// TwinCAT 3 PLC project PLC
// ProgramVersion: 3.1.4024.0
// libraries:
//   Tc2_ControllerToolbox, * (Beckhoff Automation GmbH)
//   Tc2_Standard, * (Beckhoff Automation GmbH)
//   Tc2_SUPS, * (Beckhoff Automation GmbH)
//   Tc2_System, * (Beckhoff Automation GmbH)
//   Tc2_TempController, * (Beckhoff Automation GmbH)
//   Tc2_Utilities, * (Beckhoff Automation GmbH)
//   Tc3_Module, * (Beckhoff Automation GmbH)
// project tree:
//   DUTs/Config/ ConfigChiller.TcDUT, ConfigDryPump.TcDUT, ConfigElectrostaticVoltageSource.TcDUT, ConfigEPD.TcDUT, ConfigHeater.TcDUT, ConfigHighTempChiller.TcDUT, ConfigIdleClean.TcDUT, ConfigMfcVer.TcDUT, ConfigMfcGas.TcDUT, ConfigPM.TcDUT, ConfigPump.TcDUT, ConfigPendulumValve.TcDUT, ConfigPurge.TcDUT, ConfigTurboPump.TcDUT
//   DUTs/DateType/ STR_PID.TcDUT, SVINT.TcDUT, SVLREAL.TcDUT
//   DUTs/ECC/APC/ APCControlAI.TcDUT, APCControlAO.TcDUT, APCControlDI.TcDUT, APCst.TcDUT, APC_Controller.TcDUT, CKD_IN.TcDUT, CKD_OUT.TcDUT, STR_APC.TcDUT, VAT_IN.TcDUT, VAT_OUT.TcDUT
//   DUTs/ECC/Axis/ STR_Axis_Panasonic.TcDUT, STR_Axis_Yaskawa.TcDUT
//   DUTs/ECC/BECKOFF/ STR_EL1889.TcDUT, STR_EL2889.TcDUT, STR_EL3154.TcDUT, STR_EL3164.TcDUT, STR_EL6022.TcDUT
//   DUTs/ECC/CHAMBER/ CHAMBER_IN.TcDUT, CHAMBER_OUT.TcDUT
//   DUTs/ECC/CHILLER/ CHILLER_IN.TcDUT, CHILLER_OUT.TcDUT
//   DUTs/ECC/EDWARDS/ TMP_IN.TcDUT, TMP_OUT.TcDUT
//   DUTs/ECC/HEATER/Mini8_16DI16DO/ STR_Mini8_16DI16DO_In.TcDUT, STR_Mini8_16DI16DO_Out.TcDUT
//   DUTs/ECC/HEATER/Mini8_8DI8DO/ STR_Mini8_8DI8DO_In.TcDUT, STR_Mini8_8DI8DO_Out.TcDUT
//   DUTs/ECC/HEATER/Mini8_XML/ STR_HEATER_LINE_CUS_IN.TcDUT, STR_HEATER_LINE_CUS_OUT.TcDUT, STR_HEATER_LINE_SYS_IN.TcDUT, STR_HEATER_LINE_SYS_OUT.TcDUT
//   DUTs/ECC/HEATER/ STR_HEATER_FURNACE.TcDUT, STR_HEATER_LINE.TcDUT
//   DUTs/ECC/IGS/ IGS_IN.TcDUT, IGS_OUT.TcDUT
//   DUTs/ECC/Meter/ Meter_Data.TcDUT
//   DUTs/ECC/MFC MFM/ STR_FCSP700_INPUT.TcDUT, STR_FCSP700_OUTPUT.TcDUT, STR_SEC_N107.TcDUT, STR_SEC_Z507.TcDUT, STR_SEF_N107.TcDUT, STR_SEF_Z507.TcDUT
//   DUTs/ECC/VALVE/ STR_EX260_SEC.TcDUT, STR_USINT_BOOL.TcDUT
//   DUTs/ECC/VG/ STR_BPG400.TcDUT, STR_CDG200D.TcDUT, VG_Data.TcDUT, VG_INPUT.TcDUT
//   DUTs/Info/ Intelock.TcDUT, ProcessRecipeFeedBack.TcDUT, Alarm.TcDUT, Warning.TcDUT, Info.TcDUT
//   DUTs/IO/ STR_AI.TcDUT, STR_AO.TcDUT, STR_NDI.TcDUT, STR_NDO.TcDUT
//   DUTs/Recipe/ Lst.TcDUT, RecipeEachStep.TcDUT
//   DUTs/Recipe/LST/ LstBIASUnit.TcDUT, LstGas.TcDUT, LstHeater.TcDUT, LstPressure.TcDUT, LstTCPUnit.TcDUT
//   DUTs/SPLC/ PLC_TO_SPLC.TcDUT, SPLC_TO_PLC.TcDUT
//   GVLs/ ECC.TcGVL, GV.TcGVL, GV_H.TcGVL, GV_IL.TcGVL
//   GVLs/PC_PLC/ PM.TcGVL, UI.TcGVL
//   / PlcTask.TcTTO
//   POUs/FB/ PID_AutoTune.TcPOU, PROCESS.TcPOU, RANGEJD.TcPOU, Temp_controller.TcPOU, Tolerance.TcPOU
//   POUs/PRG/ IL.TcPOU, IO_EXCHANGE.TcPOU, MAIN.TcPOU, Temp.TcPOU

CONFIGURATION PLC
    RESOURCE PLC ON TwinCAT3
        TASK PlcTask(INTERVAL := T#10ms, PRIORITY := 20);
        PROGRAM MAIN WITH PlcTask : MAIN;
    END_RESOURCE
END_CONFIGURATION

// ---- DUTs/Config/ConfigChiller.TcDUT
TYPE ConfigChiller :
STRUCT
	Enable:BOOL;
	MFG:SVINT;
	CommType:SVINT;
	Port:STRING;
	TempOffset:SVLREAL;
	MaxLimit:SVLREAL;
	MinLimit:SVLREAL;
	EnableAlarmTolerance:BOOL;
	ToleranceAlarmRange:SVINT;
	ToleranceAlarmTime:SVINT;
END_STRUCT
END_TYPE

// ---- DUTs/Config/ConfigDryPump.TcDUT
TYPE ConfigDryPump :
STRUCT
	MFG:SVINT;
	CommType:SVINT;
	Port:STRING;
	ChamberForlinePressureTolerance:SVLREAL;
	ChamberForlinePressureTimeout:SVINT;
END_STRUCT
END_TYPE

// ---- DUTs/Config/ConfigElectrostaticVoltageSource.TcDUT
TYPE ConfigElectrostaticVoltageSource :
STRUCT
	Port:STRING;
END_STRUCT
END_TYPE

// ---- DUTs/Config/ConfigEPD.TcDUT
TYPE ConfigEPD :
STRUCT
	IsEnabled:BOOL;
	ChannelNumber:SVINT;
	IPAdress:STRING;
	EPDType:SVINT;
END_STRUCT
END_TYPE

// ---- DUTs/Config/ConfigHeater.TcDUT
TYPE ConfigHeater :
STRUCT
	HeaterTolerance_Enable:BOOL;
	HeaterAlarmRange:SVINT;
	HeaterAlarmTime:SVINT;
	HeaterWarningRange:SVINT;
	HeaterWarningTime:SVINT;
(*	
	TempOffsetPoint1:SVINT;
		OffsetValue1:SVLREAL;
		
	TempOffsetPoint2:SVINT;
		OffsetValue2:SVLREAL;
		
	TempOffsetPoint3:SVINT;
		OffsetValue3:SVLREAL;
		
	TempOffsetPoint4:SVINT;
		OffsetValue4:SVLREAL;
		
	TempOffsetPoint5:SVINT;
		OffsetValue5:SVLREAL;
		
	TempOffsetPoint6:SVINT;
		OffsetValue6:SVLREAL;
		
	TempOffsetPoint7:SVINT;
		OffsetValue7:SVLREAL;
		
	TempOffsetPoint8:SVINT;
		OffsetValue8:SVLREAL;
		
	TempOffsetPoint9:SVINT;
		OffsetValue9:SVLREAL;
		
	TempOffsetPoint10:SVINT;
		OffsetValue10:SVLREAL;
		*)
END_STRUCT
END_TYPE

// ---- DUTs/Config/ConfigHighTempChiller.TcDUT
TYPE ConfigHighTempChiller :
STRUCT
	LiftServoPosition1:SVLREAL;
	LiftServoPosition2:SVLREAL;
	LiftServoPosition3:SVLREAL;
	LiftServoPosition4:SVLREAL;
	LiftServoPosition5:SVLREAL;
	
	OriginSearchHighSpeed:SVLREAL;
	OriginSearchLowSpeed:SVLREAL;
	
	AbsMoveSpeed:SVLREAL;
	MaxMoveSpeed:SVLREAL;
	
	SoftDownLimit:SVLREAL;
	SoftUpLimit:SVLREAL;
END_STRUCT
END_TYPE

// ---- DUTs/Config/ConfigIdleClean.TcDUT
TYPE ConfigIdleClean :
STRUCT
	Option:SVINT;
	
	IdleCleanRecipe:STRING;
	IdleCleanTime:SVINT;
	IdleCleanWaferCount:SVINT;
	
	WaferCountSinceLastClean:SVINT;
	LastRunTime:STRING;
END_STRUCT
END_TYPE

// ---- DUTs/Config/ConfigMfcVer.TcDUT
TYPE ConfigMfcVer :
STRUCT
	BasePressure:SVLREAL;
	PumpingTime:SVINT;
	GasFlowTime:SVINT;
	HoldTime:SVINT;
	TargetPressure:SVLREAL;
	MaxDeviation:SVLREAL;
	PressureStableTolerance:SVLREAL;
	FlowStableTolerance:SVLREAL;
END_STRUCT
END_TYPE

// ---- DUTs/Config/ConfigMfcGas.TcDUT
TYPE ConfigMfcGas :
STRUCT
	Enable:BOOL;
	GasName:STRING;
	N2Scale:SVINT;
	ScaleFactor:SVLREAL;
	DefaultSV:SVINT;
	FlowRegulationFactor:SVINT;
	EnableAlarm:BOOL;
	AlarmRange:SVINT;
	AlarmTime:SVINT;
	WarningRange:SVINT;
	WarningTime:SVINT;
	WriteMode:SVINT;
END_STRUCT
END_TYPE

// ---- DUTs/Config/ConfigPM.TcDUT
TYPE ConfigPM :
STRUCT
	//TurboN2FlowSetPoint:LREAL;			//0-200		mtorr
	TurboN2Pressure:INT;
	PrepareTransferTimeout:INT;				//1-99999	s
	TransferWaferTimeout:INT;				//1-99999	s
	OpenGasValveTimeout:INT;				//0-60		s
	CloseGasValveTimeout:INT;				//0-10
	OpenCloseSlitValveTimeout:INT;			//0-10
	GasFlowPressureAlarmRange:LREAL;		//0-760000	mtorr
	GasFlowPressureAlarmTime:LREAL;			//0-3600	s
	GasFlowPressureWarningRange:LREAL;		//0-760000	mtorr
	GasFlowPressureWarningTime:LREAL;		//0-3600	s
	EnableThrottleValve:BOOL;				//0-10				//不清楚作用
	ValveHeaterSetPointLimit:INT;			//0-500
	ForeLineHeaterSetPointLimit:INT;		//0-500
	CheckSubstrateTempTimeout:INT;			//0-3600			//不清楚作用
	CheckATMTimeout:INT;					//0-3000	s
	OverVentTime:UINT;						//0-60000	ms		充气至常压
	ChamberBasePressureThreshold:UDINT;		//0-1000000	mtorr	腔体基础压力门槛	工艺开始压力？腔体压力下限？
	ChamberBaseTemperatureThreshold:LREAL;	//0-1000	℃		腔体基础温度门槛	工艺开始温度？腔体温度下限？
	ProcessPressureOffset:LREAL;			//0-100		mtorr
	PickDelayTime:INT;						//0-10000	ms
	PlaceDelayTime:INT;						//0-10000	ms
	ChamberLabel:STRING;					//''
	WallHeaterSetPointLimit:INT;			//0-500
	PendulumHeaterSetPointLimit:INT;		//0-500
	EnableWallHeater:BOOL;					//0-10
	EnableGridHeater:BOOL;					//0-10
	(*RecipeToleranceIgnoreTime:INT;		//0-60		s	Tolerance失效时间,用不到*)
	RecipeRunningMode:INT;					//0-5
	ForelineInterlockPressure:LREAL;		//500-2000	℃
	IsEnableRecipeExtension:BOOL;			//0-10
	ControlPressureSetPoint:INT;			//0-2000	mtorr
	ControlPressureN2FlowSetPoint:INT;		//0-500		sccm	
	PMStableTime:INT;						//0-100		s
END_STRUCT
END_TYPE

// ---- DUTs/Config/ConfigPump.TcDUT
TYPE ConfigPump :
STRUCT
	LeakRate:SVLREAL;
	
	LeakCheckPumpingTime:SVINT;
	LeakCheckHoldTime:SVINT;
	
	PumpBasePressure:SVINT;
	LeakCheckBasePressur:SVLREAL;
	
	LeakCheckGasLineNums:STRING;
	
	PumpTimeLimit:SVLREAL;
	PumpValveDelay:SVINT;
	
	PumpCrossingPressure:SVINT;
	PumpVHe2FlowPressure:SVINT;
	
	LoadLockPumpBasePressure:SVINT;
	LoadLockPumpTimeLimit:SVINT;
	
	LoadLockPurgeVentPressure:SVINT;
	LoadLockPurgeCycleCount:SVINT;
	LoadLockPurgePumpTime:SVINT;
	
	LoadLockLeakCheckPumpTime:SVINT;
	LoadLockLeakCheckWaitTime:SVINT;
	LoadLockLeakRate:SVLREAL;
END_STRUCT
END_TYPE

// ---- DUTs/Config/ConfigPendulumValve.TcDUT
TYPE ConfigPendulumValve :
STRUCT
	Port:STRING;
	PressureFullRange:SVINT;
	ForelinePressureLimit:SVINT;
	ChamberPressureLimit:SVINT;
	TurboPumpSpeedLimit:SVINT;
END_STRUCT
END_TYPE

// ---- DUTs/Config/ConfigPurge.TcDUT
TYPE ConfigPurge :
STRUCT
	PurgeCycleCount:SVINT;
	
	PurgeVentPressure:SVINT;
	PurgePumpPressure:SVINT;
	
	PurgeVentTimeLimit:SVINT;
	PurgePumpTimeLimit:SVINT;
	
	PurgeVentStableTime:SVINT;
	PurgePumpTime:SVINT;
	
	GasPurgeCycleCount:SVINT;
	GasPurgeFlowTime:SVINT;
	GasPurgePumpTime:SVINT;
END_STRUCT
END_TYPE

// ---- DUTs/Config/ConfigTurboPump.TcDUT
TYPE ConfigTurboPump :
STRUCT
	Port:STRING;
	ChamberForelinePressureThreshold:SVLREAL;
	ChamberForelinePressureTimeout:SVINT;
END_STRUCT
END_TYPE

// ---- DUTs/DateType/STR_PID.TcDUT
TYPE STR_PID :
STRUCT
	P,
	I,
	D,
	DP,
	Feedforward,
	Output_Limit:REAL;
END_STRUCT
END_TYPE

// ---- DUTs/DateType/SVINT.TcDUT
TYPE SVINT :
STRUCT
	MinSV:INT;
	MaxSV:INT;
	PV:INT;
	SV:INT;
END_STRUCT
END_TYPE

// ---- DUTs/DateType/SVLREAL.TcDUT
TYPE SVLREAL :
STRUCT
	MinSV:LREAL;
	MaxSV:LREAL;
	PV:LREAL;
	SV:LREAL;
END_STRUCT
END_TYPE

// ---- DUTs/ECC/APC/APCControlAI.TcDUT
TYPE APCControlAI :
STRUCT
	Value_sensor_input1_p1	:	REAL	;
	Value_sensor_input1_p2	:	REAL	;
	Select_controller_using	:	REAL	;
	Position_actual_value	:	REAL	;
	Control_mode_status	:	REAL	;
	HOME_status	:	REAL	;
	Warning_Device_Management	:	REAL	;
	Warning_Sensor_Input1	:	REAL	;
	Warning_Sensor_Input2	:	REAL	;
	Warning_Process_Controller_Selector	:	REAL	;
	Warning_Valve	:	REAL	;
	Manufacturer_Warning_Valve	:	REAL	;
	ERROR_Device_Management	:	REAL	;
	ERROR_sensor_input1_p1	:	REAL	;
	ERROR_sensor_input1_p2	:	REAL	;
	ERROR_Valve	:	REAL	;

END_STRUCT
END_TYPE

// ---- DUTs/ECC/APC/APCControlAO.TcDUT
TYPE APCControlAO :
STRUCT
	Zero_Reset_P1	:	REAL	;
	Zero_adjust_P1	:	REAL	;
	Span_adjust_P1	:	REAL	;
	Zero_Reset_P2	:	REAL	;
	Zero_adjust_P2	:	REAL	;
	Span_adjust_P2	:	REAL	;
	Slow_vacuum_control_target_vacuum_Pressure	:	REAL	;
	Valve_status_threshold	:	REAL	;
	Forbid_interlock_outbreak	:	REAL	;
	Slow_vacuum_mode_setting	:	REAL	;
	Interlock1	:	REAL	;
	Interlock2	:	REAL	;
	Interlock3	:	REAL	;
	Interlock_constant_of_interlock3	:	REAL	;
	P1_sensor_offset_setting	:	REAL	;
	Pos_mon_offset_setting	:	REAL	;
	Sensor_adjust_reset	:	REAL	;
	Slow_vacuum_rate	:	REAL	;
	Slow_vacuum_control_P	:	REAL	;
	Slow_vacuum_control_I	:	REAL	;
	Slow_vacuum_control_D	:	REAL	;
	Slow_vacuum_control_a	:	REAL	;
	controller_mode_select	:	REAL	;
	Specify_target_vacuum_Pressure_control	:	REAL	;
	Specify_target_opening_for_valve_opening_control	:	REAL	;
	Specify_control_mode	:	REAL	;
	Range_Upper_Limit_Sensor_Input1	:	REAL	;
	Range_Upper_Limit_Sensor_Input2	:	REAL	;

END_STRUCT
END_TYPE

// ---- DUTs/ECC/APC/APCControlDI.TcDUT
TYPE APCControlDI :
STRUCT
	P1ZeroOffsetOutRangeAlm_b	:	BOOL	;
	P1ZeroAdjOutRangeAlm_b	:	BOOL	;
	P1SpanAdjOutRangeAlm_b	:	BOOL	;
	P2ZeroOffsetOutRangeAlm_b	:	BOOL	;
	P2ZeroAdjOutRangeAlm_b	:	BOOL	;
	P2SpanAdjOutRangeAlm_b	:	BOOL	;
	P1PressCtrlInterlockAlm_b	:	BOOL	;
	P2PressCtrlInterlockAlm_b	:	BOOL	;
	ValveOpenCtrlInterlockAlm_b	:	BOOL	;
	ValveHoldCtrlInterlockAlm_b	:	BOOL	;
	ValveCloseInterlockAlm_b	:	BOOL	;
	AutoTeachingInterlockAlm_b	:	BOOL	;
	P1DisconnectionAlm_b	:	BOOL	;
	P2DisconnectionAlm_b	:	BOOL	;
	PumpStopInterlockAlm_b	:	BOOL	;
	AutoTeachingErr1Alm_b	:	BOOL	;
	AutoTeachingErr2Alm_b	:	BOOL	;
	Spare1_b	:	BOOL	;
	Spare2_b	:	BOOL	;
	Spare3_b	:	BOOL	;
	Spare4_b	:	BOOL	;
	Spare5_b	:	BOOL	;
	Spare6_b	:	BOOL	;
	Spare7_b	:	BOOL	;
	Spare8_b	:	BOOL	;
	Spare9_b	:	BOOL	;
	SpareA_b	:	BOOL	;
	SpareB_b	:	BOOL	;
	SpareC_b	:	BOOL	;
	SpareD_b	:	BOOL	;
	SpareE_b	:	BOOL	;
	SpareF_b	:	BOOL	;

END_STRUCT
END_TYPE

// ---- DUTs/ECC/APC/APCst.TcDUT
TYPE APCst :
STRUCT
	Enable_b	:	BOOL	;	//	
	P1ZeroOffsetOutRangeAlm_b	:	BOOL	;	//	
	P1ZeroAdjOutRangeAlm_b	:	BOOL	;	//	
	P1SpanAdjOutRangeAlm_b	:	BOOL	;	//	
	P2ZeroOffsetOutRangeAlm_b	:	BOOL	;	//	
	P2ZeroAdjOutRangeAlm_b	:	BOOL	;	//	
	P2SpanAdjOutRangeAlm_b	:	BOOL	;	//	
	P1PressCtrlInterlockAlm_b	:	BOOL	;	//	
	P2PressCtrlInterlockAlm_b	:	BOOL	;	//	
	ValveOpenCtrlInterlockAlm_b	:	BOOL	;	//	
	ValveHoldCtrlInterlockAlm_b	:	BOOL	;	//	
	ValveCloseInterlockAlm_b	:	BOOL	;	//	
	AutoTeachingInterlockAlm_b	:	BOOL	;	//	
	P1DisconnectionAlm_b	:	BOOL	;	//	
	P2DisconnectionAlm_b	:	BOOL	;	//	
	PumpStopInterlockAlm_b	:	BOOL	;	//	
	AutoTeachingErr1Alm_b	:	BOOL	;	//	
	AutoTeachingErr2Alm_b	:	BOOL	;	//	
	Spare2_b	:	BOOL	;	//	
	Spare3_b	:	BOOL	;	//	
	Spare4_b	:	BOOL	;	//	
	Spare5_b	:	BOOL	;	//	
	Spare6_b	:	BOOL	;	//	
	Spare7_b	:	BOOL	;	//	
	Spare8_b	:	BOOL	;	//	
	Spare9_B	:	BOOL	;	//	
	SpareA_b	:	BOOL	;	//	
	SpareB_b	:	BOOL	;	//	
	SpareC_b	:	BOOL	;	//	
	SpareD_b	:	BOOL	;	//	
	SpareE_b	:	BOOL	;	//	
	SpareF_b	:	BOOL	;	//	
	PosMonOffsetSetting_Int	:	INT	;	//	-12000
	Spare3_Int	:	INT	;	//	
	Spare4_Int	:	INT	;	//	
	Spare5_Int	:	INT	;	//	
	Spare6_Int	:	INT	;	//	
	Spare7_Int	:	INT	;	//	
	Spare8_Int	:	INT	;	//	
	Spare9_Int	:	INT	;	//	
	SlowVccModeSetting_Usint	:	USINT	;	//	0,1
	ActiveControllerSetting_Usint	:	USINT	;	//	initial:0,0-255
	ControlModeSet_Usint	:	USINT	;	//	initial:0,0-255
	P1RangeUpLimitSet_Usint	:	USINT	;	//	initial:3,1-5
	P2RangeUpLimitSet_Usint	:	USINT	;	//	initial:5,1-5
	ControllerSelectFdbk_Usint	:	USINT	;	//	
	ControlModeFdbk_Usint	:	USINT	;	//	
	DisableInterlock_Usint	:	USINT	;	//	0,1
	HomingStatus_Usint	:	USINT	;	//	
	P1ZeroRst_Usint	:	USINT	;	//	0,1
	P1ZeroAdj_Usint	:	USINT	;	//	0,1
	P1SpanAdj_Usint	:	USINT	;	//	0,1
	P2ZeroRst_Usint	:	USINT	;	//	0,1
	P2ZeroAdj_Usint	:	USINT	;	//	0,1
	P2SpanAdj_Usint	:	USINT	;	//	0,1
	Spare16_Usint	:	USINT	;	//	
	Spare17_Usint	:	USINT	;	//	
	Spare18_Usint	:	USINT	;	//	
	Spare19_Usint	:	USINT	;	//	
	Spare20_Usint	:	USINT	;	//	
	SlowVccTargetPresSV_Real	:	REAL	;	//	0-93325.68
	ValveStatusThresholdSV_Real	:	REAL	;	//	initial:3.57,0.36-17.86
	Interlock1Setting_Real	:	REAL	;	//	initial:1.5,0-100
	Interlock2Setting_Real	:	REAL	;	//	initial:10,0.1-100
	Interlock3Setting_Real	:	REAL	;	//	initial:10,0.1-100
	IntegrationConstantIntlk3Set_Real	:	REAL	;	//	initial:100,0.1-100
	P1OffsetSetting_Real	:	REAL	;	//	initial:0,-15-15
	SlowVccRateSV_Real	:	REAL	;	//	initial:0.1,0.1-20
	SlowVccPIDSV_P_Real	:	REAL	;	//	initial:0.2,0.01-9.99
	SlowVccPIDSV_I_Real	:	REAL	;	//	initial:0.2,0.00-9.99
	SlowVccPIDSV_D_Real	:	REAL	;	//	initial:0.4,0.00-9.99
	SlowVccSensorPIDSV_D_Real	:	REAL	;	//	initial:1,0.00-9.99
	ProcessPointSV_Real	:	REAL	;	//	initial:0,0-93325.68
	PositionPointSV_Real	:	REAL	;	//	initial:0,0-100
	Controller1SV_P_Real	:	REAL	;	//	initial:2.0,0.01-9.99
	Controller1SV_I_Real	:	REAL	;	//	initial:0.5,0.00-9.99
	Controller1SV_D_Real	:	REAL	;	//	initial:0.3,0.00-9.99
	Controller1SensorSV_D_Real	:	REAL	;	//	initial:0.3,0.00-9.99
	Controller1CHSV_Real	:	REAL	;	//	initial:53.57,0.36-98.21
	Controller1CLSV_Real	:	REAL	;	//	initial:1.79,0.36-98.21
	Controller2SV_P_Real	:	REAL	;	//	initial:2.0,0.01-9.99
	Controller2SV_I_Real	:	REAL	;	//	initial:0.5,0.00-9.99
	Controller2SV_D_Real	:	REAL	;	//	initial:0.3,0.00-9.99
	Controller2SensorSV_D_Real	:	REAL	;	//	initial:0.3,0.00-9.99
	Controller2CHSV_Real	:	REAL	;	//	initial:53.57,0.36-98.21
	Controller2CLSV_Real	:	REAL	;	//	initial:1.79,0.36-98.21
	Controller3SV_P_Real_Copy	:	REAL	;	//	initial:2.0,0.01-9.99
	Controller3SV_I_Real_Copy	:	REAL	;	//	initial:0.5,0.00-9.99
	Controller3SV_D_Real_Copy	:	REAL	;	//	initial:0.3,0.00-9.99
	Controller3SensorSV_D_Real_Copy	:	REAL	;	//	initial:0.3,0.00-9.99
	Controller3CHSV_Real_Copy	:	REAL	;	//	initial:53.57,0.36-98.21
	Controller3CLSV_Real_Copy	:	REAL	;	//	initial:1.79,0.36-98.21
	Spare6_Real	:	REAL	;	//	
	Spare7_Real	:	REAL	;	//	
	Spare8_Real	:	REAL	;	//	
	Spare9_Real	:	REAL	;	//	
	Spare10_Real	:	REAL	;	//	
	P1PressurePV_Real	:	REAL	;	//	
	P2PressurePV_Real	:	REAL	;	//	
	PostionActualValueFdbk_Real	:	REAL	;	//	
	OffsetForController1_UDINT	:	UDINT	;	//	initial:0,-999-999
	OffsetForController2_UDINT	:	UDINT	;	//	
	OffsetForController3_UDINT	:	UDINT	;	//	
	P1SetAlarm_UDINT	:	UDINT	;	//	
	P2SetAlarm_UDINT	:	UDINT	;	//	
	InterlockAlarm_UDINT	:	UDINT	;	//	
	P1DisconnectionAlarm_UDINT	:	UDINT	;	//	
	P2DisconectionAlarm_UDINT	:	UDINT	;	//	
	ManufactureErr_UDINT	:	UDINT	;	//	
	Spare10_UDINT	:	UDINT	;	//	

END_STRUCT
END_TYPE

// ---- DUTs/ECC/APC/APC_Controller.TcDUT
TYPE APC_Controller :
STRUCT
	P	:	REAL	;
	I	:	REAL	;
	D	:	REAL	;
	a	:	REAL	;
	CH	:	REAL	;
	CL	:	REAL	;
	OFFSET	:	REAL	;

END_STRUCT
END_TYPE

// ---- DUTs/ECC/APC/CKD_IN.TcDUT
TYPE CKD_IN :
STRUCT
	WcStateOut	:	BIT	;		
	Value_Sensor_Input1	:	REAL	;	//	Value sensor input1 (p1)
	Value_Sensor_Input2	:	REAL	;	//	Value sensor input2 (p2)
	Position_Actual_Value	:	REAL	;	//	Position actual value 
	Control_Mode_Status	:	USINT	;//	"Control mode status:
									(*	Indicates the current controlmode.
									O: IDLE
									1:HOMING(Auto teaching)
									2: POS(Valve Opening Control
									3: Reserved
									4: HOID(Valve Opening Hld)
									5:CLOSE(Close)
									6:OPEN(Open
									7:PRESS1(P1 SensorVacuum Pessure Control
									8:PRESS2(P2 SensorVacuum Pressure Control
									9 to 15: Reserved
									16:SIOWVAC(Sow Vacuum Control"
									*)	
	Homing_Status	:	USINT	;	//	"HOME status
									(*
									indicates the homing status.
									0: Homing not started
									1: Homing interrupted
									2: Homing completed-no error
									3:Homing completed-error204: Hmingin progress
									5to 255: Reserved"
									*)
	
	Selected_Controller	:	USINT	;	//	"Select controller
											(*
											Indicates The PIDtables used.
											1: 0x8060(rocess Controller 1)
											2:0x8070(Pocess Cntroller2)
											3:0x8080(cess Cntroller3)
											4:0x8090(Process Cntroller 4)
											5:0x80A0(Process Controller5)
											6:0x80M(Pocess ntroller6
											7:0x80C0(Process Controller 7
											8:0x80D0(Process Cntroller8
											9:0x80E(Pocess Controller 9)
											10: 0x80F(Pocess Controller 10)
											11: 0x5050(SVA0"
											*)
	Device_Management_Device_Warning_Details	:	UDINT	;	//	Active Device Warning Details (Device Management)
	Sensor_Input1_Device_Warning_Details	:	UDINT	;	//	Active Device Warning Details (Sensor put1)
	Sensor_Input2_Device_Warning_Details	:	UDINT	;	//	Active Device Warning Details (Sensor Input2)
	Process_Controller_Selector_Device_Warning_Details	:	UDINT	;	//	Active Device Warning Details (Process Controller Selector)
	Valve_Device_Warning_Details	:	UDINT	;	//	Active Device Warning Details (Valve)
	Valve_manufacturer_Warning_Details	:	UDINT	;	//	Active manufacturer Warning Details (Valve)
	Device_Management_manufacturer_Error_Details	:	UDINT	;	//	Active manufacturer Error Details (Device Management)
	Sensor_Input1_Management_manufacturer_Error_Details	:	UDINT	;	//	Active manufacturer Error Details(Sensor Input1)
	Sensor_Input2_Management_manufacturer_Error_Details	:	UDINT	;	//	Active manufacturer Error Details (Sensor Input2)
	Valve_Management_manufacturer_Error_Details	:	UDINT	;	//	Active manufacturer Error Details (Valve)
	WcStateIn	:	BIT	;	//	
	InputToggle	:	BIT	;	//	
	State	:	UINT	;	//	

END_STRUCT
END_TYPE

// ---- DUTs/ECC/APC/CKD_OUT.TcDUT
TYPE CKD_OUT :
STRUCT
	Control_Mode	:	USINT	;
	Process_Setpoint	:	REAL	;
	Position_Setpoint	:	REAL	;
	Exh_Rate	:	REAL	;
	Active_Controller	:	USINT	;
	Slow_exhaust_control_arrival_pressure	:	REAL	;

END_STRUCT
END_TYPE

// ---- DUTs/ECC/APC/STR_APC.TcDUT
TYPE STR_APC :
STRUCT
	Outputs_Valve_Default_Control_Mode_7100_13						:	USINT	;
	Outputs_Process_Controller_Process_Setpoint_7050_13				:	REAL	;
	Outputs_Valve_Default_Position_Setpoint_7100_12					:	REAL	;
	Outputs_Process_Controller_Exh_Rate_5050_01						:	REAL	;
	Outputs_Process_Controller_Active_Controller_7050_11			:	USINT	;
	Outputs_Process_Controller_Slow_exhaust_control_arriva_4050_01	:	REAL	;
	Inputs_Sensor_Input_Defau_Value_6030_11							:	REAL	;
	Inputs_Sensor_Input_Defau_Value_6040_11							:	REAL	;
	Inputs_Valve_Default_Position_Actual_Value_6100_11				:	REAL	;
	Inputs_Valve_Default_Control_Mode_Status_6100_14				:	USINT	;
	Inputs_Valve_Default_Homing_Status_6100_15						:	USINT	;
	Inputs_Process_Controller_Selected_Controller_6050_14			:	USINT	;
	Inputs_Active_Device_Warni_SubIndex_001_F381_01					:	UDINT	;
	Inputs_Active_Device_Warni_SubIndex_003_F381_03					:	UDINT	;
	Inputs_Active_Device_Warni_SubIndex_004_F381_04					:	UDINT	;
	Inputs_Active_Device_Warni_SubIndex_005_F381_05					:	UDINT	;
	Inputs_Active_Device_Warni_SubIndex_016_F381_10					:	UDINT	;
	Inputs_Active_Manufacturer_SubIndex_016_F382_10					:	UDINT	;
	Inputs_Active_Manufacturer_SubIndex_001_F384_01					:	UDINT	;
	Inputs_Active_Manufacturer_SubIndex_003_F384_03					:	UDINT	;
	Inputs_Active_Manufacturer_SubIndex_004_F384_04					:	UDINT	;
	Inputs_Active_Manufacturer_SubIndex_016_F384_10					:	UDINT	;	
END_STRUCT
END_TYPE

// ---- DUTs/ECC/APC/VAT_IN.TcDUT
TYPE VAT_IN :
STRUCT
	Actual_Pressure	:	REAL	;
	Pressure_Sensor_1	:	REAL	;
	Pressure_Sensor_2	:	REAL	;
	Actual_Position	:	REAL	;
	Control_Mode	:	SINT	;			(*
											CONTROL MODE:	
											1=HOMING
											2=POSITION
											3=CLOSE
											4=OPEN
											5=PRESSURE
											6=HOLD:KEEP IN CURRENT POSITION
											7=LEARN:INTERNAL LEARN PROCEDURE
											*)
	Error_Number	:	UINT	;
	General_Status	:	UINT	;			(*
											BIT 0	FIELDBUS DATA VALID 
													0 = Valve is not in the EtherCAT state OPERATIONAL or the process data output 
													watchdog 
													(SyncManager2) is disabled 
													1 = Valve is in the EtherCAT state OPERATIONAL and the process data output 
													watchdog 
													(SyncManager2) is enabled 
											BIT 1 ZERO ADJUST EXECUTED 
													ZERO ADJUST successful executed, active for 2 seconds 
											BIT 2 PING PONG RX-BIT 
													PING PONG RX BIT, is inverted and transmitted back to the fieldbus master (PLC) 
											BIT 3 PRESSURE SIMULATION 
													0 = off 
													1 = on 
											BIT 4 TARGET PRESSURE REACHED 
													0 = The actual pressure is not within 2% of the pressure setpoint 
													1 = The actual pressure is within 2% of the pressure setpoint 
											BIT 5-6 NOT USED (reserved) - 
											BIT 7-8 ACCESS MODE 
											bit 8	bit 7
												0 		0 	= LOCAL 
												0 		1 	= REMOTE 
												1 		0 	= LOCKED 
											BIT 9 WARNINGS ACTIVE 
													0 = No WARNINGS 
													1 = At least one WARNING of the warning bitmaps is active (GENERAL 
														WARNING bitmap and EXTENDED WARNING bitmap) 
											BIT 10 SEALING STATE 
													Only valid if a sealing functionality is available.
													0 = valve is not sealed 
													1 = valve is sealed 
											BIT 11 INTERLOCK ACTIVE 
													Is set if an interlock input is active 
											BIT 12-15 NOT USED (reserved) -
											*)
	General_Warnings	:	UINT	;		(*
											BIT 0 NOT USED (reserved) - 
											BIT 1 LEARN DATA SET 
													Learn data not present. Learn required for adaptive pressure control. 
													Just active if adaptive pressure control algorithm is choosen. 
											BIT 2 NOT USED (reserved) - 
											BIT 3 POWER FAILURE BATTERY 
													Not ready, voltage too low. 
													Just active if power failure is available. 
											4-15 NOT USED (reserved) -
											*)
	Extended_Warnings	:	UINT	;		(*
											BIT 0 REMOTE CONTROL NOT POSSIBLE 
													Remote control not possible, access mode local is active, change to acces mode 
													remote or access mode locked 
											BIT 1 ACTUAL CONTROL MODE SETPOINT NOT ALLOWED 
													Not possible to switch the actual control mode to CONTROL MODE SETPOINT 
													• Control mode is interlock or fatal error 
													• CONTROL MODE SETPOINT is 5 (pressure) or 7 (learn) and no sensor 
													  is selected (sensor mode configuration) 
											BIT 2 ZERO DISABLED 
													Using zero function not possible 
											BIT 3 PFO DEACTIVATED 
													Power Failure Option is deactivated 
											BIT 4 NOT USED (reserved) - 
											BIT 5 OUT OF RANGE: PRESSURE SETPOINT 
													Value of PRESSURE SETPOINT is out of range 
											BIT 6 OUT OF RANGE: POSITION SETPOINT 
													Value of POSITION SETPOINT is out of range 
											BIT 7-9 NOT USED (reserved) - 
											BIT 10 OUT OF RANGE: CONTROL MODE SETPOINT 
													Value of CONTROL MODE SETPOINT is out of range 
											BIT 11 OUT OF RANGE: GENERAL CONTROL SETPOINT 
													Value of GENERAL CONTROL SETPOINT is out of range 
											BIT 12-15 NOT USED (reserved) -
											*)
END_STRUCT
END_TYPE

// ---- DUTs/ECC/APC/VAT_OUT.TcDUT
TYPE VAT_OUT :
STRUCT
	Target_Pressure	:	REAL	;
	Target_Position	:	REAL	;
	Pressure_Input_Digital_Sensor_1	:	REAL	;
	Pressure_Input_Digital_Sensor_2	:	REAL	;
	Control_Mode	:	SINT	;						(*	0 = init 
															1 = homing 
															2 = position 
															3 = close 
															4 = open 
															5 = pressure 
															6 = hold 
															7 = learn 
															8 = interlock open 
															9 = interlock close 
															12 = power failure 
															13 = safety 
															14 = fatal error
														*)
	General_Control_Setpoint	:	UINT	;
	Pressure_Ramp_Time	:	REAL	;
END_STRUCT
END_TYPE

// ---- DUTs/ECC/Axis/STR_Axis_Panasonic.TcDUT
TYPE STR_Axis_Panasonic :
STRUCT
	Receive_Controlword_6040_00						:UINT;
	Receive_Modes_of_operation_6060_00				:SINT;
	Receive_Target_position_607A_00					:DINT;
	Receive_Touch_probe_function_60B8_00			:UINT;
	Receive_Home_offset_607C_00						:DINT;
	Receive_Speed_during_search_for_swi_6099_01		:UDINT;
	Receive_Speed_during_search_for_zer_6099_02		:UDINT;
	Receive_Homing_acceleration_609A_00				:UDINT;
	Receive_Homing_method_6098_00					:SINT;
	Transmit_Error_code_603F_00						:UINT;
	Transmit_Statusword_6041_00						:UINT;
	Transmit_Modes_of_operation_display_6061_00		:SINT;
	Transmit_Position_actual_value_6064_00			:DINT;
	Transmit_Velocity_actual_value_606C_00			:DINT;
	Transmit_Torque_actual_value_6077_00			:INT;
	Transmit_Touch_probe_status_60B9_00				:UINT;
	Transmit_Touch_probe_pos1_pos_value_60BA_00		:DINT;
	Transmit_Touch_probe_pos1_neg_value_60BB_00		:DINT;
	Transmit_Digital_inputs_60FD_00					:UDINT;
END_STRUCT
END_TYPE

// ---- DUTs/ECC/Axis/STR_Axis_Yaskawa.TcDUT
TYPE STR_Axis_Yaskawa :
STRUCT
	
END_STRUCT
END_TYPE

// ---- DUTs/ECC/BECKOFF/STR_EL1889.TcDUT
TYPE STR_EL1889 :
STRUCT
	In_Bit0		:	BOOL	;
	In_Bit1		:	BOOL	;
	In_Bit2		:	BOOL	;
	In_Bit3		:	BOOL	;
	In_Bit4		:	BOOL	;
	In_Bit5		:	BOOL	;
	In_Bit6		:	BOOL	;
	In_Bit7		:	BOOL	;
	In_Bit8		:	BOOL	;
	In_Bit9		:	BOOL	;
	In_Bit10		:	BOOL	;
	In_Bit11		:	BOOL	;
	In_Bit12		:	BOOL	;
	In_Bit13		:	BOOL	;
	In_Bit14		:	BOOL	;
	In_Bit15		:	BOOL	;

END_STRUCT
END_TYPE

// ---- DUTs/ECC/BECKOFF/STR_EL2889.TcDUT
TYPE STR_EL2889 :
STRUCT
	Out_Bit0		:	BOOL	;
	Out_Bit1		:	BOOL	;
	Out_Bit2		:	BOOL	;
	Out_Bit3		:	BOOL	;
	Out_Bit4		:	BOOL	;
	Out_Bit5		:	BOOL	;
	Out_Bit6		:	BOOL	;
	Out_Bit7		:	BOOL	;
	Out_Bit8		:	BOOL	;
	Out_Bit9		:	BOOL	;
	Out_Bit10		:	BOOL	;
	Out_Bit11		:	BOOL	;
	Out_Bit12		:	BOOL	;
	Out_Bit13		:	BOOL	;
	Out_Bit14		:	BOOL	;
	Out_Bit15		:	BOOL	;

END_STRUCT
END_TYPE

// ---- DUTs/ECC/BECKOFF/STR_EL3154.TcDUT
TYPE STR_EL3154 :		//4AI,4-20mA,16bits
STRUCT
	AI1		:INT;
	AI2		:INT;
	AI3		:INT;
	AI4		:INT;
END_STRUCT
END_TYPE

// ---- DUTs/ECC/BECKOFF/STR_EL3164.TcDUT
TYPE STR_EL3164 :		//4AI,0-10V,16bits
STRUCT
	AI1		:INT;
	AI2		:INT;
	AI3		:INT;
	AI4		:INT;
END_STRUCT
END_TYPE

// ---- DUTs/ECC/BECKOFF/STR_EL6022.TcDUT
TYPE STR_EL6022 :
STRUCT
	//将EL6022上面的2 3短接，7 8短接
	DATAIN1:ARRAY[0..21] OF USINT;
	DATAIN2:ARRAY[0..21] OF USINT;
	DATAOUT1:ARRAY[0..21] OF USINT;
	DATAOUT2:ARRAY[0..21] OF USINT;
END_STRUCT
END_TYPE

// ---- DUTs/ECC/CHAMBER/CHAMBER_IN.TcDUT
TYPE CHAMBER_IN :
STRUCT
	//C02 	EL1889 16DI
	C02		:ARRAY [1..16] OF BOOL;
	
	
	//C03	EL1889 16DI
	C03		:ARRAY [1..16] OF BOOL;
	
	//C04	EL3318	8TC
	C04		:ARRAY [1..8] OF INT;
	
	
	//C05	EL3318	8TC
	C05		:ARRAY [1..8] OF INT;
	
	
	//C06	EL3164	4AI	0-10V
	C06		:ARRAY [1..4] OF INT;
			
	//C10 	EL9410	POWER MODULE
	
	//C11	EL1918	SPLC+8SDI
	C11		:ARRAY [1..8] OF BOOL;
		
	//C12	EL1904	4SDI
	C12		:ARRAY [1..4] OF BOOL;
	
	
	//C13	EL1904	4SDI
	C13		:ARRAY [1..4] OF BOOL;
	
	//C15	EL3318	8TC
	C15		:ARRAY [1..8] OF INT;
	
END_STRUCT
END_TYPE

// ---- DUTs/ECC/CHAMBER/CHAMBER_OUT.TcDUT
TYPE CHAMBER_OUT :
STRUCT
	//C07	EL2889 16DO
	C07		:ARRAY [1..16] OF BOOL;
	
	
	//C08	EL2889	16DO
	C08		:ARRAY [1..16] OF BOOL;
	
	
	//C09	EL2889	16DO
	C09		:ARRAY [1..16] OF BOOL;
	
	//C14	EL2904	4SDO
	C14		:ARRAY [1..4] OF BOOL;
END_STRUCT
END_TYPE

// ---- DUTs/ECC/CHILLER/CHILLER_IN.TcDUT
TYPE CHILLER_IN :
STRUCT
	Module1_Word:ARRAY [1..2] OF UINT;	
	Module2_Word:ARRAY [1..16] OF UINT;
//	Module3_Word:ARRAY [1..16] OF UINT;	
END_STRUCT
END_TYPE

// ---- DUTs/ECC/CHILLER/CHILLER_OUT.TcDUT
TYPE CHILLER_OUT :
STRUCT
	Module1_Word:ARRAY [1..2] OF UINT;	
	Module2_Word:ARRAY [1..16] OF UINT;
	//Module3_Word:ARRAY [1..16] OF UINT;	
END_STRUCT
END_TYPE

// ---- DUTs/ECC/EDWARDS/TMP_IN.TcDUT
TYPE TMP_IN :
STRUCT
	Rotation	:	BIT	;	//1:ROTATING,0:NOT ROTATING
	Normal	:	BIT	;	//1:NORMAL,0:UNNORMAL
	Acceleration	:	BIT	;	
	Deceleration_Includes_Braking	:	BIT	;	
	Remote_Local	:	BIT	;	//1:LOCAL.E-CAT CONTROL DISABLED,0:REMOTE.E-CAT CONTROL ENABLED
	Turbo_Low_Speed	:	BIT	;	
	Alarm	:	BIT	;	
	Warning	:	BIT	;	
	Turbo_Speed	:	INT	;	//0.1[%],1000(100.0%):RATED SPEED,0(0.0%):NO RATATION
	Turbo_Current	:	INT	;	//0.1A
	Turbo_pump_temperature	:	INT	;	//1[℃]
	VibrationH	:	INT	;	
	VibrationB	:	INT	;	
	VibrationZ	:	INT	;	
END_STRUCT
END_TYPE

// ---- DUTs/ECC/EDWARDS/TMP_OUT.TcDUT
TYPE TMP_OUT :
STRUCT
	Turbo_Start_Stop	:	BIT	;	//	1:START,0:STOP
	Turbo_Reset_Alarm	:	BIT	;	//	1:RESET ALARM,0:NO ACTION
	Turbo_Low_Speed		:	BIT	;	//	1:LOW SPEED MODE ON,0:OFF
END_STRUCT
END_TYPE

// ---- DUTs/ECC/HEATER/Mini8_16DI16DO/STR_Mini8_16DI16DO_In.TcDUT
TYPE STR_Mini8_16DI16DO_In :
STRUCT
	SYS_Input	:ARRAY[1..16] OF STR_HEATER_LINE_SYS_IN;
	CUS_Input	:ARRAY[1..16] OF STR_HEATER_LINE_CUS_IN;
END_STRUCT
END_TYPE

// ---- DUTs/ECC/HEATER/Mini8_16DI16DO/STR_Mini8_16DI16DO_Out.TcDUT
TYPE STR_Mini8_16DI16DO_Out :
STRUCT
	SYS_Output	:ARRAY[1..16] OF STR_HEATER_LINE_SYS_OUT;
	CUS_Output	:ARRAY[1..16] OF STR_HEATER_LINE_CUS_OUT;
END_STRUCT
END_TYPE

// ---- DUTs/ECC/HEATER/Mini8_8DI8DO/STR_Mini8_8DI8DO_In.TcDUT
TYPE STR_Mini8_8DI8DO_In :
STRUCT
	SYS_Input	:ARRAY[1..8] OF STR_HEATER_LINE_SYS_IN;
	CUS_Input	:ARRAY[1..8] OF STR_HEATER_LINE_CUS_IN;
END_STRUCT
END_TYPE

// ---- DUTs/ECC/HEATER/Mini8_8DI8DO/STR_Mini8_8DI8DO_Out.TcDUT
TYPE STR_Mini8_8DI8DO_Out :
STRUCT
	SYS_Output	:ARRAY[1..8] OF STR_HEATER_LINE_SYS_OUT;
	CUS_Output	:ARRAY[1..8] OF STR_HEATER_LINE_CUS_OUT;
END_STRUCT
END_TYPE

// ---- DUTs/ECC/HEATER/Mini8_XML/STR_HEATER_LINE_CUS_IN.TcDUT
TYPE STR_HEATER_LINE_CUS_IN :
STRUCT
	SBrkAlarm_EN	:	USINT	;
	Temp_Hi_Alarm_Inhibit	:	USINT	;
	Inhibit_Buffer	:	REAL	;
	RateUp	:	REAL	;
	RateDown	:	REAL	;
	PID_P	:	REAL	;
	PID_I	:	REAL	;
	PID_D	:	REAL	;
	AutotuneActivate	:	USINT	;
	Autotune_Status	:	USINT	;
	Autotune_PID_P:REAL;
	Autotune_PID_I:REAL;
	Autotune_PID_D:REAL;
END_STRUCT
END_TYPE

// ---- DUTs/ECC/HEATER/Mini8_XML/STR_HEATER_LINE_CUS_OUT.TcDUT
TYPE STR_HEATER_LINE_CUS_OUT :
STRUCT
	SBrkAlarm_EN	:	USINT	;
	Temp_Hi_Alarm_Inhibit	:	USINT	;
	Inhibit_Buffer	:	REAL	;
	RateUp	:	REAL	;
	RateDown	:	REAL	;
	PID_P	:	REAL	;
	PID_I	:	REAL	;
	PID_D	:	REAL	;
	AutotuneActivate	:	USINT	;
	Autotune_PID_Sel:USINT;
END_STRUCT
END_TYPE

// ---- DUTs/ECC/HEATER/Mini8_XML/STR_HEATER_LINE_SYS_IN.TcDUT
TYPE STR_HEATER_LINE_SYS_IN :
STRUCT
	PV	:	REAL	;
	Temp_Hi_Alarm	:	UINT	;
	Working_Output	:	REAL	;
	Working_SP	:	REAL	;
	Inhibit_state	:	BIT	;
	TC_Error	:	BIT	;
	Auto_Manual	:	BIT	;
	

END_STRUCT
END_TYPE

// ---- DUTs/ECC/HEATER/Mini8_XML/STR_HEATER_LINE_SYS_OUT.TcDUT
TYPE STR_HEATER_LINE_SYS_OUT :
STRUCT
	SP	:	REAL	;
	Clear_Alarms	:	UINT	;
	Forced_MV	:	REAL	;
	Auto_Manual	:	BIT	;
	Inhibit	:	BIT	;
END_STRUCT
END_TYPE

// ---- DUTs/ECC/HEATER/STR_HEATER_FURNACE.TcDUT
TYPE STR_HEATER_FURNACE :
STRUCT
//INPUT
	Input_LOOP1_Process_Value	AT%I*	:	REAL	;
	Input_LOOP1_Alarm_Condition	AT%I*	:	UINT	;
	Input_LOOP1_Manipulated_Value_Control_Output	AT%I*	:	REAL	;
	Input_LOOP1_Controlling_Set_Point	AT%I*	:	REAL	;
	Input_LOOP1_Actual_Control_State	AT%I*	:	BOOL	;
	Input_LOOP1_Sensor_Error	AT%I*	:	BOOL	;
	Input_LOOP1_Actual_Control_Loop_Mode	AT%I*	:	BOOL	;
	Input_LOOP2_Process_Value	AT%I*	:	REAL	;
	Input_LOOP2_Alarm_Condition	AT%I*	:	UINT	;
	Input_LOOP2_Manipulated_Value_Control_Output	AT%I*	:	REAL	;
	Input_LOOP2_Controlling_Set_Point	AT%I*	:	REAL	;
	Input_LOOP2_Actual_Control_State	AT%I*	:	BOOL	;
	Input_LOOP2_Sensor_Error	AT%I*	:	BOOL	;
	Input_LOOP2_Actual_Control_Loop_Mode	AT%I*	:	BOOL	;
	Input_LOOP3_Process_Value	AT%I*	:	REAL	;
	Input_LOOP3_Alarm_Condition	AT%I*	:	UINT	;
	Input_LOOP3_Manipulated_Value_Control_Output	AT%I*	:	REAL	;
	Input_LOOP3_Controlling_Set_Point	AT%I*	:	REAL	;
	Input_LOOP3_Actual_Control_State	AT%I*	:	BOOL	;
	Input_LOOP3_Sensor_Error	AT%I*	:	BOOL	;
	Input_LOOP3_Actual_Control_Loop_Mode	AT%I*	:	BOOL	;
	Input_LOOP4_Process_Value	AT%I*	:	REAL	;
	Input_LOOP4_Alarm_Condition	AT%I*	:	UINT	;
	Input_LOOP4_Manipulated_Value_Control_Output	AT%I*	:	REAL	;
	Input_LOOP4_Controlling_Set_Point	AT%I*	:	REAL	;
	Input_LOOP4_Actual_Control_State	AT%I*	:	BOOL	;
	Input_LOOP4_Sensor_Error	AT%I*	:	BOOL	;
	Input_LOOP4_Actual_Control_Loop_Mode	AT%I*	:	BOOL	;
	Input_LOOP5_Process_Value	AT%I*	:	REAL	;
	Input_LOOP5_Alarm_Condition	AT%I*	:	UINT	;
	Input_LOOP5_Manipulated_Value_Control_Output	AT%I*	:	REAL	;
	Input_LOOP5_Controlling_Set_Point	AT%I*	:	REAL	;
	Input_LOOP5_Actual_Control_State	AT%I*	:	BOOL	;
	Input_LOOP5_Sensor_Error	AT%I*	:	BOOL	;
	Input_LOOP5_Actual_Control_Loop_Mode	AT%I*	:	BOOL	;
	Input_LOOP6_Process_Value	AT%I*	:	REAL	;
	Input_LOOP6_Alarm_Condition	AT%I*	:	UINT	;
	Input_LOOP6_Manipulated_Value_Control_Output	AT%I*	:	REAL	;
	Input_LOOP6_Controlling_Set_Point	AT%I*	:	REAL	;
	Input_LOOP6_Actual_Control_State	AT%I*	:	BOOL	;
	Input_LOOP6_Sensor_Error	AT%I*	:	BOOL	;
	Input_LOOP6_Actual_Control_Loop_Mode	AT%I*	:	BOOL	;
	Input_LOOP7_Process_Value	AT%I*	:	REAL	;
	Input_LOOP7_Alarm_Condition	AT%I*	:	UINT	;
	Input_LOOP7_Manipulated_Value_Control_Output	AT%I*	:	REAL	;
	Input_LOOP7_Controlling_Set_Point	AT%I*	:	REAL	;
	Input_LOOP7_Actual_Control_State	AT%I*	:	BOOL	;
	Input_LOOP7_Sensor_Error	AT%I*	:	BOOL	;
	Input_LOOP7_Actual_Control_Loop_Mode	AT%I*	:	BOOL	;
	Input_LOOP8_Process_Value	AT%I*	:	REAL	;
	Input_LOOP8_Alarm_Condition	AT%I*	:	UINT	;
	Input_LOOP8_Manipulated_Value_Control_Output	AT%I*	:	REAL	;
	Input_LOOP8_Controlling_Set_Point	AT%I*	:	REAL	;
	Input_LOOP8_Actual_Control_State	AT%I*	:	BOOL	;
	Input_LOOP8_Sensor_Error	AT%I*	:	BOOL	;
	Input_LOOP8_Actual_Control_Loop_Mode	AT%I*	:	BOOL	;
	Input_IO_Mod_1_PV	AT%I*	:	REAL	;
	Input_IO_Mod_2_PV	AT%I*	:	REAL	;
	Input_IO_Mod_3_PV	AT%I*	:	REAL	;
	Input_IO_Mod_4_PV	AT%I*	:	REAL	;
	Input_IO_Mod_5_PV	AT%I*	:	REAL	;
	Input_IO_Mod_6_PV	AT%I*	:	REAL	;
	Input_IO_Mod_7_PV	AT%I*	:	REAL	;
	Input_IO_Mod_9_PV	AT%I*	:	REAL	;
	Input_IO_Mod_10_PV	AT%I*	:	REAL	;
	Input_IO_Mod_11_PV	AT%I*	:	REAL	;
	Input_IO_Mod_12_PV	AT%I*	:	REAL	;
	Input_IO_Mod_13_PV	AT%I*	:	REAL	;
	Input_IO_Mod_14_PV	AT%I*	:	REAL	;
	Input_IO_Mod_15_PV	AT%I*	:	REAL	;
	Input_IO_Mod_18_PV	AT%I*	:	REAL	;
	Input_IO_Mod_19_PV	AT%I*	:	REAL	;
	Input_IO_Mod_20_PV	AT%I*	:	REAL	;
	Input_IO_Mod_21_PV	AT%I*	:	REAL	;
	Input_IO_Mod_22_PV	AT%I*	:	REAL	;
	Input_IO_Mod_23_PV	AT%I*	:	REAL	;
	Input_IO_Mod_1_SBrkOut	AT%I*	:	USINT	;
	Input_IO_Mod_2_SBrkOut	AT%I*	:	USINT	;
	Input_IO_Mod_3_SBrkOut	AT%I*	:	USINT	;
	Input_IO_Mod_4_SBrkOut	AT%I*	:	USINT	;
	Input_IO_Mod_5_SBrkOut	AT%I*	:	USINT	;
	Input_IO_Mod_6_SBrkOut	AT%I*	:	USINT	;
	Input_IO_Mod_7_SBrkOut	AT%I*	:	USINT	;
	Input_IO_Mod_9_SBrkOut	AT%I*	:	USINT	;
	Input_IO_Mod_10_SBrkOut	AT%I*	:	USINT	;
	Input_IO_Mod_11_SBrkOut	AT%I*	:	USINT	;
	Input_IO_Mod_12_SBrkOut	AT%I*	:	USINT	;
	Input_IO_Mod_13_SBrkOut	AT%I*	:	USINT	;
	Input_IO_Mod_14_SBrkOut	AT%I*	:	USINT	;
	Input_IO_Mod_15_SBrkOut	AT%I*	:	USINT	;
	Input_IO_Mod_18_SBrkOut	AT%I*	:	USINT	;
	Input_IO_Mod_19_SBrkOut	AT%I*	:	USINT	;
	Input_IO_Mod_20_SBrkOut	AT%I*	:	USINT	;
	Input_IO_Mod_21_SBrkOut	AT%I*	:	USINT	;
	Input_IO_Mod_22_SBrkOut	AT%I*	:	USINT	;
	Input_IO_Mod_23_SBrkOut	AT%I*	:	USINT	;
	Input_Math2_8_In2	AT%I*	:	REAL	;
	Input_Math2_12_In2	AT%I*	:	REAL	;
	Input_Math2_16_In2	AT%I*	:	REAL	;
	Input_Math2_20_In2	AT%I*	:	REAL	;
	Input_Math2_24_In2	AT%I*	:	REAL	;
	Input_Math2_28_In2	AT%I*	:	REAL	;
	Input_Loop_7_Setpoint	AT%I*	:	REAL	;
	Input_Loop_7_Setpoint_SPRateUp	AT%I*	:	REAL	;
	Input_Loop_7_Setpoint_SPRateDown	AT%I*	:	REAL	;
	Input_Loop_7_PID_Ch1PropBand	AT%I*	:	REAL	;
	Input_Loop_7_PID_IntegralTime	AT%I*	:	REAL	;
	Input_Loop_7_PID_DerivativeTime	AT%I*	:	REAL	;
	Input_Loop_1_Main_CascadeMode	AT%I*	:	USINT	;
	Input_Loop_1_Setpoint	AT%I*	:	REAL	;
	Input_Loop_1_Setpoint_SPRateUp	AT%I*	:	REAL	;
	Input_Loop_1_Setpoint_SPRateDown	AT%I*	:	REAL	;
	Input_Loop_1_Cascade_SecondaryLocalSP	AT%I*	:	REAL	;
	Input_Loop_1_Main_TC_Select	AT%I*	:	USINT	;
	Input_Loop_1_PrimaryPID_PrimaryPropBand	AT%I*	:	REAL	;
	Input_Loop_1_PrimaryPID_PrimaryIntegralTime	AT%I*	:	REAL	;
	Input_Loop_1_PrimaryPID_PrimaryDerivativeTime	AT%I*	:	REAL	;
	Input_Loop_1_PID_Ch1PropBand	AT%I*	:	REAL	;
	Input_Loop_1_PID_IntegralTime	AT%I*	:	REAL	;
	Input_Loop_1_PID_DerivativeTime	AT%I*	:	REAL	;
	Input_Loop_2_Main_CascadeMode	AT%I*	:	USINT	;
	Input_Loop_2_Setpoint	AT%I*	:	REAL	;
	Input_Loop_2_Setpoint_SPRateUp	AT%I*	:	REAL	;
	Input_Loop_2_Setpoint_SPRateDown	AT%I*	:	REAL	;
	Input_Loop_2_Cascade_SecondaryLocalSP	AT%I*	:	REAL	;
	Input_Loop_2_Main_TC_Select	AT%I*	:	USINT	;
	Input_Loop_2_PrimaryPID_PrimaryPropBand	AT%I*	:	REAL	;
	Input_Loop_2_PrimaryPID_PrimaryIntegralTime	AT%I*	:	REAL	;
	Input_Loop_2_PrimaryPID_PrimaryDerivativeTime	AT%I*	:	REAL	;
	Input_Loop_2_PID_Ch1PropBand	AT%I*	:	REAL	;
	Input_Loop_2_PID_IntegralTime	AT%I*	:	REAL	;
	Input_Loop_2_PID_DerivativeTime	AT%I*	:	REAL	;
	Input_Loop_3_Main_CascadeMode	AT%I*	:	USINT	;
	Input_Loop_3_Setpoint	AT%I*	:	REAL	;
	Input_Loop_3_Setpoint_SPRateUp	AT%I*	:	REAL	;
	Input_Loop_3_Setpoint_SPRateDown	AT%I*	:	REAL	;
	Input_Loop_3_Cascade_SecondaryLocalSP	AT%I*	:	REAL	;
	Input_Loop_3_Main_TC_Select	AT%I*	:	USINT	;
	Input_Loop_3_PrimaryPID_PrimaryPropBand	AT%I*	:	REAL	;
	Input_Loop_3_PrimaryPID_PrimaryIntegralTime	AT%I*	:	REAL	;
	Input_Loop_3_PrimaryPID_PrimaryDerivativeTime	AT%I*	:	REAL	;
	Input_Loop_3_PID_Ch1PropBand	AT%I*	:	REAL	;
	Input_Loop_3_PID_IntegralTime	AT%I*	:	REAL	;
	Input_Loop_3_PID_DerivativeTime	AT%I*	:	REAL	;
	Input_Loop_4_Main_CascadeMode	AT%I*	:	USINT	;
	Input_Loop_4_Setpoint	AT%I*	:	REAL	;
	Input_Loop_4_Setpoint_SPRateUp	AT%I*	:	REAL	;
	Input_Loop_4_Setpoint_SPRateDown	AT%I*	:	REAL	;
	Input_Loop_4_Cascade_SecondaryLocalSP	AT%I*	:	REAL	;
	Input_Loop_4_Main_TC_Select	AT%I*	:	USINT	;
	Input_Loop_4_PrimaryPID_PrimaryPropBand	AT%I*	:	REAL	;
	Input_Loop_4_PrimaryPID_PrimaryIntegralTime	AT%I*	:	REAL	;
	Input_Loop_4_PrimaryPID_PrimaryDerivativeTime	AT%I*	:	REAL	;
	Input_Loop_4_PID_Ch1PropBand	AT%I*	:	REAL	;
	Input_Loop_4_PID_IntegralTime	AT%I*	:	REAL	;
	Input_Loop_4_PID_DerivativeTime	AT%I*	:	REAL	;
	Input_Loop_5_Main_CascadeMode	AT%I*	:	USINT	;
	Input_Loop_5_Setpoint	AT%I*	:	REAL	;
	Input_Loop_5_Setpoint_SPRateUp	AT%I*	:	REAL	;
	Input_Loop_5_Setpoint_SPRateDown	AT%I*	:	REAL	;
	Input_Loop_5_Cascade_SecondaryLocalSP	AT%I*	:	REAL	;
	Input_Loop_5_Main_TC_Select	AT%I*	:	USINT	;
	Input_Loop_5_PrimaryPID_PrimaryPropBand	AT%I*	:	REAL	;
	Input_Loop_5_PrimaryPID_PrimaryIntegralTime	AT%I*	:	REAL	;
	Input_Loop_5_PrimaryPID_PrimaryDerivativeTime	AT%I*	:	REAL	;
	Input_Loop_5_PID_Ch1PropBand	AT%I*	:	REAL	;
	Input_Loop_5_PID_IntegralTime	AT%I*	:	REAL	;
	Input_Loop_5_PID_DerivativeTime	AT%I*	:	REAL	;
	Input_Loop_6_Main_CascadeMode	AT%I*	:	USINT	;
	Input_Loop_6_Setpoint	AT%I*	:	REAL	;
	Input_Loop_6_Setpoint_SPRateUp	AT%I*	:	REAL	;
	Input_Loop_6_Setpoint_SPRateDown	AT%I*	:	REAL	;
	Input_Loop_6_Cascade_SecondaryLocalSP	AT%I*	:	REAL	;
	Input_Loop_6_Main_TC_Select	AT%I*	:	USINT	;
	Input_Loop_6_PrimaryPID_PrimaryPropBand	AT%I*	:	REAL	;
	Input_Loop_6_PrimaryPID_PrimaryIntegralTime	AT%I*	:	REAL	;
	Input_Loop_6_PrimaryPID_PrimaryDerivativeTime	AT%I*	:	REAL	;
	Input_Loop_6_PID_Ch1PropBand	AT%I*	:	REAL	;
	Input_Loop_6_PID_IntegralTime	AT%I*	:	REAL	;
	Input_Loop_6_PID_DerivativeTime	AT%I*	:	REAL	;
	Input_Instrument_Diagnostics_ForceStandby	AT%I*	:	USINT	;
	
//OUTPUT
	Output_LOOP1_Target_Set_Point	AT%Q*	:	REAL	;
	Output_LOOP1_Clear_Alarms	AT%Q*	:	UINT	;
	Output_LOOP1_Forced_MV	AT%Q*	:	REAL	;
	Output_LOOP1_Control_Mode	AT%Q*	:	BOOL	;
	Output_LOOP1_Control_State	AT%Q*	:	BOOL	;
	Output_LOOP2_Target_Set_Point	AT%Q*	:	REAL	;
	Output_LOOP2_Clear_Alarms	AT%Q*	:	UINT	;
	Output_LOOP2_Forced_MV	AT%Q*	:	REAL	;
	Output_LOOP2_Control_Mode	AT%Q*	:	BOOL	;
	Output_LOOP2_Control_State	AT%Q*	:	BOOL	;
	Output_LOOP3_Target_Set_Point	AT%Q*	:	REAL	;
	Output_LOOP3_Clear_Alarms	AT%Q*	:	UINT	;
	Output_LOOP3_Forced_MV	AT%Q*	:	REAL	;
	Output_LOOP3_Control_Mode	AT%Q*	:	BOOL	;
	Output_LOOP3_Control_State	AT%Q*	:	BOOL	;
	Output_LOOP4_Target_Set_Point	AT%Q*	:	REAL	;
	Output_LOOP4_Clear_Alarms	AT%Q*	:	UINT	;
	Output_LOOP4_Forced_MV	AT%Q*	:	REAL	;
	Output_LOOP4_Control_Mode	AT%Q*	:	BOOL	;
	Output_LOOP4_Control_State	AT%Q*	:	BOOL	;
	Output_LOOP5_Target_Set_Point	AT%Q*	:	REAL	;
	Output_LOOP5_Clear_Alarms	AT%Q*	:	UINT	;
	Output_LOOP5_Forced_MV	AT%Q*	:	REAL	;
	Output_LOOP5_Control_Mode	AT%Q*	:	BOOL	;
	Output_LOOP5_Control_State	AT%Q*	:	BOOL	;
	Output_LOOP6_Target_Set_Point	AT%Q*	:	REAL	;
	Output_LOOP6_Clear_Alarms	AT%Q*	:	UINT	;
	Output_LOOP6_Forced_MV	AT%Q*	:	REAL	;
	Output_LOOP6_Control_Mode	AT%Q*	:	BOOL	;
	Output_LOOP6_Control_State	AT%Q*	:	BOOL	;
	Output_LOOP7_Target_Set_Point	AT%Q*	:	REAL	;
	Output_LOOP7_Clear_Alarms	AT%Q*	:	UINT	;
	Output_LOOP7_Forced_MV	AT%Q*	:	REAL	;
	Output_LOOP7_Control_Mode	AT%Q*	:	BOOL	;
	Output_LOOP7_Control_State	AT%Q*	:	BOOL	;
	Output_LOOP8_Target_Set_Point	AT%Q*	:	REAL	;
	Output_LOOP8_Clear_Alarms	AT%Q*	:	UINT	;
	Output_LOOP8_Forced_MV	AT%Q*	:	REAL	;
	Output_LOOP8_Control_Mode	AT%Q*	:	BOOL	;
	Output_LOOP8_Control_State	AT%Q*	:	BOOL	;
	Output_Math2_8_In2	AT%Q*	:	REAL	;
	Output_Math2_12_In2	AT%Q*	:	REAL	;
	Output_Math2_16_In2	AT%Q*	:	REAL	;
	Output_Math2_20_In2	AT%Q*	:	REAL	;
	Output_Math2_24_In2	AT%Q*	:	REAL	;
	Output_Math2_28_In2	AT%Q*	:	REAL	;
	Output_Loop_7_Setpoint_SPRateUp	AT%Q*	:	REAL	;
	Output_Loop_7_Setpoint_SPRateDown	AT%Q*	:	REAL	;
	Output_Loop_7_PID_Ch1PropBand	AT%Q*	:	REAL	;
	Output_Loop_7_PID_IntegralTime	AT%Q*	:	REAL	;
	Output_Loop_7_PID_DerivativeTime	AT%Q*	:	REAL	;
	Output_Loop_1_Main_CascadeMode	AT%Q*	:	USINT	;
	Output_Loop_1_Setpoint_SPRateUp	AT%Q*	:	REAL	;
	Output_Loop_1_Setpoint_SPRateDown	AT%Q*	:	REAL	;
	Output_Loop_1_Cascade_SecondaryLocalSP	AT%Q*	:	REAL	;
	Output_Loop_1_Main_TC_Select	AT%Q*	:	USINT	;
	Output_Loop_1_PrimaryPID_PrimaryPropBand	AT%Q*	:	REAL	;
	Output_Loop_1_PrimaryPID_PrimaryIntegralTime	AT%Q*	:	REAL	;
	Output_Loop_1_PrimaryPID_PrimaryDerivativeTime	AT%Q*	:	REAL	;
	Output_Loop_1_PID_Ch1PropBand	AT%Q*	:	REAL	;
	Output_Loop_1_PID_IntegralTime	AT%Q*	:	REAL	;
	Output_Loop_1_PID_DerivativeTime	AT%Q*	:	REAL	;
	Output_Loop_2_Main_CascadeMode	AT%Q*	:	USINT	;
	Output_Loop_2_Setpoint_SPRateUp	AT%Q*	:	REAL	;
	Output_Loop_2_Setpoint_SPRateDown	AT%Q*	:	REAL	;
	Output_Loop_2_Cascade_SecondaryLocalSP	AT%Q*	:	REAL	;
	Output_Loop_2_Main_TC_Select	AT%Q*	:	USINT	;
	Output_Loop_2_PrimaryPID_PrimaryPropBand	AT%Q*	:	REAL	;
	Output_Loop_2_PrimaryPID_PrimaryIntegralTime	AT%Q*	:	REAL	;
	Output_Loop_2_PrimaryPID_PrimaryDerivativeTime	AT%Q*	:	REAL	;
	Output_Loop_2_PID_Ch1PropBand	AT%Q*	:	REAL	;
	Output_Loop_2_PID_IntegralTime	AT%Q*	:	REAL	;
	Output_Loop_2_PID_DerivativeTime	AT%Q*	:	REAL	;
	Output_Loop_3_Main_CascadeMode	AT%Q*	:	USINT	;
	Output_Loop_3_Setpoint_SPRateUp	AT%Q*	:	REAL	;
	Output_Loop_3_Setpoint_SPRateDown	AT%Q*	:	REAL	;
	Output_Loop_3_Cascade_SecondaryLocalSP	AT%Q*	:	REAL	;
	Output_Loop_3_Main_TC_Select	AT%Q*	:	USINT	;
	Output_Loop_3_PrimaryPID_PrimaryPropBand	AT%Q*	:	REAL	;
	Output_Loop_3_PrimaryPID_PrimaryIntegralTime	AT%Q*	:	REAL	;
	Output_Loop_3_PrimaryPID_PrimaryDerivativeTime	AT%Q*	:	REAL	;
	Output_Loop_3_PID_Ch1PropBand	AT%Q*	:	REAL	;
	Output_Loop_3_PID_IntegralTime	AT%Q*	:	REAL	;
	Output_Loop_3_PID_DerivativeTime	AT%Q*	:	REAL	;
	Output_Loop_4_Main_CascadeMode	AT%Q*	:	USINT	;
	Output_Loop_4_Setpoint_SPRateUp	AT%Q*	:	REAL	;
	Output_Loop_4_Setpoint_SPRateDown	AT%Q*	:	REAL	;
	Output_Loop_4_Cascade_SecondaryLocalSP	AT%Q*	:	REAL	;
	Output_Loop_4_Main_TC_Select	AT%Q*	:	USINT	;
	Output_Loop_4_PrimaryPID_PrimaryPropBand	AT%Q*	:	REAL	;
	Output_Loop_4_PrimaryPID_PrimaryIntegralTime	AT%Q*	:	REAL	;
	Output_Loop_4_PrimaryPID_PrimaryDerivativeTime	AT%Q*	:	REAL	;
	Output_Loop_4_PID_Ch1PropBand	AT%Q*	:	REAL	;
	Output_Loop_4_PID_IntegralTime	AT%Q*	:	REAL	;
	Output_Loop_4_PID_DerivativeTime	AT%Q*	:	REAL	;
	Output_Loop_5_Main_CascadeMode	AT%Q*	:	USINT	;
	Output_Loop_5_Setpoint_SPRateUp	AT%Q*	:	REAL	;
	Output_Loop_5_Setpoint_SPRateDown	AT%Q*	:	REAL	;
	Output_Loop_5_Cascade_SecondaryLocalSP	AT%Q*	:	REAL	;
	Output_Loop_5_Main_TC_Select	AT%Q*	:	USINT	;
	Output_Loop_5_PrimaryPID_PrimaryPropBand	AT%Q*	:	REAL	;
	Output_Loop_5_PrimaryPID_PrimaryIntegralTime	AT%Q*	:	REAL	;
	Output_Loop_5_PrimaryPID_PrimaryDerivativeTime	AT%Q*	:	REAL	;
	Output_Loop_5_PID_Ch1PropBand	AT%Q*	:	REAL	;
	Output_Loop_5_PID_IntegralTime	AT%Q*	:	REAL	;
	Output_Loop_5_PID_DerivativeTime	AT%Q*	:	REAL	;
	Output_Loop_6_Main_CascadeMode	AT%Q*	:	USINT	;
	Output_Loop_6_Setpoint_SPRateUp	AT%Q*	:	REAL	;
	Output_Loop_6_Setpoint_SPRateDown	AT%Q*	:	REAL	;
	Output_Loop_6_Cascade_SecondaryLocalSP	AT%Q*	:	REAL	;
	Output_Loop_6_Main_TC_Select	AT%Q*	:	USINT	;
	Output_Loop_6_PrimaryPID_PrimaryPropBand	AT%Q*	:	REAL	;
	Output_Loop_6_PrimaryPID_PrimaryIntegralTime	AT%Q*	:	REAL	;
	Output_Loop_6_PrimaryPID_PrimaryDerivativeTime	AT%Q*	:	REAL	;
	Output_Loop_6_PID_Ch1PropBand	AT%Q*	:	REAL	;
	Output_Loop_6_PID_IntegralTime	AT%Q*	:	REAL	;
	Output_Loop_6_PID_DerivativeTime	AT%Q*	:	REAL	;
	Output_Instrument_Diagnostics_ForceStandby	AT%Q*	:	USINT	;






END_STRUCT
END_TYPE

// ---- DUTs/ECC/HEATER/STR_HEATER_LINE.TcDUT
TYPE STR_HEATER_LINE :
STRUCT
	//INPUT
	Input_PV	AT%I*:	REAL	;
	Input_Temp_Hi_Alarm	AT%I*:	UINT	;
	Input_Working_Output	AT%I*:	REAL	;
	Input_Working_SP	AT%I*:	REAL	;
	Input_Inhibit_state	AT%I*:	BOOL	;
	Input_TC_Error	AT%I*:	BOOL	;
	Input_Auto_Manual	AT%I*:	BOOL	;
	Input_SBrkAlarm_EN	AT%I*:	USINT	;
	Input_Temp_Hi_Alarm_Inhibit	AT%I*:	USINT	;
	Input_Inhibit_Buffer	AT%I*:	REAL	;
	Input_RateUp	AT%I*:	REAL	;
	Input_RateDown	AT%I*:	REAL	;
	Input_AutotuneActivate	AT%I*:	USINT	;
	Input_Autotune_Status	AT%I*:	USINT	;
	Input_PID_P	AT%I*:	REAL	;
	Input_PID_I	AT%I*:	REAL	;
	Input_PID_D	AT%I*:	REAL	;
				
				
	//OUTPUT			
	Output_HEATER_SP	AT%Q*:	REAL	;
	Output_Clear_Alarms	AT%Q*:	UINT	;
	Output_Forced_MV	AT%Q*:	REAL	;
	Output_HEATER_Auto_Manual	AT%Q*:	BOOL 	;
	Output_HEATER_Inhibit	AT%Q*:	BOOL	;
	Output_HEATER_SBrkAlarm_EN	AT%Q*:	USINT	;
	Output_HEATER_Temp_Hi_Alarm_Inhibit	AT%Q*:	USINT	;
	Output_Inhibit_Buffer	AT%Q*:	REAL	;
	Output_HEATER_RateUp	AT%Q*:	REAL	;
	Output_HEATER_RateDown	AT%Q*:	REAL	;
	Output_HEATER_AutotuneActivate	AT%Q*:	USINT	;
	Output_HEATER_PID_P	AT%Q*:	REAL	;
	Output_HEATER_PID_I	AT%Q*:	REAL	;
	Output_HEATER_PID_D	AT%Q*:	REAL	;


END_STRUCT
END_TYPE

// ---- DUTs/ECC/IGS/IGS_IN.TcDUT
TYPE IGS_IN :
STRUCT
	//C32	EL3164	4AI	0-10V
	C32		:ARRAY [1..4] OF INT;
	
	
	//C33	EL3164	4AI	0-10V
	C33		:ARRAY [1..4] OF INT;
	
	
	//C34	EL3164	4AI	0-10V
	C34		:ARRAY [1..4] OF INT;
	
	
	//C35	EL3154	4AI	4-20mA
	C35		:ARRAY [1..4] OF INT;
	
	
	//C36	EL1889 16DI
	C36		:ARRAY [1..16] OF BOOL;
	
	
	
	//C37	EL1889 16DI
	C37		:ARRAY [1..16] OF BOOL;
	
	
	//C38	EL1904	4SDI
	C38		:ARRAY [1..4] OF BOOL;
	
	//C39	EL1904	4SDI
	C39		:ARRAY [1..4] OF BOOL;
	
	//C40	EL3318	8TC
	C40		:ARRAY [1..8] OF INT;
	
	//C41	EL9410	POWER MODULE
		
	
END_STRUCT
END_TYPE

// ---- DUTs/ECC/IGS/IGS_OUT.TcDUT
TYPE IGS_OUT :
STRUCT
	//C42	EL2889	16DO
	C42	 	:ARRAY [1..16] OF BOOL;
	
	//C43	EL2904	4SDO
	C43		:ARRAY [1..4] OF BOOL;
END_STRUCT
END_TYPE

// ---- DUTs/ECC/Meter/Meter_Data.TcDUT
TYPE Meter_Data :
STRUCT
	AlmEn_In_b			    :	BOOL;//使能
	OverRangeAlm_In_b	    :	BOOL;//超上限报警
	UnderRangeAlm_In_b	    :	BOOL;//超下限报警
	AlmRst_In_b			    :	BOOL;//报警复位
	AnalogRdValue_In_Int	:	INT;//实际通道值
	AnalogResMax_In_Int	    :	INT;//通道最大值
	AnalogResMin_In_Int   	:	INT;//通道最小值
	AnalogPhyMax_In_Real	:	REAL;//工程量最大值
	AnalogPhyMin_In_Real	:	REAL;//工程量最小值
    AlmDnLmtSV_In_Real	    :	REAL;//设定最小值
	AlmUpLmtSV_In_Real	    :	REAL;//设定最大值
	AnalogRdOffset_In_Real	:	REAL;//偏移值
	
	ActRdValue_Out_Real	        :	REAL;
	ActValueOutRangeAlm_Out_b	:	BOOL;
	ActValueStatusOK_Out_b	    :	BOOL;
END_STRUCT
END_TYPE

// ---- DUTs/ECC/MFC MFM/STR_FCSP700_INPUT.TcDUT
TYPE STR_FCSP700_INPUT :
STRUCT
	Active_Exception_Status	:	USINT	;
	Flow_Reading			:	REAL	;
	Pressure_Reading		:	REAL	;
	Temperature_Reading		:	REAL	;
	Position_Readback		:	REAL	;
	Position_Setpoint		:	REAL	;
	WcState					:	BIT		;
	InputToggle				:	BIT		;
	State					:	UINT	;
	//AdsAddr				:	AMSADDR	;
END_STRUCT
END_TYPE

// ---- DUTs/ECC/MFC MFM/STR_FCSP700_OUTPUT.TcDUT
TYPE STR_FCSP700_OUTPUT :
STRUCT
	Flow_SP					:	REAL	;
	Actuator_Control		:	USINT	;
	Actuator_Position_SP	:	REAL	;
	Ramp_Time				:	UDINT	;
END_STRUCT
END_TYPE

// ---- DUTs/ECC/MFC MFM/STR_SEC_N107.TcDUT
TYPE STR_SEC_N107 :
STRUCT
	Output0_Flow_SP_7003_01					:	REAL	;
	Output0_Actuator_Control_7009_01		:	USINT	;
	Output0_Actuator_Position_SP_7009_02	:	REAL	;
	Output0_Ramp_Time_7008_01				:	UDINT	;
	Input0_Active_Exception_Status_F380_00	:	USINT	;
	Input0_Flow_Reading_6000_01				:	REAL	;
	Input0_Position_Setpoint_6009_01		:	REAL	;
END_STRUCT
END_TYPE

// ---- DUTs/ECC/MFC MFM/STR_SEC_Z507.TcDUT
TYPE STR_SEC_Z507 :
STRUCT
	Output0_Flow_SP_7003_01					:	REAL	;
	Output0_Actuator_Control_7009_01		:	USINT	;
	Output0_Actuator_Position_SP_7009_02	:	REAL	;
	Output0_Ramp_Time_7008_01				:	UDINT	;
	Input0_Active_Exception_Status_F380_00	:	USINT	;
	Input0_Flow_Reading_6000_01				:	REAL	;
	Input0_Position_Setpoint_6009_01		:	REAL	;
END_STRUCT
END_TYPE

// ---- DUTs/ECC/MFC MFM/STR_SEF_N107.TcDUT
TYPE STR_SEF_N107 :
STRUCT
	Input0_Active_Exception_Status_F380_00		:	USINT	;
	Input0_Flow_Reading_6000_01					:	REAL	;
END_STRUCT
END_TYPE

// ---- DUTs/ECC/MFC MFM/STR_SEF_Z507.TcDUT
TYPE STR_SEF_Z507 :
STRUCT
	Input0_Active_Exception_Status_F380_00		:	USINT	;
	Input0_Flow_Reading_6000_01					:	REAL	;
END_STRUCT
END_TYPE

// ---- DUTs/ECC/VALVE/STR_EX260_SEC.TcDUT
TYPE STR_EX260_SEC :
STRUCT
	A:USINT;
	B:USINT;
	C:USINT;
	D:USINT;
	(*
	Out_Bit0	:	BOOL	;
	Out_Bit1	:	BOOL	;
	Out_Bit2	:	BOOL	;
	Out_Bit3	:	BOOL	;
	Out_Bit4	:	BOOL	;
	Out_Bit5	:	BOOL	;
	Out_Bit6	:	BOOL	;
	Out_Bit7	:	BOOL	;
	Out_Bit8	:	BOOL	;
	Out_Bit9	:	BOOL	;
	Out_Bit10	:	BOOL	;
	Out_Bit11	:	BOOL	;
	Out_Bit12	:	BOOL	;
	Out_Bit13	:	BOOL	;
	Out_Bit14	:	BOOL	;
	Out_Bit15	:	BOOL	;
	Out_Bit16	:	BOOL	;
	Out_Bit17	:	BOOL	;
	Out_Bit18	:	BOOL	;
	Out_Bit19	:	BOOL	;
	Out_Bit20	:	BOOL	;
	Out_Bit21	:	BOOL	;
	Out_Bit22	:	BOOL	;
	Out_Bit23	:	BOOL	;
	Out_Bit24	:	BOOL	;
	Out_Bit25	:	BOOL	;
	Out_Bit26	:	BOOL	;
	Out_Bit27	:	BOOL	;
	Out_Bit28	:	BOOL	;
	Out_Bit29	:	BOOL	;
	Out_Bit30	:	BOOL	;
	Out_Bit31	:	BOOL	;
	*)

END_STRUCT
END_TYPE

// ---- DUTs/ECC/VALVE/STR_USINT_BOOL.TcDUT
TYPE STR_USINT_BOOL :
UNION
	T_USINT:USINT;
	T_BOOL:ARRAY [1..8] OF BOOL;
END_UNION
END_TYPE

// ---- DUTs/ECC/VG/STR_BPG400.TcDUT
TYPE STR_BPG400 :
STRUCT
	Combination_Gauge_Reading_Valid_Module_1		:	BIT	;
	Combination_Gauge_Overrange_Exceeded_Module_1	:	BIT	;
	Combination_Gauge_Underrange_Exceeded_Module_1	:	BIT	;
	Combination_Gauge_Active_Value_Module_1			:	REAL	;
	Combination_Gauge_Active_Sensor_Number_Module_1	:	UINT	;
	Combination_Gauge_Reading_Valid_Module_2		:	BIT	;
	Combination_Gauge_Overrange_Exceeded_Module_2	:	BIT	;
	Combination_Gauge_Underrange_Exceeded_Module_2	:	BIT	;
	Combination_Gauge_Active_Value_Module_2			:	REAL	;
	Combination_Gauge_Active_Sensor_Number_Module_2	:	UINT	;
	Active_Exception_Status							:	USINT	;
	Trip_Point_Output_All_Instance					:	UDINT	;
	WcState											:	BIT	;
	InputToggle										:	BIT	;
	State											:	UINT	;
	//AdsAddr										:	AMSADDR	;

END_STRUCT
END_TYPE

// ---- DUTs/ECC/VG/STR_CDG200D.TcDUT
TYPE STR_CDG200D :
STRUCT
	Reading_Valid1					:BOOL;
	Overrange_Exceeded1				:BOOL;
	Underrange_Exceeded1			:BOOL;
	Sensor_Value1					:REAL;
	Reading_Valid2					:BOOL;
	Overrange_Exceeded2				:BOOL;
	Underrange_Exceeded2			:BOOL;
	Sensor_Value2					:REAL;
	Active_Exception_Status			:USINT;
	Trip_Point_Output_All_Insta		:UDINT;
END_STRUCT
END_TYPE

// ---- DUTs/ECC/VG/VG_Data.TcDUT
TYPE VG_Data :
STRUCT
	I_Pressure:REAL;
END_STRUCT
END_TYPE

// ---- DUTs/ECC/VG/VG_INPUT.TcDUT
TYPE VG_INPUT :
STRUCT
		Reading_Valid:BOOL;
		Overrange_Exceeded:BOOL;
		Underrange_Exceeded:BOOL;
		Sensor_Value:REAL;
		Reading_Valid_1:BOOL;
		Overrange_Exceeded_1:BOOL;
		Underrange_Exceeded_1:BOOL;
		Sensor_Value_1:REAL;
		Active_Exception_Status_2:USINT;
		Trip_Point_Output_All_Insta_2:UDINT;
		Active_Device_Warning_Details:UDINT;
		Active_Device_Error_Details:UDINT;
END_STRUCT
END_TYPE

// ---- DUTs/Info/Intelock.TcDUT
TYPE Intelock :
STRUCT	
	ForelinePressure:BOOL;
END_STRUCT
END_TYPE

// ---- DUTs/Info/ProcessRecipeFeedBack.TcDUT
TYPE ProcessRecipeFeedBack :
STRUCT
	//start process
	ProcessStart :BOOL;
	//finish process
	ProcessFinished :BOOL;
	//process error code
	ProcessError :INT;//0:	1:	2:
	//current step No
	CurrentStepNo :INT;
	CurrentStepstart :BOOL;
	CurrentStepFinished :BOOL;
END_STRUCT
END_TYPE

// ---- DUTs/IO/STR_AI.TcDUT
TYPE STR_AI :
STRUCT
VG101_Pressure	,
VG102_Pressure	,
VG103_Pressure	,
VG104_Pressure	,
BA1_Pressure	,
MFC1_Flow	,
MFC2_Flow	,
MFC3_Flow	,
MFC4_Flow	,
MFC5_Flow	,
MFC6_Flow	,
MFC7_Flow	,
CHILLER1_TEMP_PV	,
CHILLER1_DI_PV	,
CHILLER1_FLOW_PV	,
CHILLER1_PRESS_PV	,
CHILLER2_TEMP_PV	,
CHILLER2_DI_PV	,
CHILLER2_FLOW_PV	,
CHILLER2_PRESS_PV	,
Turbo_Pump_Temp	,
APC_Temp	,	//TC01
Gate_Valve_Temp	,		//TC13
Gate_Valve_Temp_Monitor,	//TC14
IGS_Temp1	,	//TC35
IGS_Temp2	,	//TC36
IGS_Temp3	,	//TC35
IGS_Temp4	,	//TC36
Lid_Temp	,	//TC02
Lid_Temp_Monitor1	,	//TC03
Lid_Temp_Monitor2	,	//TC04
Tape_Temp1	,	//TC31
Tape_Temp2	,	//TC32
Tape_Temp3	,	//TC32
AV102_Temp	,
AV101_Temp	,
AV106_Temp	,
BA01_Temp	,
VG103_Pipe_Temp	,
Exhaust1_6_Temp	,
Exhaust7_8_Temp	,
VG101_Pipe_Temp	,
Chamber_Temp1	,	//TC05
Chamber_Temp2	,	//TC06
Chamber_Temp3	,	//TC07
Chamber_Temp_Monitor,	//TC12
Stage_Temp1	,		//TC08
Stage_Temp2	,		//TC09
Stage_Temp3	,		//TC10
Stage_Temp4	:REAL;		//TC11	

PG_PS1_Value	,
PG_PS2_Value	,
PG_PS3_Value	,
PG_PS4_Value	,
PG_PS5_Value	,
PG_PS6_Value	,
PG_PS7_Value	,
PG_PS8_Value	,
PG_PS9_Value	,
PS1_Value	,
PS2_Value	,
MS1_Value	,
GD01_Value	,
GD02_Value	:REAL;

APC:VAT_IN;

TMP:TMP_IN;

VG103_PV	,//原PG10

VG101_PV	,//原PS10

VG102_PV	,//原PS11

BA1_PV	,

VG104_PV:REAL;//原PS12

END_STRUCT
END_TYPE

// ---- DUTs/IO/STR_AO.TcDUT
TYPE STR_AO :
STRUCT
MFC1_Flow_Setpoint	,
MFC1_Rate_Setpoint	,
MFC2_Flow_Setpoint	,
MFC2_Rate_Setpoint	,
MFC3_Flow_Setpoint	,
MFC3_Rate_Setpoint	,
MFC4_Flow_Setpoint	,
MFC4_Rate_Setpoint	,
MFC5_Flow_Setpoint	,
MFC5_Rate_Setpoint	,
MFC6_Flow_Setpoint	,
MFC6_Rate_Setpoint	,
MFC7_Flow_Setpoint	,
MFC7_Rate_Setpoint	,
LID_Temp_SV	,	//E02
//LID_Heater2_Temperature_Setpoint	,	//E03
//LID_Heater3_Temperature_Setpoint	,	//E04
//LID_Heater4_Temperature_Setpoint	,	//E05
Chamber_Temp1_SV	,//E06
Chamber_Temp2_SV	,//E07
Chamber_Temp3_SV	,//E08
(*Chamber_Heater4_Temperature_Setpoint	,//E09
Chamber_Heater5_Temperature_Setpoint	,//E10
Chamber_Heater6_Temperature_Setpoint	,//E11
Chamber_Heater7_Temperature_Setpoint	,//E12
Chamber_Heater8_Temperature_Setpoint	,//E13*)
AV102_Temp_SV	,//E14
AV101_Temp_SV	,//E15
AV106_Temp_SV	,//E16
BA01_Temp_SV	,//E17
VG103_Pipe_Temp_SV	,//E16
Exhaust1_6_Temp_SV	,//E14
Exhaust7_8_Temp_SV	,//E15
VG101_Pipe_Temp_SV	,//E16
(*Forline_Heater9_Temperature_Setpoint	,//E17
Forline_Heater10_Temperature_Setpoint	,//E14
Forline_Heater11_Temperature_Setpoint	,//E15
Forline_Heater12_Temperature_Setpoint	,//E16
Forline_Heater13_Temperature_Setpoint	,//E17
Forline_Heater14_Temperature_Setpoint	,//E14
Forline_Heater15_Temperature_Setpoint	,//E15
Forline_Heater16_Temperature_Setpoint	,//E16
Forline_Heater17_Temperature_Setpoint	,//E17
Forline_Heater18_Temperature_Setpoint	,//E14
Forline_Heater19_Temperature_Setpoint	,//E15
Forline_Heater20_Temperature_Setpoint	,//E16*)
Gate_Valve_Temp_SV	,//E18
APC_Temp_SV	,//E01
TMP_Temp_SV	,//不用
Tape_Temp1_SV	,
Tape_Temp2_SV	,
Tape_Temp3_SV	,
IGS_Temp1_SV	,
IGS_Temp2_SV	,
Chiller_Temp1_SV	,
Chiller_Temp2_SV	,
Stage_Temp1_SV	,
Stage_Temp2_SV	,
Chiller1_On	,
Chiller2_On:REAL;


APC:VAT_OUT;

TMP:TMP_OUT;
END_STRUCT
END_TYPE

// ---- DUTs/IO/STR_NDI.TcDUT
TYPE STR_NDI :
STRUCT
	Heartbeat	,	
	AV101_OPEN	,	
	AV101_CLOSE	,	
	AV102_OPEN	,	
	AV102_CLOSE	,	
	AV103_OPEN	,
	AV103_CLOSE	,
	AV104_OPEN	,
	AV104_CLOSE	,
	AV105_OPEN	,
	AV105_CLOSE	,
	AV106_OPEN	,
	AV106_CLOSE	,
	CY1_OPEN	,
	CY1_CLOSE	,
	CY2_OPEN	,
	CY2_CLOSE	,
	GV1_OPEN	,
	GV1_CLOSE	,
	Lid_Closed	,
	Water_Leak_Sensor01	,
	Water_Leak_Sensor02	,
	Water_Leak_Sensor03	,
	Water_Leak_Sensor04	,
	WAFER_CHECK_SENSOR1	,
	WAFER_CHECK_SENSOR2	,
	WAFER_CHECK_SENSOR3	,
	WAFER_CHECK_SENSOR4	,
	PS10_H_ALM	,	
	PS10_L_ALM	,
	PS11_H_ALM	,
	PS11_L_ALM	,
	PS12_H_ALM		,
	PS12_L_ALM	,
	LID_heater_OT	,
	Chamber_heater_OT	,
	Chiller_Controller_ALM	,
	PG_PS1_Pressure_Switch_Up_Limit	,
	PG_PS1_Pressure_Switch_Down_Limit	,
	PG_PS2_Pressure_Switch_Up_Limit	,
	PG_PS2_Pressure_Switch_Down_Limit	,
	PG_PS3_Pressure_Switch_Up_Limit	,
	PG_PS3_Pressure_Switch_Down_Limit	,
	PG_PS4_Pressure_Switch_Up_Limit	,
	PG_PS4_Pressure_Switch_Down_Limit	,
	PG_PS5_Pressure_Switch_Up_Limit	,
	PG_PS5_Pressure_Switch_Down_Limit	,
	PG_PS6_Pressure_Switch_Up_Limit	,
	PG_PS6_Pressure_Switch_Down_Limit	,
	PG_PS7_Pressure_Switch_Up_Limit	,
	PG_PS7_Pressure_Switch_Down_Limit	,
	PG_PS8_Pressure_Switch_Up_Limit	,
	PG_PS8_Pressure_Switch_Down_Limit	,
	PG_PS9_Pressure_Switch_Up_Limit	,
	PG_PS9_Pressure_Switch_Down_Limit	,
	MS1_Pressure_Switch_Up_Limit	,
	MS1_Pressure_Switch_Down_Limit	,
	PS1_Pressure_Switch	,
	PS2_Pressure_Switch	,
	HT001_OT	,
	HT002_OT	,
	HT003_OT	,
	HT004_OT	,
	HT005_OT	,
	HT006_OT	,
	Turbo_Pump_Heater_OT	,
	Pendulum_Valve_Heater_OT	,
	IGS_Heater_OT	,
	Tape_Heater_OT	,
	Foreline_Heater_OT	,
	Gate_Valve_OT	,
	Stage_Heater_OT	,
	CDA_OK	,
	Lift_Pin_Middle1	,
	Lift_Pin_Middle2	,
	FL01B2	,
	FL01B4	,
	FL02B2	,
	FL02B4	,
	FL03B2	,
	FL03B4	,
	FL04B2	,
	FL04B4	,
	DP01_OUTPUT1	,
	DP01_OUTPUT2	,
	MaualEndStepFeedBack	,
	AV1		,
	AV2		,
	AV3		,
	AV4		,
	AV6		,
	AV7		,
	AV9		,
	AV10	,
	AV11	,
	AV12	,
	AV13	,
	AV14	,
	AV16	,
	AV17	,
	AV19	,
	AV20	,
	AV22	,
	AV23	,
	AV25	,
	AV26	,
	AV27	,
	AV5		,
	AV8		,
	AV15	,
	AV18	,
	AV21	,
	AV24	:BOOL;
END_STRUCT
END_TYPE

// ---- DUTs/IO/STR_NDO.TcDUT
TYPE STR_NDO :
STRUCT
	Heartbeat	,
	(*
	TUBRO_PUMO_POWER_ON	,
	PENDULUM_VALVE_POWER_ON	,
	LID_HEATER_POWER_ON	,
	CHAMBER_POWER_ON	,
	IGS_HEATER_POWER_ON	,
	TAPE_HEATER_POWER_ON	,
	FORLINE_HEATER_POWER_ON	,
	GATE_VALVE_HEATER_POWER_ON	,
	EV3_POWER_ON	,
	EV4_POWER_ON	,
	EV1_POWER_ON	,
	EV2_POWER_ON	,
	DRY_PUMP_RUN	,
	*)
	AV101	,
	AV102	,
	AV103	,
	AV104	,
	AV105	,
	AV106	,
	AV107	,
	AV108	,
	AV109	,	//pin middle
	AV110	,	//pin up
	GV101C	,	//门阀打开
	GV101O	,	//门阀关闭
	AV201	,
	AV202	,
	AC101	,
	AC102	,
	AC103	,
	AC104	,
	AC105	,
	AC106	,
	AV1		,
	AV2		,
	AV3		,
	AV4		,
	AV6		,
	AV7		,
	AV9		,
	AV10	,
	AV11	,
	AV12	,
	AV13	,
	AV14	,
	AV16	,
	AV17	,
	AV19	,
	AV20	,
	AV22	,
	AV23	,
	AV25	,
	AV26	,
	AV27	,
	AV5		,
	AV8		,
	AV15	,
	AV18	,
	AV21	,
	AV24	,
	MaualEndStep	:BOOL;

END_STRUCT
END_TYPE

// ---- DUTs/Recipe/Lst.TcDUT
TYPE Lst :
STRUCT
	Pressure:LstPressure;
	GAS:LstGas;
	Heater:LstHeater;
END_STRUCT
END_TYPE

// ---- DUTs/Recipe/LST/LstBIASUnit.TcDUT
TYPE LstBIASUnit :
STRUCT
	BIAS_UnitName: STRING;
	BIAS_RFPower: INT;
	BIAS_TuneCapPreset: INT;
	BIAS_LoadCapPreset: INT;
	BIAS_AutoTuneCapPreset: INT;
	BIAS_AutoLoadCapPreset: INT;
	BIAS_MaxReflectedPower: INT;
	BIAS_GeneratorMode: STRING;
	BIAS_PulseRateFreq: INT;
	BIAS_PulseDutyCycle: INT;
	BIAS_EnableRamp: BOOL;
	BIAS_TargetMode: STRING;
	BIAS_TargetBiasRFPower: INT;
END_STRUCT
END_TYPE

// ---- DUTs/Recipe/LST/LstGas.TcDUT
TYPE LstGas :
STRUCT
	ToleranceMode:STRING;			//'Value' or 'Percent'
	ToleranceDelayTime:INT;	
	
	Gas1: INT;
	Gas1WarningRange:INT;
	Gas1AlarmRange:INT;
	
	Gas2: INT;
	Gas2WarningRange:INT;
	Gas2AlarmRange:INT;
	
	Gas3: INT;
	Gas3WarningRange:INT;
	Gas3AlarmRange:INT;
	
	Gas4: INT;
	Gas4WarningRange:INT;
	Gas4AlarmRange:INT;
	
	Gas5: INT;
	Gas5WarningRange:INT;
	Gas5AlarmRange:INT;
	
	Gas6: INT;
	Gas6WarningRange:INT;
	Gas6AlarmRange:INT;
	
	Gas7: INT;
	Gas7WarningRange:INT;
	Gas7AlarmRange:INT;
	
	Gas8: INT;
	Gas8WarningRange:INT;
	Gas8AlarmRange:INT;
	
	Gas9: INT;
	Gas9WarningRange:INT;
	Gas9AlarmRange:INT;
	
	
	(*GasEnableRamp: BOOL;
	Gas1Target: INT;
	Gas2Target: INT;
	Gas3Target: INT;
	Gas4Target: INT;
	Gas5Target: INT;
	Gas6Target: INT;
	Gas7Target: INT;
	Gas8Target: INT;
	//GasFlowRatie: INT;*)
END_STRUCT
END_TYPE

// ---- DUTs/Recipe/LST/LstHeater.TcDUT
TYPE LstHeater :
STRUCT
	ToleranceMode:STRING;		//'Value' or 'Percent'
	ToleranceDelayTime:INT;
	WallTemp:INT;
	WallTempWaningRange:INT;
	WallTempAlarmRange:INT;
	
	LidTemp:INT;
	LidTempWaningRange:INT;
	LidTempAlarmRange:INT;
	
	StageEdgeTemp: INT;
	StageEdgeTempWaningRange:INT;
	StageEdgeTempAlarmRange:INT;
	
	StageCenterTemp: INT;
	StageCenterTempWaningRange:INT;
	StageCenterTempAlarmRange:INT;
	
END_STRUCT
END_TYPE

// ---- DUTs/Recipe/LST/LstPressure.TcDUT
TYPE LstPressure :
STRUCT
    ToleranceMode:STRING;		//'Value' or 'Percent'
	ToleranceDelayTime:INT;
	PressureUnitMode:STRING;	//'Pressure' or 'Position'
	StartValue:INT;
	StartValueWarningRange:INT;
	StartValueAlarmRange:INT;
	ValvePositionPreset:INT;
	EnableRamp:BOOL;
	HoldTime:INT;
	RampTime:INT;
	TargetValue:INT;
END_STRUCT
END_TYPE

// ---- DUTs/Recipe/LST/LstTCPUnit.TcDUT
TYPE LstTCPUnit :
STRUCT
	TCP_UnitName: STRING;
	TCP_RFPower: INT;
	TCP_TuneCapPreset: INT;
	TCP_LoadCapPreset: INT;
	TCP_AutoTuneCapPreset: INT;
	TCP_AutoLoadCapPreset: INT;
	TCP_MaxReflectedPower: INT;
	TCP_EnableRamp: BOOL;
	TCP_TargetRFPower: INT;
END_STRUCT
END_TYPE

// ---- DUTs/Recipe/RecipeEachStep.TcDUT
TYPE RecipeEachStep :
STRUCT
	StepNo: INT;
    Completion:STRING;		//'Stable', 'Time' or 'End'
    StepTime:INT;
	AddTime:INT;
    CycleStart:BOOL;
    CycleEnd:BOOL;
    CycleNumber:INT;
	Lifter_Up:BOOL;
	AdjustTargetStepNo:INT;
	Lifter_Down:BOOL;
    LstUnit:LST;
END_STRUCT
END_TYPE

// ---- DUTs/Info/Alarm.TcDUT
TYPE Alarm :
STRUCT
	//PRESSURE_Warning:BOOL;
	PRESSURE:BOOL;
	
	//MFC1_Warning:BOOL;
	MFC1:BOOL;
	
	//MFC2_Warning:BOOL;
	MFC2:BOOL;
	
	//MFC3_Warning:BOOL;
	MFC3:BOOL;
	
	//MFC4_Warning:BOOL;
	MFC4:BOOL;
	
	//MFC5_Warning:BOOL;
	MFC5:BOOL;
	
	//MFC6_Warning:BOOL;
	MFC6:BOOL;
	
	//MFC7_Warning:BOOL;
	MFC7:BOOL;
	
	//MFC8_Warning:BOOL;
	MFC8:BOOL;
	
	//MFC9_Warning:BOOL;
	MFC9:BOOL;
	
	//WALL_TEMP_Warning:BOOL;
	WALL_TEMP:BOOL;
	
	//LID_TEMP_Warning:BOOL;
	LID_TEMP:BOOL;
	
	//STAGE_EDGE_TEMP_Warning:BOOL;
	STAGE_EDGE_TEMP:BOOL;
	
	//STAGE_CENTER_TEMP_Warning: BOOL;
	STAGE_CENTER_TEMP: BOOL;
	

	Gas1FlowPressureOutOfRange:BOOL;
	Gas2FlowPressureOutOfRange:BOOL;
	Gas3FlowPressureOutOfRange:BOOL;
	Gas4FlowPressureOutOfRange:BOOL;
	Gas5FlowPressureOutOfRange:BOOL;
	Gas6FlowPressureOutOfRange:BOOL;
	Gas7FlowPressureOutOfRange:BOOL;
	Gas8FlowPressureOutOfRange:BOOL;
	Gas9FlowPressureOutOfRange:BOOL;	
	
	
	TurboN2PurgePressureOutOfRange:BOOL;
	PrepareTransferTimerout:BOOL;
	TransferWaferTimeout:BOOL;
	OpenGasValveTimeout:BOOL;
	CloseGasValveTimeout:BOOL;
	OpenCloseSlitValveTimeout:BOOL;
	ATMCheckTimeout:BOOL;
	
	PLC:BOOL;	
	DRY_PUMP:BOOL;
	PENDULUM_VALVE:BOOL;
	TURBO_PUMP:BOOL;
	CHILLER1:BOOL;
	CHILLER2:BOOL;
	
	//PROCESS TOLERANCE
	TOLERANCE_PRESSURE:BOOL;
	TOLERANCE_MFC1:BOOL;
	TOLERANCE_MFC2:BOOL;
	TOLERANCE_MFC3:BOOL;
	TOLERANCE_MFC4:BOOL;
	TOLERANCE_MFC5:BOOL;
	TOLERANCE_MFC6:BOOL;
	TOLERANCE_MFC7:BOOL;
	TOLERANCE_MFC8:BOOL;
	TOLERANCE_MFC9:BOOL;
	TOLERANCE_WALL_TEMP:BOOL;
	TOLERANCE_LID_TEMP:BOOL;
	TOLERANCE_STAGE_EDGE_TEMP:BOOL;
	TOLERANCE_STAGE_CENTER_TEMP: BOOL;


	
END_STRUCT
END_TYPE

// ---- DUTs/Info/Warning.TcDUT
TYPE Warning :
STRUCT
	//PRESSURE_Alarm:BOOL;
	PRESSURE:BOOL;
	
	//MFC1_Alarm:BOOL;
	MFC1:BOOL;
	
	//MFC2_Alarm:BOOL;
	MFC2:BOOL;
	
	//MFC3_Alarm:BOOL;
	MFC3:BOOL;
	
	//MFC4_Alarm:BOOL;
	MFC4:BOOL;
	
	//MFC5_Alarm:BOOL;
	MFC5:BOOL;
	
	//MFC6_Alarm:BOOL;
	MFC6:BOOL;
	
	//MFC7_Alarm:BOOL;
	MFC7:BOOL;
	
	//MFC8_Alarm:BOOL;
	MFC8:BOOL;
	
	//MFC9_Alarm:BOOL;
	MFC9:BOOL;
	
	//WALL_TEMP_Alarm:BOOL;
	WALL_TEMP:BOOL;
	
	//LID_TEMP_Alarm:BOOL;
	LID_TEMP:BOOL;
	
	//STAGE_EDGE_TEMP_Alarm:BOOL;
	STAGE_EDGE_TEMP:BOOL;
	
	//STAGE_CENTER_TEMP_ALARM: BOOL;
	STAGE_CENTER_TEMP: BOOL;
	
	
	CHILLER1:BOOL;
	CHILLER2:BOOL;
	
	
	
	OpenCloseSlitValveTimeout:BOOL;
	Gas1FlowPressureOutOfRange:BOOL;
	Gas2FlowPressureOutOfRange:BOOL;
	Gas3FlowPressureOutOfRange:BOOL;
	Gas4FlowPressureOutOfRange:BOOL;
	Gas5FlowPressureOutOfRange:BOOL;
	Gas6FlowPressureOutOfRange:BOOL;
	Gas7FlowPressureOutOfRange:BOOL;
	Gas8FlowPressureOutOfRange:BOOL;
	Gas9FlowPressureOutOfRange:BOOL;	
	
	
	//PROCESS TOLERANCE
	TOLERANCE_PRESSURE:BOOL;
	TOLERANCE_MFC1:BOOL;
	TOLERANCE_MFC2:BOOL;
	TOLERANCE_MFC3:BOOL;
	TOLERANCE_MFC4:BOOL;
	TOLERANCE_MFC5:BOOL;
	TOLERANCE_MFC6:BOOL;
	TOLERANCE_MFC7:BOOL;
	TOLERANCE_MFC8:BOOL;
	TOLERANCE_MFC9:BOOL;
	TOLERANCE_WALL_TEMP:BOOL;
	TOLERANCE_LID_TEMP:BOOL;
	TOLERANCE_STAGE_EDGE_TEMP:BOOL;
	TOLERANCE_STAGE_CENTER_TEMP: BOOL;	
	

END_STRUCT
END_TYPE

// ---- DUTs/Info/Info.TcDUT
TYPE Info :
STRUCT
	Warning:Warning;
	Alarm:Alarm;
	
	//Tolerance	
	(*PRESSURE_Warning:BOOL;
	PRESSURE_Alarm:BOOL;
	
	MFC1_Warning:BOOL;
	MFC1_Alarm:BOOL;
	
	MFC2_Warning:BOOL;
	MFC2_Alarm:BOOL;
	
	MFC3_Warning:BOOL;
	MFC3_Alarm:BOOL;
	
	MFC4_Warning:BOOL;
	MFC4_Alarm:BOOL;
	
	MFC5_Warning:BOOL;
	MFC5_Alarm:BOOL;
	
	MFC6_Warning:BOOL;
	MFC6_Alarm:BOOL;
	
	MFC7_Warning:BOOL;
	MFC7_Alarm:BOOL;
	
	MFC8_Warning:BOOL;
	MFC8_Alarm:BOOL;
	
	MFC9_Warning:BOOL;
	MFC9_Alarm:BOOL;
	
	WALL_TEMP_Warning:BOOL;
	WALL_TEMP_Alarm:BOOL;
	
	LID_TEMP_Warning:BOOL;
	LID_TEMP_Alarm:BOOL;
	
	STAGE_EDGE_TEMP_Warning:BOOL;
	STAGE_EDGE_TEMP_Alarm:BOOL;
	
	STAGE_CENTER_TEMP_Warning: BOOL;
	STAGE_CENTER_TEMP_ALARM: BOOL;
	*)

	
	(*//
	ALARM_PLC:BOOL;	
	ALARM_DRY_PUMP:BOOL;
	ALARM_PENDULUM_VALVE:BOOL;
	ALARM_TURBO_PUMP:BOOL;
	ALARM_CHILLER1:BOOL;
	ALARM_CHILLER2:BOOL;

	WARNING_CHILLER1:BOOL;
	WARNING_CHILLER2:BOOL;
	*)
	
	
	
	
	
	
	
	
	
	
	
	
	
	
	
	
	
	
	
	
	
	
	
	
	
	
	
	
	
	
	
	
	
	
	
	
	
END_STRUCT
END_TYPE

// ---- DUTs/SPLC/PLC_TO_SPLC.TcDUT
TYPE PLC_TO_SPLC :
STRUCT
	Lid_Temp_OK,
	Chamber_Temp_OK,
	APC_Temp_OK,
	Gate_Valve_Temp_OK,
	Gas_Line_Temp_OK	,
	TMP_Interlock_OK	,
	PS1_Interlock_OK	,
	PS2_Interlock_OK	,
	SPLC_ErrorAcknowledgement,
	SPLC_Restart,
	SPLC_Run	:BOOL;
END_STRUCT
END_TYPE

// ---- DUTs/SPLC/SPLC_TO_PLC.TcDUT
TYPE SPLC_TO_PLC :
STRUCT
	EV1_EN,
	EV2_EN,
	EV3_EN,
	EV4_EN,
	HTR_APC_EN,
	HTR_CHAMBER_EN,
	HTR_FORLINE_EN,
	HTR_GAS_BOX,
	HTR_GATE_VALVE,
	HTR_LID,
	PROCESS_EN,
	DRY_PUMP_PW_EN,
	TMP_PW_EN,
	TRANSFER_EN,
	VALVE_ACID_EXHAUST_OPEN_EN,
	VALVE_CM_OPEN_EN,	
	VALVE_DRY_PUMP_EN,
	VALVE_TMP_BACK_OPEN_EN,
	VALVE_APC_OPEN_EN,
	WAFER_MOVING_IN_EN,	
	SPLC_Com_err,
	SPLC_FB_Err 	:BOOL;
END_STRUCT
END_TYPE

// ---- GVLs/ECC.TcGVL
{attribute 'qualified_only'}
VAR_GLOBAL
//HW_IO
	CHAMBER_IN	AT	%I*	:CHAMBER_IN;
	CHAMBER_OUT	AT	%Q*	:CHAMBER_OUT;
	
	IGS_IN		AT	%I*	:IGS_IN;
	IGS_OUT		AT	%Q*	:IGS_OUT;
//MFC
	MFC_PV 		AT	%I*	:ARRAY [1..10] OF STR_FCSP700_INPUT;
	MFC_SV 		AT	%Q*	:ARRAY [1..10] OF STR_FCSP700_OUTPUT;

//EV
	EV1 		AT 	%Q*	:STR_EX260_SEC;

	EV2 		AT 	%Q*	:STR_EX260_SEC;

	EV3 		AT 	%Q*	:STR_EX260_SEC;

	EV4 		AT 	%Q*	:STR_EX260_SEC;
		
//APC VALVE
	APC_PV		AT 	%I*	:VAT_IN;
	APC_SV		AT 	%Q*	:VAT_OUT;

//TMP
	TURBO_SV	AT	%Q*	:TMP_OUT;

	TURBO_PV	AT 	%I*	:TMP_IN;
	
//CDG PG/VG
	VG103_PV	AT 	%I*	:STR_CDG200D;

	VG101_PV	AT 	%I*	:STR_CDG200D;

	VG102_PV	AT 	%I*	:STR_CDG200D;

	BA1_PV		AT 	%I*	:STR_BPG400;

	VG104_PV	AT 	%I*	:STR_CDG200D;

//CHILLER
	CHILLER1_PV	AT 	%I*	:CHILLER_IN;
	CHILLER1_SV	AT 	%Q*	:CHILLER_OUT;
	
	CHILLER2_PV	AT 	%I*	:CHILLER_IN;
	CHILLER2_SV	AT 	%Q*	:CHILLER_OUT;
END_VAR

// ---- GVLs/GV.TcGVL
{attribute 'qualified_only'}
VAR_GLOBAL
//************************HW-IO******************************************
	NDI:STR_NDI;	
	NDO:STR_NDO;
	AI:STR_AI;
	AO:STR_AO;
	
	//POWER
	TURBO_PUMP_POWER_ON :BOOL;
	PENDULUM_VALVE_HEATER_POWER_ON:BOOL;
	LID_HEATER_POWER_ON:BOOL;
	CHAMBER_HEATER_POWER_ON:BOOL;
	IGS_HEATER_POWER_ON:BOOL;
	TAPE_HEATER_POWER_ON:BOOL;
	FORELINE_HEATER_POWER_ON:BOOL;
	GATE_VALVE_HEATER_POWER_ON:BOOL;
	
	//HEATER	
	LID_HEATER_AUTO_TUNE_EN				:ARRAY[1..10] OF BOOL;
	CHAMBER_HEATER_AUTO_TUNE_EN			:ARRAY[1..10] OF BOOL;
	PEN_VALVE_HEATER_AUTO_TUNE_EN		:BOOL;
	GATE_VALVE_HEATER_AUTO_TUNE_EN		:BOOL;
	IGS_HEATER_AUTO_TUNE_EN				:ARRAY[1..10] OF BOOL;
	TAPE_HEATER_AUTO_TUNE_EN			:ARRAY[1..10] OF BOOL;
	FORELINE_HEATER_AUTO_TUNE_EN		:ARRAY[1..20] OF BOOL;
	
	LID_HEATER_AUTO_TUNE_OUTPUT			:ARRAY[1..10] OF REAL;
	CHAMBER_HEATER_AUTO_TUNE_OUTPUT		:ARRAY[1..10] OF REAL;
	PEN_VALVE_HEATER_AUTO_TUNE_OUTPUT	:REAL;
	GATE_VALVE_HEATER_AUTO_TUNE_OUTPUT	:REAL;
	IGS_HEATER_AUTO_TUNE_OUTPUT			:ARRAY[1..10] OF REAL;
	TAPE_HEATER_AUTO_TUNE_OUTPUT		:ARRAY[1..10] OF REAL;
	FORELINE_HEATER_AUTO_TUNE_OUTPUT	:ARRAY[1..20] OF REAL;
	
	LID_HEATER_SSR_ON					:ARRAY[1..10] OF BOOL;
	CHAMBER_HEATER_SSR_ON				:ARRAY[1..10] OF BOOL;
	PEN_VALVE_HEATER_SSR_ON				:BOOL;
	GATE_VALVE_SSR_ON					:BOOL;
	IGS_HEATER_SSR_ON					:ARRAY[1..10] OF BOOL;
	TAPE_HEATER_SSR_ON					:ARRAY[1..10] OF BOOL;
	FORELINE_HEATER_SSR_ON				:ARRAY[1..20] OF BOOL;
	
	
//INTERLOCK
	ALARM_OCC:BOOL;
	WARNING_OCC:BOOL;
	
//UI-Config
	PMConfig:ConfigPM;
	
	MFCVerification:ConfigMfcVer;
	
	Chiller:ConfigChiller;	
	InnerChiller:ConfigChiller;
	OuterChiller:ConfigChiller;
	TopChiller:ConfigChiller;
	
	DryPump:ConfigDryPump;
	
	Mfcgas1					:ConfigMfcGas;
	Mfcgas2					:ConfigMfcGas;
	Mfcgas3					:ConfigMfcGas;
	Mfcgas4					:ConfigMfcGas;
	Mfcgas5					:ConfigMfcGas;
	Mfcgas6					:ConfigMfcGas;
	Mfcgas7					:ConfigMfcGas;
	Mfcgas8					:ConfigMfcGas;
	Mfcgas9					:ConfigMfcGas;
	Mfcgas10				:ConfigMfcGas;
	Mfcgas11				:ConfigMfcGas;
	Mfcgas12				:ConfigMfcGas;	
	MfcN2					:ConfigMfcGas;
	MfcHe					:ConfigMfcGas; 
	
	Pump:ConfigPump;
	
	Purge:ConfigPurge;
	
	PendulumHeater:ConfigHeater;
	LidHeater:ConfigHeater;
	ChamberHeater:ConfigHeater;
	IGSHeater:ConfigHeater;
	TapeHeater:ConfigHeater;
	ForelineHeater:ConfigHeater;
	
	ElectrostaticVoltageSource:ConfigElectrostaticVoltageSource;
	
	TurboPump:ConfigTurboPump;
	
	PendulumValve:ConfigPendulumValve;
	
	IdleClean:ConfigIdleClean;
	
	EPD:ConfigEPD;
	
	HighTemperatureChiller:ConfigHighTempChiller;
		
	
//UI-RECIPE
	Step_Num:INT;
	SetpArray:ARRAY[1..100] OF RecipeEachStep;
	
//INTERLOCK
	TurboN2PurgePressure:INT;	//PS103	
	
	Process_Start:BOOL;
	Process_Stop:BOOL;
END_VAR

// ---- GVLs/GV_H.TcGVL
{attribute 'qualified_only'}
VAR_GLOBAL PERSISTENT
	LID_HEATER_PID				:ARRAY[1..10] OF STR_PID;
	CHAMBER_HEATER_PID			:ARRAY[1..10] OF STR_PID;
	PEN_VALVE_HEATER_PID		:STR_PID;
	GATE_VALVE_HEATER_PID		:STR_PID;
	IGS_HEATER_PID				:ARRAY[1..10] OF STR_PID;
	TAPE_HEATER_PID				:ARRAY[1..10] OF STR_PID;
	FORELINE_HEATER_PID			:ARRAY[1..20] OF STR_PID;
END_VAR

// ---- GVLs/GV_IL.TcGVL
{attribute 'qualified_only'}
VAR_GLOBAL
//Tolerance
	PRESSURE_WARNING:BOOL;
	PRESSURE_ALARM:BOOL;
	
	MFC1_WARNING:BOOL;
	MFC1_Alarm:BOOL;
	
	MFC2_WARNING:BOOL;
	MFC2_Alarm:BOOL;
	
	MFC3_WARNING:BOOL;
	MFC3_Alarm:BOOL;
	
	MFC4_WARNING:BOOL;
	MFC4_Alarm:BOOL;
	
	MFC5_WARNING:BOOL;
	MFC5_Alarm:BOOL;
	
	MFC6_WARNING:BOOL;
	MFC6_Alarm:BOOL;
	
	MFC7_WARNING:BOOL;
	MFC7_Alarm:BOOL;
	
	MFC8_WARNING:BOOL;
	MFC8_Alarm:BOOL;
	
	MFC9_WARNING:BOOL;
	MFC9_Alarm:BOOL;
	
	WALL_TEMP_WARNING:BOOL;
	WALL_TEMP_Alarm:BOOL;
		
	LID_TEMP_WARNING:BOOL;
	LID_TEMP_Alarm:BOOL;
	
	STAGE_EDGE_TEMP_WARNING:BOOL;
	STAGE_EDGE_TEMP_Alarm:BOOL;
	
	STAGE_CENTER_TEMP_WARNING: BOOL;
	STAGE_CENTER_TEMP_ALARM: BOOL;
	
//INTERLOCK
	STATUS_PrepareTransfer:BOOL;
	STATUS_TransferWafer:BOOL;
	STATUS_OpenGasValve:BOOL;
	STATUS_CloseGasValve:BOOL;
	STATUS_OpenCloseSlitValve:BOOL;
	
	AV1_EN	:BOOL;//	MFC1前气动阀(N2-1)	使能
	AV2_EN	:BOOL;//	MFC1前气动阀(N2-3)	使能
	AV3_EN	:BOOL;//	MFC1后气动阀	使能
	AV4_EN	:BOOL;//	MFC2前气动阀(N2-1)	使能
	AV5_EN	:BOOL;//	MFC2前气动阀(NH3)	使能
	AV6_EN	:BOOL;//	MFC2后气动阀	使能
	AV7_EN	:BOOL;//	MFC3前气动阀(N2-1)	使能
	AV8_EN	:BOOL;//	MFC3前气动阀(NH3)	使能
	AV9_EN	:BOOL;//	MFC3后气动阀	使能
	AV10_EN	:BOOL;//	N2-1 总进气阀	使能
	AV11_EN	:BOOL;//	MFC1,2,3 BYPASS阀(N2-1)	使能
	AV12_EN	:BOOL;//	N2-2 总进气阀	使能
	AV13_EN	:BOOL;//	MFC5,6,7 BYPASS阀(N2-2)	使能
	AV14_EN	:BOOL;//	MFC5前气动阀(N2-2)	使能
	AV15_EN	:BOOL;//	MFC5前气动阀(HF)	使能
	AV16_EN	:BOOL;//	MFC5后气动阀	使能
	AV17_EN	:BOOL;//	OF前气动阀(N2-2)	使能
	AV18_EN	:BOOL;//	OF前气动阀(HF)	使能
	AV19_EN	:BOOL;//	OF后气动阀	使能
	AV20_EN	:BOOL;//	MFC6前气动阀(N2-2)	使能
	AV21_EN	:BOOL;//	MFC6前气动阀(Ar)	使能
	AV22_EN	:BOOL;//	MFC6后气动阀	使能
	AV23_EN	:BOOL;//	MFC7前气动阀(N2-2)	使能
	AV24_EN	:BOOL;//	MFC7前气动阀(Ar)	使能
	AV25_EN	:BOOL;//	MFC7后气动阀	使能
	AV26_EN	:BOOL;//	Chamber总进气阀(NH3,N2)	使能
	AV27_EN	:BOOL;//	Chamber总进气阀(HF,Ar)	使能
	AV101_EN:BOOL;//	Dry Pump至Chamber	使能
	AV102_EN:BOOL;//	Dry Pump至TMP	使能
	AV103_EN:BOOL;//	TMP N2 Purge	使能
	AV104_EN:BOOL;//	VG103压力计前置保护阀	使能
	AV105_EN:BOOL;//	BA01压力计前置保护阀	使能
	AV106_EN:BOOL;//	酸排阀	使能
	APC_EN	:BOOL;//	APC Open	使能

	AV1_EN_Bypass	:BOOL;//	MFC1前气动阀(N2-1)	使能Bypass
	AV2_EN_Bypass	:BOOL;//	MFC1前气动阀(N2-3)	使能Bypass
	AV3_EN_Bypass	:BOOL;//	MFC1后气动阀	使能Bypass
	AV4_EN_Bypass	:BOOL;//	MFC2前气动阀(N2-1)	使能Bypass
	AV5_EN_Bypass	:BOOL;//	MFC2前气动阀(NH3)	使能Bypass
	AV6_EN_Bypass	:BOOL;//	MFC2后气动阀	使能Bypass
	AV7_EN_Bypass	:BOOL;//	MFC3前气动阀(N2-1)	使能Bypass
	AV8_EN_Bypass	:BOOL;//	MFC3前气动阀(NH3)	使能Bypass
	AV9_EN_Bypass	:BOOL;//	MFC3后气动阀	使能Bypass
	AV10_EN_Bypass	:BOOL;//	N2-1 总进气阀	使能Bypass
	AV11_EN_Bypass	:BOOL;//	MFC1,2,3 BYPASS阀(N2-1)	使能Bypass
	AV12_EN_Bypass	:BOOL;//	N2-2 总进气阀	使能Bypass
	AV13_EN_Bypass	:BOOL;//	MFC5,6,7 BYPASS阀(N2-2)	使能Bypass
	AV14_EN_Bypass	:BOOL;//	MFC5前气动阀(N2-2)	使能Bypass
	AV15_EN_Bypass	:BOOL;//	MFC5前气动阀(HF)	使能Bypass
	AV16_EN_Bypass	:BOOL;//	MFC5后气动阀	使能Bypass
	AV17_EN_Bypass	:BOOL;//	OF前气动阀(N2-2)	使能Bypass
	AV18_EN_Bypass	:BOOL;//	OF前气动阀(HF)	使能Bypass
	AV19_EN_Bypass	:BOOL;//	OF后气动阀	使能Bypass
	AV20_EN_Bypass	:BOOL;//	MFC6前气动阀(N2-2)	使能Bypass
	AV21_EN_Bypass	:BOOL;//	MFC6前气动阀(Ar)	使能Bypass
	AV22_EN_Bypass	:BOOL;//	MFC6后气动阀	使能Bypass
	AV23_EN_Bypass	:BOOL;//	MFC7前气动阀(N2-2)	使能Bypass
	AV24_EN_Bypass	:BOOL;//	MFC7前气动阀(Ar)	使能Bypass
	AV25_EN_Bypass	:BOOL;//	MFC7后气动阀	使能Bypass
	AV26_EN_Bypass	:BOOL;//	Chamber总进气阀(NH3,N2)	使能Bypass
	AV27_EN_Bypass	:BOOL;//	Chamber总进气阀(HF,Ar)	使能Bypass
	AV101_EN_Bypass	:BOOL;//	Dry Pump至Chamber	使能Bypass
	AV102_EN_Bypass	:BOOL;//	Dry Pump至TMP	使能Bypass
	AV103_EN_Bypass	:BOOL;//	TMP N2 Purge	使能Bypass
	AV104_EN_Bypass	:BOOL;//	VG103压力计前置保护阀	使能Bypass
	AV105_EN_Bypass	:BOOL;//	BA01压力计前置保护阀	使能Bypass
	AV106_EN_Bypass	:BOOL;//	酸排阀	使能Bypass
	APC_EN_Bypass	:BOOL;//	APC Open	使能Bypass

	HTR_APC_EN,
	HTR_CHAMBER_EN,
	HTR_FORLINE_EN,
	HTR_GAS_BOX_EN,
	HTR_GATE_VALVE_EN,
	HTR_LID_EN:BOOL;
	
	HTR_APC_EN_Bypass,
	HTR_CHAMBER_EN_Bypass,
	HTR_FORLINE_EN_Bypass,
	HTR_GAS_BOX_EN_Bypass,
	HTR_GATE_VALVE_EN_Bypass,
	HTR_LID_EN_Bypass:BOOL;
	
//PROCESS
	Process_RUN: BOOL;
	Process_Stop: BOOL;
	
//SPLC
	Lid_Temp_OT_Bypass,
	Chamber_Temp_OT_Bypass,
	APC_Temp_OT_Bypass,
	Gate_Valve_Temp_OT_Bypass,
	Gas_Line_Temp_OT_Bypass	,
	TMP_ALARM_Bypass	,
	PS1_ALM_Bypass,
	PS2_ALM_Bypass,
	SPLC_manual_ErrorAck	:BOOL;	
	SPLC_TO_PLC	AT	%I*	:SPLC_TO_PLC;
	PLC_TO_SPLC	AT	%Q*	:PLC_TO_SPLC;
	
(*	
	Lid_Temp_OK,
	Chamber_Temp_OK,
	APC_Temp_OK,
	Gate_Valve_Temp_OK,
	Gas_Line_Temp_OK	,
	TMP_Interlock_OK	,
	PS1_Interlock_OK	,
	PS2_Interlock_OK	AT	%Q*	:BOOL;	
	
	EV1_EN,
	EV2_EN,
	EV3_EN,
	EV4_EN,
	HTR_APC_EN,
	HTR_CHAMBER_EN,
	HTR_FORLINE_EN,
	HTR_GAS_BOX,
	HTR_GATE_VALVE,
	HTR_LID,
	PROCESS_EN,
	TMP_PW_EN,
	TRANSFER_EN,
	VALVE_ACID_EXHAUST_OPEN_EN,
	VALVE_CM_OPEN_EN,
	VALVE_DRY_PUMP_OPEN_EN,
	VALVE_TMP_BACK_OPEN_EN,
	VALVE_APC_OPEN_EN,
	WAFER_MOVING_IN_EN	AT	%I*	:BOOL;
	
	SPLC_ErrorAcknowledgement,
	SPLC_manual_ErrorAck,
	SPLC_Restart,
	SPLC_Run	AT	%Q*	:BOOL;			
	SPLC_Com_err,
	SPLC_FB_Err AT	%I*	:BOOL;
	*)
	
	
END_VAR

// ---- GVLs/PC_PLC/PM.TcGVL
{attribute 'qualified_only'}
VAR_GLOBAL
	HeartBeat:REAL;
//HW
	NDI:STR_NDI;
	AI:STR_AI;	
//SYSTEM
	Info:Info;
	ProcessFeedBack:ProcessRecipeFeedBack;	
END_VAR

// ---- GVLs/PC_PLC/UI.TcGVL
{attribute 'qualified_only'}
VAR_GLOBAL
	HeartBeat:REAL;
//HW
	NDO:STR_NDO;
	AO:STR_AO;
	
//Config
	PMConfig:ConfigPM;
	
	MFCVerification:ConfigMfcVer;
	
	Chiller:ConfigChiller;	
	InnerChiller:ConfigChiller;
	OuterChiller:ConfigChiller;
	TopChiller:ConfigChiller;
	
	DryPump:ConfigDryPump;
	
	Mfcgas1:ConfigMfcGas;
	Mfcgas2:ConfigMfcGas;
	Mfcgas3:ConfigMfcGas;
	Mfcgas4:ConfigMfcGas;
	Mfcgas5:ConfigMfcGas;
	Mfcgas6:ConfigMfcGas;
	Mfcgas7:ConfigMfcGas;
	Mfcgas8:ConfigMfcGas;
	Mfcgas9:ConfigMfcGas;
	Mfcgas10:ConfigMfcGas;
	Mfcgas11:ConfigMfcGas;
	Mfcgas12:ConfigMfcGas;	
	MfcN2:ConfigMfcGas;
	MfcHe:ConfigMfcGas;
	
	Pump:ConfigPump;
	
	Purge:ConfigPurge;
	
	PendulumHeater:ConfigHeater;
	LidHeater:ConfigHeater;
	ChamberHeater:ConfigHeater;
	IGSHeater:ConfigHeater;
	TapeHeater:ConfigHeater;
	ForelineHeater:ConfigHeater;
	
	ElectrostaticVoltageSource:ConfigElectrostaticVoltageSource;
	
	TurboPump:ConfigTurboPump;
	
	PendulumValve:ConfigPendulumValve;
	
	IdleClean:ConfigIdleClean;
	
	EPD:ConfigEPD;
	
	HighTemperatureChiller:ConfigHighTempChiller;
	
	
	
	
//RECIPE
	Step_Num:INT;
	SetpArray:ARRAY[1..100] OF RecipeEachStep;

	
//INTERLOCK
	TurboN2PurgePressure:INT;	//PS103	
	
//PROCESS
	Process_Start:BOOL;
	Process_Stop:BOOL;

//*********************READ**************
//	Process_Finished:BOOL;

//WARNING&ALARM

	Warning_And_Alarm_RST:BOOL;

	
END_VAR

// ---- POUs/PRG/MAIN.TcPOU
PROGRAM MAIN
VAR
	ENABLE:BOOL;

//RECIPE
PROCESS:PROCESS;
PROCESS_EN:BOOL;
PROCESS_RUN:BOOL;
PROCESS_STOP:BOOL;

P_NO:INT;

CYCLE_EN:BOOL;
CYCLE_NUM:INT;
CYCLE_START_STEP_NO:INT;

STEP_NO:INT;
NEXTSTEP_EN:BOOL;

UPS:FB_S_UPS_BAPI;

END_VAR

//UPS
UPS(
	sNetID:= , 
	iPLCPort:= 851, 
	tTimeout:= , 
	eUpsMode:= eSUPS_WrPersistData_shutdown, 
	ePersistentMode:= , 
	tRecoverTime:= T#10S, 
	bPowerFailDetect=> , 
	eState=> , 
	nCapacity=> , 
	bBusy=> , 
	bError=> , 
	nErrID=> );

//******************************IO*********************************
	IO_EXCHANGE();

//*****************************CONFIGURATION***********************
	IL();

//*****************************INTERLOCK***************************
	Temp();
	
//*****************************PROCESS*****************************
	PROCESS_RUN:=GV.Process_Start AND NOT GV.ALARM_OCC;
	PROCESS_STOP:=GV.Process_Stop OR GV.ALARM_OCC;

	//PROCESS ENABLE
	IF PROCESS_RUN AND NOT PROCESS_EN
		THEN
		CYCLE_NUM := 0;
		STEP_NO:=1;
		P_NO:=1;
		PM.ProcessFeedBack.ProcessFinished:=FALSE;
	END_IF
		IF PROCESS_RUN AND NOT PROCESS_EN
		THEN
		PROCESS_EN:=TRUE;		
	END_IF;
	
	IF PROCESS_STOP
		THEN
		CYCLE_NUM:=0;
		CYCLE_EN:=FALSE;
		PROCESS_EN:=FALSE;
		PROCESS_RUN:=FALSE;
	END_IF;
	IF NOT PM.ProcessFeedBack.ProcessFinished
		THEN 
			PM.ProcessFeedBack.CurrentStepNo:=STEP_NO;
		ELSE
			PM.ProcessFeedBack.CurrentStepNo:=STEP_NO-1;
	END_IF
	
	IF PROCESS_EN
		THEN 
		PM.ProcessFeedBack.ProcessStart:=TRUE;
		PM.ProcessFeedBack.CurrentStepstart:=TRUE;
		ELSE
			PM.ProcessFeedBack.ProcessStart:=FALSE;
			PM.ProcessFeedBack.CurrentStepstart:=FALSE;
		END_IF
	
	IF GV.Step_Num<STEP_NO 
		THEN 	
		PM.ProcessFeedBack.ProcessFinished:=TRUE;
	END_IF
	IF  GV.ALARM_OCC
		THEN
		PROCESS_EN:=FALSE;	
		
	END_IF
	
	IF STEP_NO<1 OR STEP_NO >100
		THEN 
		STEP_NO:=1;
	END_IF
	
	//CYCLE初始化
	IF GV.SetpArray[STEP_NO].CycleStart AND CYCLE_EN=FALSE
		THEN 
		CYCLE_EN				:=	TRUE;
		CYCLE_START_STEP_NO		:=	STEP_NO;
		CYCLE_NUM				:=	GV.SetpArray[STEP_NO].CycleNumber;
	END_IF;	
	
	//STEP
	PROCESS(
	ENABLE			:= 	PROCESS_EN, 
	NEXTSTEP_EN		:=	NEXTSTEP_EN,
	Alarm_RST		:=	UI.Warning_And_Alarm_RST,
	PMStableTime	:=	GV.PMConfig.PMStableTime,
	STEP_DATA		:= 	GV.SetpArray[STEP_NO],  
	);
	
	//PROCESS FLOW	
	CASE P_NO OF
		1:	IF NOT PROCESS_EN 
				THEN 
				P_NO:=100;
				ELSE
				P_NO:=2;	
			END_IF;
			NEXTSTEP_EN:=FALSE;
			
		2:	IF PROCESS.NEXTSTEP 
				THEN 
				PM.ProcessFeedBack.CurrentStepFinished:=TRUE;
				PM.ProcessFeedBack.CurrentStepstart:=FALSE;
				P_NO:=3;
			END_IF;
			
		3:	IF CYCLE_EN
			THEN
				P_NO:=10;
				ELSE
				P_NO:=20;
			END_IF
		
		10:	IF GV.SetpArray[STEP_NO].CycleEnd 
				THEN 
				P_NO:=11; 
				ELSE
				P_NO:=20; 
			END_IF;	
		
		11:	IF CYCLE_NUM=0 
				THEN 
				P_NO:=20; 
				CYCLE_EN:=FALSE;
				ELSE
				CYCLE_NUM:=CYCLE_NUM-1; 
				P_NO:=21; 
			END_IF;	
				
		20:	STEP_NO:=STEP_NO+1;
			NEXTSTEP_EN:=TRUE;
			P_NO:=1; 
			PM.ProcessFeedBack.CurrentStepstart:=TRUE;
			PM.ProcessFeedBack.CurrentStepFinished:=FALSE;
			
		21:	STEP_NO:=CYCLE_START_STEP_NO;
			NEXTSTEP_EN:=TRUE;
			P_NO:=1;
		
		100:;	
	END_CASE;	
		
	
	IF	PROCESS_EN
		THEN
//******************工艺参数赋值***************
		//APC
		GV.	AO.	APC.TARGET_PRESSURE	:=	PROCESS.APC_PRESSURE;
		GV.	AO.	APC.TARGET_POSITION	:=	PROCESS.APC_POSITION;
		GV.	AO.	APC.CONTROL_MODE	:=	PROCESS.APC_CONTROL_MODE;
		
		//MFC
		GV.AO.MFC1_Flow_Setpoint	:=	PROCESS.MFC1_SV;
		GV.AO.MFC2_Flow_Setpoint	:=	PROCESS.MFC2_SV;
		GV.AO.MFC3_Flow_Setpoint	:=	PROCESS.MFC3_SV;
		GV.AO.MFC4_Flow_Setpoint	:=	PROCESS.MFC4_SV;
		GV.AO.MFC5_Flow_Setpoint	:=	PROCESS.MFC5_SV;
		GV.AO.MFC6_Flow_Setpoint	:=	PROCESS.MFC6_SV;
		GV.AO.MFC7_Flow_Setpoint	:=	PROCESS.MFC7_SV;
	//	GV.AO.MFC8_Flow_Setpoint	:=	PROCESS.MFC8_SV;
	//	GV.AO.MFC9_Flow_Setpoint	:=	PROCESS.MFC9_SV;
		
//LID HEATER
		GV.AO.LID_Temp_SV			:=	PROCESS.LID_TEMP;		
		
//CHAMBER HEATER
		GV.AO.	Chamber_Temp1_SV	:=	
		GV.AO.	Chamber_Temp2_SV	:=	
		GV.AO.	Chamber_Temp3_SV	:=	PROCESS.WALL_TEMP;
//CHILLER
	//	GV.		CHILLER2_TEMP_SV	 	:=	PROCESS.STAGE_EDGE_TEMP;	//CHILLER1
	//	GV.		CHILLER1_TEMP_SV	 	:=	PROCESS.STAGE_EDGE_TEMP;	//CHILLER2
		
//************************TOLERANCE 赋值****************
		

//************************VALVE动作****************
		GV.NDO.AV1	:=	FALSE	;//	(	GV.AO.MFC1_Flow_Setpoint>0	)	AND	PM.INFO.Alarm.TOLERANCE_MFC1	AND	GV_IL.AV1_EN	;
		GV.NDO.AV2	:=			(	GV.AO.MFC1_Flow_Setpoint>0	)	AND	PM.INFO.Alarm.TOLERANCE_MFC1	AND	GV_IL.AV2_EN	;
		GV.NDO.AV3	:=			(	GV.AO.MFC1_Flow_Setpoint>0	)	AND	PM.INFO.Alarm.TOLERANCE_MFC1	AND	GV_IL.AV3_EN	;
		GV.NDO.AV4	:=	FALSE	;//	(	GV.AO.MFC2_Flow_Setpoint>0	)	AND	PM.INFO.Alarm.TOLERANCE_MFC2	AND	GV_IL.AV4_EN	;
		GV.NDO.AV5	:=			(	GV.AO.MFC2_Flow_Setpoint>0	)	AND	PM.INFO.Alarm.TOLERANCE_MFC2	AND	GV_IL.AV5_EN	;
		GV.NDO.AV6	:=			(	GV.AO.MFC2_Flow_Setpoint>0	)	AND	PM.INFO.Alarm.TOLERANCE_MFC2	AND	GV_IL.AV6_EN	;
		GV.NDO.AV7	:=	FALSE	;//	(	GV.AO.MFC3_Flow_Setpoint>0	)	AND	PM.INFO.Alarm.TOLERANCE_MFC3	AND	GV_IL.AV7_EN	;
		GV.NDO.AV8	:=			(	GV.AO.MFC3_Flow_Setpoint>0	)	AND	PM.INFO.Alarm.TOLERANCE_MFC3	AND	GV_IL.AV8_EN	;
		GV.NDO.AV9	:=			(	GV.AO.MFC3_Flow_Setpoint>0	)	AND	PM.INFO.Alarm.TOLERANCE_MFC3	AND	GV_IL.AV9_EN	;
		GV.NDO.AV10	:=	FALSE	;//	(		)	AND		AND	GV_IL.AV10_EN	;
		GV.NDO.AV11	:=	FALSE	;//	(		)	AND		AND	GV_IL.AV11_EN	;
		GV.NDO.AV12	:=	FALSE	;//	(		)	AND		AND	GV_IL.AV12_EN	;
		GV.NDO.AV13	:=	FALSE	;//	(		)	AND		AND	GV_IL.AV13_EN	;
		GV.NDO.AV14	:=	FALSE	;//	(	GV.AO.MFC5_Flow_Setpoint>0	)	AND	PM.INFO.Alarm.TOLERANCE_MFC5	AND	GV_IL.AV14_EN	;
		GV.NDO.AV15	:=			(	GV.AO.MFC5_Flow_Setpoint>0	)	AND	PM.INFO.Alarm.TOLERANCE_MFC5	AND	GV_IL.AV15_EN	;
		GV.NDO.AV16	:=			(	GV.AO.MFC5_Flow_Setpoint>0	)	AND	PM.INFO.Alarm.TOLERANCE_MFC5	AND	GV_IL.AV16_EN	;
		GV.NDO.AV17	:=	FALSE	;//	(		)	AND		AND	GV_IL.AV17_EN	;
		GV.NDO.AV18	:=	FALSE	;//	(		)	AND		AND	GV_IL.AV18_EN	;
		GV.NDO.AV19	:=	FALSE	;//	(		)	AND		AND	GV_IL.AV19_EN	;
		GV.NDO.AV20	:=	FALSE	;//	(	GV.AO.MFC6_Flow_Setpoint>0	)	AND	PM.INFO.Alarm.TOLERANCE_MFC6	AND	GV_IL.AV20_EN	;
		GV.NDO.AV21	:=			(	GV.AO.MFC6_Flow_Setpoint>0	)	AND	PM.INFO.Alarm.TOLERANCE_MFC6	AND	GV_IL.AV21_EN	;
		GV.NDO.AV22	:=			(	GV.AO.MFC6_Flow_Setpoint>0	)	AND	PM.INFO.Alarm.TOLERANCE_MFC6	AND	GV_IL.AV22_EN	;
		GV.NDO.AV23	:=	FALSE	;//	(	GV.AO.MFC7_Flow_Setpoint>0	)	AND	PM.INFO.Alarm.TOLERANCE_MFC7	AND	GV_IL.AV23_EN	;
		GV.NDO.AV24	:=			(	GV.AO.MFC7_Flow_Setpoint>0	)	AND	PM.INFO.Alarm.TOLERANCE_MFC7	AND	GV_IL.AV24_EN	;
		GV.NDO.AV25	:=			(	GV.AO.MFC7_Flow_Setpoint>0	)	AND	PM.INFO.Alarm.TOLERANCE_MFC7	AND	GV_IL.AV25_EN	;
		GV.NDO.AV26	:=	(
						((	GV.AO.MFC1_Flow_Setpoint>0	)	AND	PM.INFO.Alarm.TOLERANCE_MFC1) 
					OR ((	GV.AO.MFC2_Flow_Setpoint>0	)	AND	PM.INFO.Alarm.TOLERANCE_MFC2)
					OR ((	GV.AO.MFC3_Flow_Setpoint>0	)	AND	PM.INFO.Alarm.TOLERANCE_MFC3)
						)
						AND	GV_IL.AV26_EN	;
		GV.NDO.AV27	:=	(	
						((	GV.AO.MFC5_Flow_Setpoint>0	)	AND	PM.INFO.Alarm.TOLERANCE_MFC5)
					OR 	((	GV.AO.MFC6_Flow_Setpoint>0	)	AND	PM.INFO.Alarm.TOLERANCE_MFC6)
					OR	((	GV.AO.MFC7_Flow_Setpoint>0	)	AND	PM.INFO.Alarm.TOLERANCE_MFC7)	
						)	
						AND	GV_IL.AV27_EN	;

		
	END_IF

//TOL ALRM&WARNING
	PM.INFO.Alarm.TOLERANCE_PRESSURE			:= NOT PROCESS.PRESSURE_ALARM;
	PM.INFO.Alarm.TOLERANCE_MFC1				:= NOT PROCESS.MFC1_Alarm;
	PM.INFO.Alarm.TOLERANCE_MFC2				:= NOT PROCESS.MFC2_Alarm;
	PM.INFO.Alarm.TOLERANCE_MFC3				:= NOT PROCESS.MFC3_Alarm;
	PM.INFO.Alarm.TOLERANCE_MFC4				:= NOT PROCESS.MFC4_Alarm;
	PM.INFO.Alarm.TOLERANCE_MFC5				:= NOT PROCESS.MFC5_Alarm;
	PM.INFO.Alarm.TOLERANCE_MFC6				:= NOT PROCESS.MFC6_Alarm;
	PM.INFO.Alarm.TOLERANCE_MFC7				:= NOT PROCESS.MFC7_Alarm;
	PM.INFO.Alarm.TOLERANCE_MFC8				:= NOT PROCESS.MFC8_Alarm;
	PM.INFO.Alarm.TOLERANCE_MFC9				:= NOT PROCESS.MFC9_Alarm;
	PM.INFO.Alarm.TOLERANCE_WALL_TEMP			:= NOT PROCESS.WALL_TEMP_Alarm;
	PM.INFO.Alarm.TOLERANCE_LID_TEMP			:= NOT PROCESS.LID_TEMP_Alarm;
	PM.INFO.Alarm.TOLERANCE_STAGE_EDGE_TEMP		:= NOT PROCESS.STAGE_EDGE_TEMP_Alarm;
	PM.INFO.Alarm.TOLERANCE_STAGE_CENTER_TEMP	:= NOT PROCESS.STAGE_CENTER_TEMP_ALARM;
	
	PM.INFO.Warning.TOLERANCE_PRESSURE			:= NOT PROCESS.PRESSURE_WARNING;	
	PM.INFO.Warning.TOLERANCE_MFC1				:= NOT PROCESS.MFC1_WARNING;
	PM.INFO.Warning.TOLERANCE_MFC2				:= NOT PROCESS.MFC2_WARNING;
	PM.INFO.Warning.TOLERANCE_MFC3				:= NOT PROCESS.MFC3_WARNING;
	PM.INFO.Warning.TOLERANCE_MFC4				:= NOT PROCESS.MFC4_WARNING;
	PM.INFO.Warning.TOLERANCE_MFC5				:= NOT PROCESS.MFC5_WARNING;
	PM.INFO.Warning.TOLERANCE_MFC6				:= NOT PROCESS.MFC6_WARNING;
	PM.INFO.Warning.TOLERANCE_MFC7				:= NOT PROCESS.MFC7_WARNING;
	PM.INFO.Warning.TOLERANCE_MFC8				:= NOT PROCESS.MFC8_WARNING;
	PM.INFO.Warning.TOLERANCE_MFC9				:= NOT PROCESS.MFC9_WARNING;
	PM.INFO.Warning.TOLERANCE_WALL_TEMP			:= NOT PROCESS.WALL_TEMP_WARNING;	
	PM.INFO.Warning.TOLERANCE_LID_TEMP			:= NOT PROCESS.LID_TEMP_WARNING;	
	PM.INFO.Warning.TOLERANCE_STAGE_EDGE_TEMP	:= NOT PROCESS.STAGE_EDGE_TEMP_WARNING;		
	PM.INFO.Warning.TOLERANCE_STAGE_CENTER_TEMP	:= NOT PROCESS.STAGE_CENTER_TEMP_WARNING;

END_PROGRAM

// ---- POUs/FB/PROCESS.TcPOU
FUNCTION_BLOCK PROCESS
VAR_INPUT
	ENABLE:BOOL;
	NEXTSTEP_EN:BOOL;
	Alarm_RST:BOOL;
	PMStableTime:INT;
	STEP_DATA:RecipeEachStep;
END_VAR
VAR_OUTPUT
	
	//APC
	APC_PRESSURE:REAL;
	APC_POSITION:REAL;
	APC_CONTROL_MODE:SINT;
	
	//MFC
	MFC1_SV:REAL;
	MFC2_SV:REAL;
	MFC3_SV:REAL;
	MFC4_SV:REAL;
	MFC5_SV:REAL;
	MFC6_SV:REAL;
	MFC7_SV:REAL;
	MFC8_SV:REAL;	
	MFC9_SV:REAL;	
	
	//HEATER
	WALL_TEMP:REAL;
	LID_TEMP:REAL;
	STAGE_EDGE_TEMP:INT;
	STAGE_CENTER_TEMP:INT;
	
	//STEP
	STEP_TIME_OUT:BOOL;
	STEP_ERR:BOOL;
	NEXTSTEP:BOOL;
	
	//Tolerance
	PRESSURE_WARNING:BOOL;
	PRESSURE_ALARM:BOOL;
	
	MFC1_WARNING:BOOL;
	MFC1_Alarm:BOOL;
	
	MFC2_WARNING:BOOL;
	MFC2_Alarm:BOOL;
	
	MFC3_WARNING:BOOL;
	MFC3_Alarm:BOOL;
	
	MFC4_WARNING:BOOL;
	MFC4_Alarm:BOOL;
	
	MFC5_WARNING:BOOL;
	MFC5_Alarm:BOOL;
	
	MFC6_WARNING:BOOL;
	MFC6_Alarm:BOOL;
	
	MFC7_WARNING:BOOL;
	MFC7_Alarm:BOOL;
	
	MFC8_WARNING:BOOL;
	MFC8_Alarm:BOOL;
	
	MFC9_WARNING:BOOL;
	MFC9_Alarm:BOOL;
	
	WALL_TEMP_WARNING:BOOL;
	WALL_TEMP_Alarm:BOOL;
		
	LID_TEMP_WARNING:BOOL;
	LID_TEMP_Alarm:BOOL;
	
	STAGE_EDGE_TEMP_WARNING:BOOL;
	STAGE_EDGE_TEMP_Alarm:BOOL;
	
	STAGE_CENTER_TEMP_WARNING: BOOL;
	STAGE_CENTER_TEMP_ALARM: BOOL;
	
END_VAR
VAR
	STEP_TIME:TON;
	STEP_TIME_DONE:BOOL;
	
	COMPLETION:INT;
	
	//Tolerance
	TOL_PRESSURE_PERCENT:Tolerance;
	TOL_PRESSURE_VALUE_EN:BOOL;
	TOL_PRESSURE_PERCENT_EN:BOOL;
	
	TOL_MFC1_PERCENT:Tolerance;
	TOL_MFC2_PERCENT:Tolerance;
	TOL_MFC3_PERCENT:Tolerance;
	//TOL_MFC4_PERCENT:Tolerance;
	TOL_MFC5_PERCENT:Tolerance;
	TOL_MFC6_PERCENT:Tolerance;
	TOL_MFC7_PERCENT:Tolerance;
	//TOL_MFC8_PERCENT:Tolerance;
	//TOL_MFC9_PERCENT:Tolerance;
	TOL_MFC_VALUE_EN:BOOL;
	TOL_MFC_PERCENT_EN:BOOL;

	TOL_WALL_TEMP_PERCENT:Tolerance;

	TOL_LID_TEMP_PERCENT:Tolerance;

	TOL_STAGE_EDGE_TEMP_PERCENT:Tolerance;
	
	TOL_STAGE_CENTER_TEMP_PERCENT:Tolerance;
	TOL_HEATER_VALUE_EN:BOOL;
	TOL_HEATER_PERCENT_EN:BOOL;
	
	TON_STEP_TIME:TON;
	TON_STEP_TIME_EN:BOOL;
	
	WARNING_OCC:BOOL;
	ALARM_OCC:BOOL;
	
	i:INT;
	
	STABLE_DONE:BOOL;
	EN_TRIG:R_TRIG;
	TON_STABLE_PROCESS:TON;
	
	CHAMBER_TEMP_MIN_VALUE:REAL;
	STAGE_EDGE_TEMP_MIN_VALUE:REAL;
	STAGE_CENTER_TEMP_MIN_VALUE:REAL;
		
END_VAR

//NOT ENABLE
	IF NOT ENABLE 
		THEN
		i:=0;
		STEP_ERR:=FALSE;
		STEP_TIME_OUT:=FALSE;
		NEXTSTEP:=FALSE;
		TON_STEP_TIME_EN:=FALSE;
	END_IF;
	
//初始化
	EN_TRIG(CLK:= ENABLE, Q=> );
	IF EN_TRIG.Q OR NEXTSTEP_EN
		THEN
		i:=1;
		STEP_ERR:=FALSE;
		STEP_TIME_OUT:=FALSE;
		NEXTSTEP:=FALSE;
		TON_STEP_TIME_EN:=TRUE;
	END_IF;

	
//STEP开始时赋值
	IF  ENABLE AND NOT STEP_TIME_DONE
	THEN
	//APC
	IF 		STEP_DATA.LstUnit.Pressure.PressureUnitMode = 'Pressure' 
			THEN
			APC_PRESSURE:=STEP_DATA.LstUnit.Pressure.StartValue;
			APC_CONTROL_MODE:=5;
			ELSIF 	
			STEP_DATA.LstUnit.Pressure.PressureUnitMode = 'Position'	
			THEN
			APC_POSITION:=STEP_DATA.LstUnit.Pressure.StartValue;
			APC_CONTROL_MODE:=2;
	END_IF
	
	IF 		STEP_DATA.LstUnit.Pressure.ToleranceMode = 'Value' 
			THEN
			TOL_PRESSURE_VALUE_EN:=TRUE;
			TOL_PRESSURE_PERCENT_EN:=FALSE;
			ELSIF 	
			STEP_DATA.LstUnit.Pressure.ToleranceMode = 'Percent'	
			THEN
			TOL_PRESSURE_VALUE_EN:=FALSE;
			TOL_PRESSURE_PERCENT_EN:=TRUE;
	END_IF
	
	//MFC
	IF 		STEP_DATA.LstUnit.GAS.ToleranceMode = 'Value' 
			THEN
			TOL_MFC_VALUE_EN:=TRUE;
			TOL_MFC_PERCENT_EN:=FALSE;
			ELSIF 	
			STEP_DATA.LstUnit.GAS.ToleranceMode = 'Percent'	
			THEN
			TOL_MFC_VALUE_EN:=FALSE;
			TOL_MFC_PERCENT_EN:=TRUE;
	END_IF
	
	MFC1_SV:=INT_TO_REAL(STEP_DATA.LstUnit.GAS.Gas1);
	MFC2_SV:=INT_TO_REAL(STEP_DATA.LstUnit.GAS.Gas2);
	MFC3_SV:=INT_TO_REAL(STEP_DATA.LstUnit.GAS.Gas3);
	MFC4_SV:=INT_TO_REAL(STEP_DATA.LstUnit.GAS.Gas4);	
	MFC5_SV:=INT_TO_REAL(STEP_DATA.LstUnit.GAS.Gas5);
	MFC6_SV:=INT_TO_REAL(STEP_DATA.LstUnit.GAS.Gas6);
	MFC7_SV:=INT_TO_REAL(STEP_DATA.LstUnit.GAS.Gas7);
	MFC8_SV:=INT_TO_REAL(STEP_DATA.LstUnit.GAS.Gas8);	
	MFC9_SV:=INT_TO_REAL(STEP_DATA.LstUnit.GAS.Gas9);
	
	//HEATER
	IF 		STEP_DATA.LstUnit.Heater.ToleranceMode = 'Value' 
			THEN
			TOL_HEATER_VALUE_EN:=TRUE;
			TOL_HEATER_PERCENT_EN:=FALSE;
			ELSIF 	
			STEP_DATA.LstUnit.Heater.ToleranceMode = 'Percent'	
			THEN
			TOL_HEATER_VALUE_EN:=FALSE;
			TOL_HEATER_PERCENT_EN:=TRUE;
	END_IF
	
	WALL_TEMP:=INT_TO_REAL(STEP_DATA.LstUnit.Heater.WallTemp);
	LID_TEMP:=INT_TO_REAL(STEP_DATA.LstUnit.Heater.LidTemp);
	STAGE_EDGE_TEMP:= STEP_DATA.LstUnit.Heater.StageEdgeTemp*10;
	STAGE_CENTER_TEMP:= STEP_DATA.LstUnit.Heater.StageCenterTemp*10;	
	END_IF;

// Lifter
	GV.NDO.AV110 :=	STEP_DATA.Lifter_Up AND NOT STEP_DATA.Lifter_Down;
	GV.NDO.AV109 :=	FALSE;
//取最小值
		IF 
		GV.AI.Chamber_Temp1<=GV.AI.Chamber_Temp2 AND GV.AI.Chamber_Temp1<=GV.AI.Chamber_Temp3
		THEN 
		CHAMBER_TEMP_MIN_VALUE:=GV.AI.Chamber_Temp1;
		ELSIF 
		GV.AI.Chamber_Temp2<=GV.AI.Chamber_Temp1 AND GV.AI.Chamber_Temp2<=GV.AI.Chamber_Temp3
		THEN
		CHAMBER_TEMP_MIN_VALUE:=GV.AI.Chamber_Temp2;
		ELSIF
		GV.AI.Chamber_Temp3<=GV.AI.Chamber_Temp2 AND GV.AI.Chamber_Temp3<=GV.AI.Chamber_Temp1
		THEN
		CHAMBER_TEMP_MIN_VALUE:=GV.AI.Chamber_Temp3;
	END_IF
	
	IF 
		GV.AI.Stage_Temp1<=GV.AI.Stage_Temp3
		THEN 
		STAGE_EDGE_TEMP_MIN_VALUE:=GV.AI.Stage_Temp1;
		ELSE 
		STAGE_EDGE_TEMP_MIN_VALUE:=GV.AI.Stage_Temp3;
	END_IF
	
	IF 
		GV.AI.Stage_Temp2<=GV.AI.Stage_Temp4
		THEN 
		STAGE_CENTER_TEMP_MIN_VALUE:=GV.AI.Stage_Temp2;
		ELSE 
		STAGE_CENTER_TEMP_MIN_VALUE:=GV.AI.Stage_Temp4;
	END_IF

//Tolerance
	TOL_PRESSURE_PERCENT(
		ENABLE:= TOL_PRESSURE_PERCENT.SV>0	AND ENABLE,
		STEP_TYPE:=	STEP_DATA.Completion,
		STEP_TIME:=	STEP_DATA.StepTime+STEP_DATA.AddTime,
		TOL_V:= TOL_PRESSURE_VALUE_EN, 
		TOL_P:= TOL_PRESSURE_PERCENT_EN, 
		SV:= STEP_DATA.LstUnit.Pressure.StartValue, 
		PV:= GV.AI.	APC.ACTUAL_PRESSURE, 
		WARNING_RANGE:= STEP_DATA.LstUnit.Pressure.StartValueWarningRange, 
		ALARM_RANGE:= STEP_DATA.LstUnit.Pressure.StartValueAlarmRange, 
		DELAY_TIME:=STEP_DATA.LstUnit.Pressure.ToleranceDelayTime,
		RST	:=	Alarm_RST,
		STABLE_TIME := PMStableTime,
		STU_WARNING=> PRESSURE_WARNING, 
		STU_ALARM=> PRESSURE_ALARM, );

	TOL_MFC1_PERCENT(
		ENABLE:= TOL_MFC1_PERCENT.SV>0	AND ENABLE,
		STEP_TYPE:=	STEP_DATA.Completion,
		STEP_TIME:=	STEP_DATA.StepTime+STEP_DATA.AddTime,
		TOL_V:= TOL_MFC_VALUE_EN, 
		TOL_P:= TOL_MFC_PERCENT_EN, 
		SV:= STEP_DATA.LstUnit.GAS.Gas1, 
		PV:= GV.AI.MFC1_Flow, 
		WARNING_RANGE:= STEP_DATA.LstUnit.GAS.Gas1WarningRange, 
		ALARM_RANGE:= STEP_DATA.LstUnit.GAS.Gas1AlarmRange, 
		DELAY_TIME:=STEP_DATA.LstUnit.GAS.ToleranceDelayTime,
		RST	:=	Alarm_RST,
		STABLE_TIME := PMStableTime,
		STU_WARNING=> MFC1_WARNING, 
		STU_ALARM=> MFC1_Alarm, );
	
	TOL_MFC2_PERCENT(
		ENABLE:= TOL_MFC2_PERCENT.SV>0	AND ENABLE,
		STEP_TYPE:=	STEP_DATA.Completion,
		STEP_TIME:=	STEP_DATA.StepTime+STEP_DATA.AddTime,
		TOL_V:= TOL_MFC_VALUE_EN, 
		TOL_P:= TOL_MFC_PERCENT_EN, 
		SV:= STEP_DATA.LstUnit.GAS.Gas2, 
		PV:= GV.AI.MFC2_Flow,
		WARNING_RANGE:= STEP_DATA.LstUnit.GAS.Gas2WarningRange, 
		ALARM_RANGE:= STEP_DATA.LstUnit.GAS.Gas2AlarmRange,  
		DELAY_TIME:=STEP_DATA.LstUnit.GAS.ToleranceDelayTime,
		RST	:=	Alarm_RST,
		STABLE_TIME := PMStableTime,
		STU_WARNING=> MFC2_WARNING, 
		STU_ALARM=> MFC2_Alarm, );
	
	TOL_MFC3_PERCENT(
		ENABLE:= TOL_MFC3_PERCENT.SV>0	AND ENABLE,
		STEP_TYPE:=	STEP_DATA.Completion,
		STEP_TIME:=	STEP_DATA.StepTime+STEP_DATA.AddTime,
		TOL_V:= TOL_MFC_VALUE_EN, 
		TOL_P:= TOL_MFC_PERCENT_EN, 
		SV:= STEP_DATA.LstUnit.GAS.Gas3, 
		PV:= GV.AI.MFC3_Flow,
		WARNING_RANGE:= STEP_DATA.LstUnit.GAS.Gas3WarningRange, 
		ALARM_RANGE:= STEP_DATA.LstUnit.GAS.Gas3AlarmRange, 
		DELAY_TIME:=STEP_DATA.LstUnit.GAS.ToleranceDelayTime,
		RST	:=	Alarm_RST,
		STABLE_TIME := PMStableTime,
		STU_WARNING=> MFC3_WARNING, 
		STU_ALARM=> MFC3_Alarm, );
	
	
	TOL_MFC5_PERCENT(
		ENABLE:= TOL_MFC5_PERCENT.SV>0	AND ENABLE,
		STEP_TYPE:=	STEP_DATA.Completion,
		STEP_TIME:=	STEP_DATA.StepTime+STEP_DATA.AddTime,
		TOL_V:= TOL_MFC_VALUE_EN, 
		TOL_P:= TOL_MFC_PERCENT_EN, 
		SV:= STEP_DATA.LstUnit.GAS.Gas5, 
		PV:= GV.AI.MFC5_Flow,
		WARNING_RANGE:= STEP_DATA.LstUnit.GAS.Gas5WarningRange, 
		ALARM_RANGE:= STEP_DATA.LstUnit.GAS.Gas5AlarmRange, 
		DELAY_TIME:=STEP_DATA.LstUnit.GAS.ToleranceDelayTime,
		RST	:=	Alarm_RST, 
		STABLE_TIME := PMStableTime,
		STU_WARNING=> MFC5_WARNING, 
		STU_ALARM=> MFC5_Alarm, );
	
	TOL_MFC6_PERCENT(
		ENABLE:= TOL_MFC6_PERCENT.SV>0	AND ENABLE,
		STEP_TYPE:=	STEP_DATA.Completion,
		STEP_TIME:=	STEP_DATA.StepTime+STEP_DATA.AddTime,
		TOL_V:= TOL_MFC_VALUE_EN, 
		TOL_P:= TOL_MFC_PERCENT_EN, 
		SV:= STEP_DATA.LstUnit.GAS.Gas6, 
		PV:= GV.AI.MFC6_Flow,
		WARNING_RANGE:= STEP_DATA.LstUnit.GAS.Gas6WarningRange, 
		ALARM_RANGE:= STEP_DATA.LstUnit.GAS.Gas6AlarmRange, 
		DELAY_TIME:=STEP_DATA.LstUnit.GAS.ToleranceDelayTime,
		RST	:=	Alarm_RST,
		STABLE_TIME := PMStableTime,
		STU_WARNING=> MFC6_WARNING, 
		STU_ALARM=> MFC6_Alarm, );
	
	TOL_MFC7_PERCENT(
		ENABLE:= TOL_MFC7_PERCENT.SV>0	AND ENABLE,
		STEP_TYPE:=	STEP_DATA.Completion,
		STEP_TIME:=	STEP_DATA.StepTime+STEP_DATA.AddTime,
		TOL_V:= TOL_MFC_VALUE_EN, 
		TOL_P:= TOL_MFC_PERCENT_EN, 
		SV:= STEP_DATA.LstUnit.GAS.Gas7, 
		PV:= GV.AI.MFC7_Flow,
		WARNING_RANGE:= STEP_DATA.LstUnit.GAS.Gas7WarningRange, 
		ALARM_RANGE:= STEP_DATA.LstUnit.GAS.Gas7AlarmRange, 
		DELAY_TIME:=STEP_DATA.LstUnit.GAS.ToleranceDelayTime,
		RST	:=	Alarm_RST,
		STABLE_TIME := PMStableTime,
		STU_WARNING=> MFC7_WARNING, 
		STU_ALARM=> MFC7_Alarm, );

	TOL_WALL_TEMP_PERCENT(
		ENABLE:= ENABLE,
		STEP_TYPE:=	STEP_DATA.Completion,
		STEP_TIME:=	STEP_DATA.StepTime+STEP_DATA.AddTime,
		TOL_V:= TOL_HEATER_VALUE_EN, 
		TOL_P:= TOL_HEATER_PERCENT_EN, 
		SV:= STEP_DATA.LstUnit.Heater.WallTemp, 
		PV:= CHAMBER_TEMP_MIN_VALUE, 
		WARNING_RANGE:= STEP_DATA.LstUnit.Heater.WallTempWaningRange, 
		ALARM_RANGE:= STEP_DATA.LstUnit.Heater.WallTempAlarmRange, 
		DELAY_TIME:=STEP_DATA.LstUnit.Heater.ToleranceDelayTime,
		RST	:=	Alarm_RST,
		STABLE_TIME := PMStableTime,
		STU_WARNING=> WALL_TEMP_WARNING, 
		STU_ALARM=> WALL_TEMP_Alarm, );
	
	TOL_LID_TEMP_PERCENT(
		ENABLE:= ENABLE,
		STEP_TYPE:=	STEP_DATA.Completion,
		STEP_TIME:=	STEP_DATA.StepTime+STEP_DATA.AddTime,
		TOL_V:= TOL_HEATER_VALUE_EN, 
		TOL_P:= TOL_HEATER_PERCENT_EN,
		SV:= STEP_DATA.LstUnit.Heater.LidTemp, 
		PV:= GV.AI.	Lid_Temp, 
		WARNING_RANGE:= STEP_DATA.LstUnit.Heater.LidTempWaningRange, 
		ALARM_RANGE:= STEP_DATA.LstUnit.Heater.LidTempAlarmRange, 
		DELAY_TIME:=STEP_DATA.LstUnit.Heater.ToleranceDelayTime,
		RST	:=	Alarm_RST,
		STABLE_TIME := PMStableTime,
		STU_WARNING=> LID_TEMP_WARNING, 
		STU_ALARM=> LID_TEMP_Alarm, );
		
	
	TOL_STAGE_EDGE_TEMP_PERCENT(
		ENABLE:= ENABLE,
		STEP_TYPE:=	STEP_DATA.Completion,
		STEP_TIME:=	STEP_DATA.StepTime+STEP_DATA.AddTime,
		TOL_V:= TOL_HEATER_VALUE_EN, 
		TOL_P:= TOL_HEATER_PERCENT_EN,
		SV:= STEP_DATA.LstUnit.Heater.StageEdgeTemp, 
		PV:= STAGE_EDGE_TEMP_MIN_VALUE, 
		WARNING_RANGE:= STEP_DATA.LstUnit.Heater.StageEdgeTempWaningRange, 
		ALARM_RANGE:= STEP_DATA.LstUnit.Heater.StageEdgeTempAlarmRange, 
		DELAY_TIME:=STEP_DATA.LstUnit.Heater.ToleranceDelayTime,
		RST	:=	Alarm_RST,
		STABLE_TIME := PMStableTime,
		STU_WARNING=> STAGE_EDGE_TEMP_WARNING, 
		STU_ALARM=> STAGE_EDGE_TEMP_Alarm, );
	
	TOL_STAGE_CENTER_TEMP_PERCENT(
		ENABLE:= ENABLE,
		STEP_TYPE:=	STEP_DATA.Completion,
		STEP_TIME:=	STEP_DATA.StepTime+STEP_DATA.AddTime,
		TOL_V:= TOL_HEATER_VALUE_EN, 
		TOL_P:= TOL_HEATER_PERCENT_EN,
		SV:= STEP_DATA.LstUnit.Heater.StageCenterTemp, 
		PV:= STAGE_CENTER_TEMP_MIN_VALUE, 
		WARNING_RANGE:= STEP_DATA.LstUnit.Heater.StageCenterTempWaningRange, 
		ALARM_RANGE:= STEP_DATA.LstUnit.Heater.StageCenterTempAlarmRange,
		DELAY_TIME:=STEP_DATA.LstUnit.Heater.ToleranceDelayTime,
		RST	:=	Alarm_RST, 
		STABLE_TIME := PMStableTime,
		STU_WARNING=> STAGE_CENTER_TEMP_WARNING, 
		STU_ALARM=> STAGE_CENTER_TEMP_ALARM, );

		
		
		
//ALRAM & WARNING	
	WARNING_OCC:=  PRESSURE_WARNING 
				OR MFC1_WARNING OR MFC2_WARNING OR MFC3_WARNING OR MFC4_WARNING OR MFC5_WARNING
				OR MFC6_WARNING OR MFC7_WARNING OR MFC8_WARNING OR MFC9_WARNING 
				OR WALL_TEMP_WARNING OR LID_TEMP_WARNING OR STAGE_EDGE_TEMP_WARNING OR STAGE_CENTER_TEMP_WARNING;
	
	ALARM_OCC:=    PRESSURE_ALARM 				
				OR MFC1_ALARM OR MFC2_ALARM OR MFC3_ALARM OR MFC4_ALARM OR MFC5_ALARM
				OR MFC6_ALARM OR MFC7_ALARM OR MFC8_ALARM OR MFC9_ALARM 
				OR WALL_TEMP_ALARM OR LID_TEMP_ALARM OR STAGE_EDGE_TEMP_ALARM OR STAGE_CENTER_TEMP_ALARM;

//STABLE DONE
TON_STABLE_PROCESS(IN:= ENABLE, PT:= INT_TO_TIME(PMStableTime)*1000, Q=> , ET=> );

	STABLE_DONE:=	TOL_PRESSURE_PERCENT.STABLE_DONE 
				AND TOL_MFC1_PERCENT.STABLE_DONE 
				AND TOL_MFC2_PERCENT.STABLE_DONE 
				AND TOL_MFC3_PERCENT.STABLE_DONE 
				AND TOL_MFC5_PERCENT.STABLE_DONE 			 
				AND TOL_MFC6_PERCENT.STABLE_DONE 
				AND TOL_MFC7_PERCENT.STABLE_DONE
				AND TOL_WALL_TEMP_PERCENT.STABLE_DONE
				AND TOL_LID_TEMP_PERCENT.STABLE_DONE
				AND TOL_STAGE_EDGE_TEMP_PERCENT.STABLE_DONE
				AND TOL_STAGE_CENTER_TEMP_PERCENT.STABLE_DONE
				AND TON_STABLE_PROCESS.Q;

//STEP流程	
	CASE i OF
	1:	IF STEP_DATA.Completion='Stable'
			THEN
			i:= 10;
			ELSIF STEP_DATA.Completion='Time'
			THEN
			i:= 20;
		END_IF
	
		//STABLE
	10:	IF 	STABLE_DONE 
			THEN i:=100; 
		END_IF;
			
		//TIME
	20:	IF 	ALARM_OCC 
			THEN i:=50; 
			ELSE i:=21;
		END_IF;	
		
	21:	IF 	STEP_TIME_DONE 
			THEN i:= 100;		
			ELSE i:= 20;	
		END_IF;
		
		//ALARM CONDITION
	50:	STEP_ERR:=TRUE;
		TON_STEP_TIME_EN:=FALSE;
	
		//TIME OUT
	51: STEP_TIME_OUT:=TRUE;
		TON_STEP_TIME_EN:=FALSE;
		
		//FINISHED
	100:	NEXTSTEP:=TRUE;
		TON_STEP_TIME_EN:=FALSE;	
	END_CASE;	
	
//PROCESS TIME
	STEP_TIME(IN:= TON_STEP_TIME_EN, PT:= INT_TO_TIME(STEP_DATA.StepTime+STEP_DATA.AddTime)*1000, Q=> STEP_TIME_DONE, ET=> );

END_FUNCTION_BLOCK

// ---- POUs/FB/Tolerance.TcPOU
FUNCTION_BLOCK Tolerance
VAR_INPUT
	ENABLE:BOOL;
	STEP_TYPE:STRING;
	STEP_TIME:INT;
	TOL_V:BOOL;
	TOL_P:BOOL;
	SV:INT;
	PV:REAL;
	WARNING_RANGE:INT;
	ALARM_RANGE:INT;
	DELAY_TIME:INT;
	STABLE_TIME:INT;
	RST:BOOL;
END_VAR
VAR_OUTPUT
	STU_WARNING:BOOL;
	
	STU_ALARM:BOOL;
	
	//STU_TIMEOUT:BOOL;
	STABLE_DONE:BOOL;
END_VAR
VAR
	SV_SUB_WARNING_RANGE:INT;
	SV_ADD_WARNING_RANGE:INT;
	SV_DIV_WARNING_RANGE:INT;
	SV_MUL_WARNING_RANGE:INT;
	
	SV_SUB_ALARM_RANGE:INT;
	SV_ADD_ALARM_RANGE:INT;
	SV_DIV_ALARM_RANGE:INT;
	SV_MUL_ALARM_RANGE:INT;
	
	STU_WARNING_V:BOOL;
	STU_WARNING_P:BOOL;
	
	STU_ALARM_V:BOOL;
	STU_ALARM_P:BOOL;
	
	TON_DELAY_TIME:TON;
	TON_DELAY_TIME_PT:INT;
	
	TON_ALARM_P		:TON;
	TON_ALARM_V		:TON;
	TON_WARNING_P	:TON;
	TON_WARNING_V	:TON;
	TON_STABLE		:TON;
	
	TON_STABLE_IN	:BOOL;
END_VAR

//初始化
IF NOT ENABLE OR RST
	THEN 
	
	STU_WARNING:=FALSE;
	
	STU_ALARM:=FALSE;
	
	STU_WARNING_P:=FALSE;
	STU_ALARM_P:=FALSE;
	
	STU_WARNING_V:=FALSE;
	STU_ALARM_V:=FALSE;
	STABLE_DONE:=FALSE;
	TON_STABLE_IN:=FALSE;
		
END_IF;
IF NOT TOL_P
	THEN 
	STU_WARNING_P:=FALSE;
	STU_ALARM_P:=FALSE;
END_IF;

IF NOT TOL_V
	THEN
	STU_WARNING_V:=FALSE;
	STU_ALARM_V:=FALSE;
END_IF;

IF NOT ENABLE AND (STEP_TYPE =	'Stable')
	THEN
	STABLE_DONE:=TRUE;
END_IF

//RANGE计算
	SV_SUB_WARNING_RANGE:=SV-WARNING_RANGE;
	SV_ADD_WARNING_RANGE:=SV+WARNING_RANGE;
	SV_DIV_WARNING_RANGE:=SV*(100-WARNING_RANGE)/100;
	SV_MUL_WARNING_RANGE:=SV*(100+WARNING_RANGE)/100;
	
	SV_SUB_ALARM_RANGE:=SV-ALARM_RANGE;
	SV_ADD_ALARM_RANGE:=SV+ALARM_RANGE;
	SV_DIV_ALARM_RANGE:=SV*(100-ALARM_RANGE)/100;
	SV_MUL_ALARM_RANGE:=SV*(100+ALARM_RANGE)/100;

//RANGE判断	
TON_WARNING_P(
			IN:= TOL_P AND (PV<=SV_DIV_WARNING_RANGE OR PV>=SV_MUL_WARNING_RANGE)AND NOT RST,
			PT:= T#200MS, 
			Q=> STU_WARNING_P, 
			ET=> );	
TON_WARNING_V(
			IN:= TOL_V AND (PV<=SV_SUB_WARNING_RANGE OR PV>=SV_ADD_WARNING_RANGE)AND NOT RST	, 
			PT:= T#200MS, 
			Q=> STU_WARNING_V, 
			ET=> );
TON_ALARM_P(
			IN:= TOL_P AND (PV<=SV_DIV_ALARM_RANGE OR PV>=SV_MUL_ALARM_RANGE)AND NOT RST, 
			PT:= T#200MS, 
			Q=> STU_ALARM_P, 
			ET=> );
TON_ALARM_V(
			IN:= TOL_V AND (PV<=SV_SUB_ALARM_RANGE OR PV>=SV_ADD_ALARM_RANGE)AND NOT RST, 
			PT:= T#200MS, 
			Q=> STU_ALARM_V, 
			ET=> );
			
IF ENABLE
	THEN	
	//TIME MODE
	IF STEP_TYPE =	'Time'
		THEN
		TON_DELAY_TIME_PT:=DELAY_TIME;
		STU_WARNING:=(STU_WARNING_V OR STU_WARNING_P) AND TON_DELAY_TIME.Q;
		IF (STU_ALARM_V OR STU_ALARM_P) AND TON_DELAY_TIME.Q
		THEN
		STU_ALARM:=TRUE;
		END_IF
	END_IF;	
	
	//Stable MODE
	IF STEP_TYPE =	'Stable'
		THEN
		IF TON_WARNING_P.IN OR TON_WARNING_V.IN
		THEN
		STABLE_DONE:=FALSE;
		TON_STABLE_IN:=FALSE;
		ELSE
		TON_STABLE_IN:=TRUE;			
		END_IF;	
		IF TON_STABLE.Q 
		THEN
		STABLE_DONE:=TRUE;	
		END_IF
	END_IF

END_IF;


//TON
	TON_DELAY_TIME(IN:= ENABLE AND NOT RST, PT:= INT_TO_TIME(TON_DELAY_TIME_PT)*1000, Q=> , ET=> );

	TON_STABLE(IN:=TON_STABLE_IN,	PT:= INT_TO_TIME(STABLE_TIME)*1000, Q=> , ET=> );

END_FUNCTION_BLOCK

// ---- POUs/PRG/IO_EXCHANGE.TcPOU
PROGRAM IO_EXCHANGE
VAR
END_VAR

PLC_TO_UI();
UI_TO_PLC();

//************************HW-IO******************************************
//C02
		GV.NDI.	AV101_OPEN	:=	ECC.	CHAMBER_IN.		C02	[	1	];	//	AV101OPEN
		GV.NDI.	AV101_CLOSE	:=	ECC.	CHAMBER_IN.		C02	[	2	];	//	AV101CLOSE
		GV.NDI.	AV102_OPEN	:=	ECC.	CHAMBER_IN.		C02	[	3	];	//	AV102OPEN
	//	GV.NDI.	AV102_CLOSE	:=	ECC.	CHAMBER_IN.		C02	[	4	];	//	AV102CLOSE
	//	GV.NDI.	AV103_OPEN	:=									
	//	GV.NDI.	AV103_CLOSE	:=									
		GV.NDI.	AV104_OPEN	:=	ECC.	CHAMBER_IN.		C02	[	5	];	//	AV104OPEN
	//	GV.NDI.	AV104_CLOSE	:=	ECC.	CHAMBER_IN.		C02	[	6	];	//	AV104CLOSE
		GV.NDI.	AV105_OPEN	:=	ECC.	CHAMBER_IN.		C02	[	7	];	//	AV105OPEN
	//	GV.NDI.	AV105_CLOSE	:=	ECC.	CHAMBER_IN.		C02	[	8	];	//	AV105CLOSE
		GV.NDI.	AV106_OPEN	:=	ECC.	CHAMBER_IN.		C02	[	9	];	//	AV106OPEN
		GV.NDI.	AV106_CLOSE	:=	ECC.	CHAMBER_IN.		C02	[	10	];	//	AV106CLOSE
		GV.NDI.	CY1_OPEN	:=	ECC.	CHAMBER_IN.		C02	[	11	];	//	CY1 UP
		GV.NDI.	CY1_CLOSE	:=	ECC.	CHAMBER_IN.		C02	[	12	];	//	CY1 DOWN
		GV.NDI.	Lift_Pin_Middle1	:=	ECC.	CHAMBER_IN.		C02	[	13	];	//	CY1 Middle
		GV.NDI.	CY2_OPEN	:=	ECC.	CHAMBER_IN.		C02	[	14	];	//	CY2 UP						
		GV.NDI.	CY2_CLOSE	:=	ECC.	CHAMBER_IN.		C02	[	15	];	//	CY2 DOWN
		GV.NDI.	Lift_Pin_Middle2	:=	ECC.	CHAMBER_IN.		C02	[	16	];	//	CY2 Middle								

//C03																											
		//					:=	ECC.	CHAMBER_IN.		C03	[	1	];		
		//					:=	ECC.	CHAMBER_IN.		C03	[	2	];		
		GV.NDI.FL02B2		:=	ECC.	CHAMBER_IN.		C03	[	3	];		
		//					:=	ECC.	CHAMBER_IN.		C03	[	4	];		
		GV.NDI.FL03B2		:=	ECC.	CHAMBER_IN.		C03	[	5	];		
		//					:=	ECC.	CHAMBER_IN.		C03	[	6	];		
		GV.NDI.FL04B2		:=	ECC.	CHAMBER_IN.		C03	[	7	];		
		//					:=	ECC.	CHAMBER_IN.		C03	[	8	];		
					//		:=	ECC.	CHAMBER_IN.		C03	[	9	];		
		GV.NDI.CDA_OK		:=	ECC.	CHAMBER_IN.		C03	[	10	];		
					//		:=	ECC.	CHAMBER_IN.		C03	[	11	];		
					//		:=	ECC.	CHAMBER_IN.		C03	[	12	];		
					//		:=	ECC.	CHAMBER_IN.		C03	[	13	];		
					//		:=	ECC.	CHAMBER_IN.		C03	[	14	];		
		GV.NDI.	GV1_OPEN	:=	ECC.	CHAMBER_IN.		C03	[	15	];	//	GV1OPEN
		GV.NDI.	GV1_CLOSE	:=	ECC.	CHAMBER_IN.		C03	[	16	];	//	GV1CLOSE

//C04
		GV.AI.	APC_Temp				:=			INT_TO_REAL(	ECC.	CHAMBER_IN.	C04	[	1	])/10;	//	SSR1	钟摆阀(E01)	TC01
		GV.AI.	Lid_Temp				:=			INT_TO_REAL(	ECC.	CHAMBER_IN.	C04	[	2	])/10;	//	SSR2	LID HEATER控温TC	(E02-E05) TC02
		GV.AI.	Lid_Temp_Monitor1		:=			INT_TO_REAL(	ECC.	CHAMBER_IN.	C04	[	3	])/10;	//	LID HEATER TC monitor	TC03
		GV.AI.	Lid_Temp_Monitor2		:=			INT_TO_REAL(	ECC.	CHAMBER_IN.	C04	[	4	])/10;	//	LID HEATER TC monitor	TC04
		GV.AI.	Chamber_Temp1			:=			INT_TO_REAL(	ECC.	CHAMBER_IN.	C04	[	5	])/10;	//	SSR3	CHAMBER HEATER 控温TC (E06,E07)	TC05
		GV.AI.	Chamber_Temp2			:=			INT_TO_REAL(	ECC.	CHAMBER_IN.	C04	[	6	])/10;	//	SSR4	CHAMBER HEATER 控温TC (E08,E09,E12,E13)	TC06
		GV.AI.	Chamber_Temp3			:=			INT_TO_REAL(	ECC.	CHAMBER_IN.	C04	[	7	])/10;	//	SSR5	CHAMBER HEATER 控温TC (E10,E11)			TC07
		GV.AI.	Stage_Temp1				:=			INT_TO_REAL(	ECC.	CHAMBER_IN.	C04	[	8	])/10;	//	CHILLER控温用(左侧内)	TC08

//C05		
		GV.AI.	Stage_Temp2				:=			INT_TO_REAL(	ECC.	CHAMBER_IN.	C05	[	1	])/10;	//	CHILLER控温用(左侧外)	TC09 
		GV.AI.	Stage_Temp3				:=			INT_TO_REAL(	ECC.	CHAMBER_IN.	C05	[	2	])/10;	//	CHILLER控温用(右侧内)	TC10
		GV.AI.	Stage_Temp4				:=			INT_TO_REAL(	ECC.	CHAMBER_IN.	C05	[	3	])/10;	//	CHILLER控温用(右侧外)	TC11
		GV.AI.	Chamber_Temp_Monitor	:=			INT_TO_REAL(	ECC.	CHAMBER_IN.	C05	[	4	])/10;	//	腔体底部监控用
		GV.AI.	Gate_Valve_Temp			:=			INT_TO_REAL(	ECC.	CHAMBER_IN.	C05	[	5	])/10;	//	SSR18	GATE VALVE控温用	
		GV.AI.	Gate_Valve_Temp_Monitor	:=			INT_TO_REAL(	ECC.	CHAMBER_IN.	C05	[	6	])/10;	//	GATE VALVE监控
										//			INT_TO_REAL(	ECC.	CHAMBER_IN.	C05	[	7	])/10;	//	
										//			INT_TO_REAL(	ECC.	CHAMBER_IN.	C05	[	8	])/10;	//	

//C06							
										//							ECC.	CHAMBER_IN.	C06	[	1	]);
										//							ECC.	CHAMBER_IN.	C06	[	2	]);
										//							ECC.	CHAMBER_IN.	C06	[	3	]);
										//							ECC.	CHAMBER_IN.	C06	[	4	]);

							
//C07											
		ECC.	CHAMBER_OUT.	C07	[	1	]	:=	TRUE;//GV_IL.TMP_PW_EN;//GV.TURBO_PUMP_POWER_ON							;	
		ECC.	CHAMBER_OUT.	C07	[	2	]	:=	GV_IL.HTR_APC_EN;//GV.PENDULUM_VALVE_HEATER_POWER_ON				;	
		ECC.	CHAMBER_OUT.	C07	[	3	]	:=	GV_IL.HTR_LID_EN;//GV.LID_HEATER_POWER_ON							;	
		ECC.	CHAMBER_OUT.	C07	[	4	]	:=	GV_IL.HTR_CHAMBER_EN;//GV.CHAMBER_HEATER_POWER_ON						;	
		ECC.	CHAMBER_OUT.	C07	[	5	]	:=	GV_IL.HTR_GAS_BOX_EN;//GV.IGS_HEATER_POWER_ON							;	
		ECC.	CHAMBER_OUT.	C07	[	6	]	:=	GV_IL.HTR_GAS_BOX_EN;//GV.TAPE_HEATER_POWER_ON							;	
		ECC.	CHAMBER_OUT.	C07	[	7	]	:=	GV_IL.HTR_FORLINE_EN;//GV.FORELINE_HEATER_POWER_ON						;	
		ECC.	CHAMBER_OUT.	C07	[	8	]	:=	GV_IL.HTR_GATE_VALVE_EN;//GV.GATE_VALVE_HEATER_POWER_ON					;	
	//	ECC.	CHAMBER_OUT.	C07	[	9	]	:=			;	
	//	ECC.	CHAMBER_OUT.	C07	[	10	]	:=			;	
	//	ECC.	CHAMBER_OUT.	C07	[	11	]	:=			;	
	//	ECC.	CHAMBER_OUT.	C07	[	12	]	:=			;	
	//	ECC.	CHAMBER_OUT.	C07	[	13	]	:=			;	
	//	ECC.	CHAMBER_OUT.	C07	[	14	]	:=			;	
	//	ECC.	CHAMBER_OUT.	C07	[	15	]	:=			;	
	//	ECC.	CHAMBER_OUT.	C07	[	16	]	:=			;	
												
//C08												
		ECC.	CHAMBER_OUT.	C08	[	1	]	:=	GV.LID_HEATER_SSR_ON[1]		;	//SSR02
	//	ECC.	CHAMBER_OUT.	C08	[	2	]	:=	GV.LID_HEATER_SSR_ON[2]		;	//SSR02
	//	ECC.	CHAMBER_OUT.	C08	[	3	]	:=	GV.LID_HEATER_SSR_ON[3]		;	//SSR02
	//	ECC.	CHAMBER_OUT.	C08	[	4	]	:=	GV.LID_HEATER_SSR_ON[4]		;	//SSR02
	//	ECC.	CHAMBER_OUT.	C08	[	5	]	:=								;	
	//	ECC.	CHAMBER_OUT.	C08	[	6	]	:=								;	
		ECC.	CHAMBER_OUT.	C08	[	7	]	:=	GV.CHAMBER_HEATER_SSR_ON[1]	;	//SSR03
		ECC.	CHAMBER_OUT.	C08	[	8	]	:=	GV.CHAMBER_HEATER_SSR_ON[2]	;	//SSR03
		ECC.	CHAMBER_OUT.	C08	[	9	]	:=	GV.CHAMBER_HEATER_SSR_ON[3]	;	//SSR04	
	//	ECC.	CHAMBER_OUT.	C08	[	10	]	:=	
		ECC.	CHAMBER_OUT.	C08	[	11	]	:=	GV.CHAMBER_HEATER_SSR_ON[4];	//SSR05
	//	ECC.	CHAMBER_OUT.	C08	[	12	]	:=	
		ECC.	CHAMBER_OUT.	C08	[	13	]	:=	
	//	ECC.	CHAMBER_OUT.	C08	[	14	]	:=	
	//	ECC.	CHAMBER_OUT.	C08	[	15	]	:=								;	
	//	ECC.	CHAMBER_OUT.	C08	[	16	]	:=								;	
												
//C09												
		ECC.	CHAMBER_OUT.	C09	[	1	]	:=	GV.FORELINE_HEATER_SSR_ON[1];	//SSR6	AV102
		ECC.	CHAMBER_OUT.	C09	[	2	]	:=	GV.FORELINE_HEATER_SSR_ON[2];	//SSR7	AV101
		ECC.	CHAMBER_OUT.	C09	[	3	]	:=	GV.FORELINE_HEATER_SSR_ON[3];	//SSR8	AV106
		ECC.	CHAMBER_OUT.	C09	[	4	]	:=	GV.FORELINE_HEATER_SSR_ON[4];	//SSR9	BA01
	//	ECC.	CHAMBER_OUT.	C09	[	5	]	:=								;	
	//	ECC.	CHAMBER_OUT.	C09	[	6	]	:=								;	
		ECC.	CHAMBER_OUT.	C09	[	7	]	:=	GV.GATE_VALVE_SSR_ON		;	//SSR18
	//	ECC.	CHAMBER_OUT.	C09	[	8	]	:=								;	
		ECC.	CHAMBER_OUT.	C09	[	9	]	:=	GV.PEN_VALVE_HEATER_SSR_ON	;	//SSR01
	//	ECC.	CHAMBER_OUT.	C09	[	10	]	:=								;	
		ECC.	CHAMBER_OUT.	C09	[	11	]	:=	GV.FORELINE_HEATER_SSR_ON[5];	//SSR10	VG103
		ECC.	CHAMBER_OUT.	C09	[	12	]	:=	GV.FORELINE_HEATER_SSR_ON[6];	//SSR11	EXHAUST1-6
		ECC.	CHAMBER_OUT.	C09	[	13	]	:=	GV.FORELINE_HEATER_SSR_ON[7];	//SSR12	EXHAUST7-8
		ECC.	CHAMBER_OUT.	C09	[	14	]	:=	GV.FORELINE_HEATER_SSR_ON[8];	//SSR13	
	//	ECC.	CHAMBER_OUT.	C09	[	15	]	:=								;	
	//	ECC.	CHAMBER_OUT.	C09	[	16	]	:=								;	
		
(*		
//C11
		GV.NDI.	Lid_Closed			:=		ECC.	CHAMBER_IN.		C11	[	1	];
		GV.NDI.	PS10_L_ALM			:=		ECC.	CHAMBER_IN.		C11	[	2	];
		GV.NDI.	PS10_L_ALM			:=		ECC.	CHAMBER_IN.		C11	[	3	];
		GV.NDI.	PS11_H_ALM			:=		ECC.	CHAMBER_IN.		C11	[	4	];
		GV.NDI.	PS11_L_ALM			:=		ECC.	CHAMBER_IN.		C11	[	5	];
		GV.NDI.	PS12_H_ALM			:=		ECC.	CHAMBER_IN.		C11	[	6	];
		GV.NDI.	PS12_L_ALM			:=		ECC.	CHAMBER_IN.		C11	[	7	];
								//			ECC.	CHAMBER_IN.		C11	[	8	];
														
//C12														
		GV.NDI.	Water_Leak_Sensor01	:=		ECC.	CHAMBER_IN.		C12	[	1	];	//CHILLER1下方
		GV.NDI.	Water_Leak_Sensor02	:=		ECC.	CHAMBER_IN.		C12	[	2	];	//CHILLER2下方
		GV.NDI.	Water_Leak_Sensor03	:=		ECC.	CHAMBER_IN.		C12	[	3	];	//分子泵下方
		GV.NDI.	Water_Leak_Sensor04	:=		ECC.	CHAMBER_IN.		C12	[	4	];	//水盘
												
//C13												
		GV.NDI.	DP01_OUTPUT1		:=		ECC.	CHAMBER_IN.		C13	[	1	];	//酸排压差检测
		GV.NDI.	DP01_OUTPUT2		:=		ECC.	CHAMBER_IN.		C13	[	2	];	//酸排压差检测
							//		:=		ECC.	CHAMBER_IN.		C13	[	3	];
							//		:=		ECC.	CHAMBER_IN.		C13	[	4	];
//C14					
		ECC.CHAMBER_OUT.C14	[	1	]:=				GV.VT01_POWER_ON			;	
		ECC.CHAMBER_OUT.C14	[	2	]:=				GV.VT02_POWER_ON			;	
	//	ECC.CHAMBER_OUT.C14	[	3	]:=											;	
	//	ECC.CHAMBER_OUT.C14	[	4	]:=											;	
	*)												

//C15
		GV.AI.VG103_Pipe_Temp			:=			INT_TO_REAL(	ECC.	CHAMBER_IN.	C15	[	1	])/10;	//	TC-03-A	SSR10	AV104+VG103_PIPE_1+VG103_PIPE_2
		GV.AI.BA01_Temp					:=			INT_TO_REAL(	ECC.	CHAMBER_IN.	C15	[	2	])/10;	//	TC-06-A	SSR09	BA101腔体侧+BA101
		GV.AI.VG101_Pipe_Temp			:=			INT_TO_REAL(	ECC.	CHAMBER_IN.	C15	[	3	])/10;	//	TC-07-A	SSR13	PS10+PS11
		GV.AI.Exhaust1_6_Temp			:=			INT_TO_REAL(	ECC.	CHAMBER_IN.	C15	[	4	])/10;	//	TC-29-A	SSR11	EXHAUST OUT1-6
		GV.AI.AV102_Temp				:=			INT_TO_REAL(	ECC.	CHAMBER_IN.	C15	[	5	])/10;	//	TC-33-A	SSR06	AV102
		GV.AI.AV101_Temp				:=			INT_TO_REAL(	ECC.	CHAMBER_IN.	C15	[	6	])/10;	//	TC-36-A	SSR07	AV101
		GV.AI.Exhaust7_8_Temp			:=			INT_TO_REAL(	ECC.	CHAMBER_IN.	C15	[	7	])/10;	//	TC-37-A	SSR12	EXHAUST7+8
		GV.AI.AV106_Temp				:=			INT_TO_REAL(	ECC.	CHAMBER_IN.	C15	[	8	])/10;	//	TC-38-A	SSR08	AV106
	

//C32												
		GV.AI.PG_PS1_VALUE	:=	(ECC.	IGS_IN.		C32	[	1	]*115/32767-15)*6.895;		
		GV.AI.PG_PS2_VALUE	:=	(ECC.	IGS_IN.		C32	[	2	]*115/32767-15)*6.895;		
		GV.AI.PG_PS3_VALUE	:=	(ECC.	IGS_IN.		C32	[	3	]*115/32767-15)*6.895;		
		GV.AI.PG_PS4_VALUE	:=	(ECC.	IGS_IN.		C32	[	4	]*115/32767-15)*6.895;		
												
//C33												
		GV.AI.PG_PS5_VALUE	:=	(ECC.	IGS_IN.		C33	[	1	]*75/32767-15)*6.895;		
		GV.AI.PG_PS6_VALUE	:=	(ECC.	IGS_IN.		C33	[	2	]*115/32767-15)*6.895;		
		GV.AI.PG_PS7_VALUE	:=	(ECC.	IGS_IN.		C33	[	3	]*1015/32767-15)*6.895;		
		GV.AI.PG_PS8_VALUE	:=	(ECC.	IGS_IN.		C33	[	4	]*1015/32767-15)*6.895;		
												
//C34												
		GV.AI.PG_PS9_VALUE	:=	(ECC.	IGS_IN.		C34	[	1	]*1015/32767-15)*6.895;		
		GV.AI.PS1_VALUE		:=	(ECC.	IGS_IN.		C34	[	2	]*1015/32767-15)*6.895;		
		GV.AI.PS2_VALUE		:=	(ECC.	IGS_IN.		C34	[	3	]*1015/32767-15)*6.895;		
		GV.AI.MS1_VALUE		:=	(ECC.	IGS_IN.		C34	[	4	]*1015/32767-15)*6.895;		
												
//C35												
		GV.AI.GD01_VALUE	:=	ECC.	IGS_IN.		C35	[	1	];		
		GV.AI.GD02_VALUE	:=	ECC.	IGS_IN.		C35	[	2	];		
					//		:=	ECC.	IGS_IN.		C35	[	3	];		
					//		:=	ECC.	IGS_IN.		C35	[	4	];		
												
//C36												
		GV.NDI.	PG_PS1_Pressure_Switch_Up_Limit		:=	NOT ECC.	IGS_IN.		C36	[	1	];
		GV.NDI.	PG_PS1_Pressure_Switch_Down_Limit	:=	NOT ECC.	IGS_IN.		C36	[	2	];
		GV.NDI.	PG_PS2_Pressure_Switch_Up_Limit		:=	NOT ECC.	IGS_IN.		C36	[	3	];
		GV.NDI.	PG_PS2_Pressure_Switch_Down_Limit	:=	NOT ECC.	IGS_IN.		C36	[	4	];
		GV.NDI.	PG_PS3_Pressure_Switch_Up_Limit		:=	NOT ECC.	IGS_IN.		C36	[	5	];
		GV.NDI.	PG_PS3_Pressure_Switch_Down_Limit	:=	NOT ECC.	IGS_IN.		C36	[	6	];
		GV.NDI.	PG_PS4_Pressure_Switch_Up_Limit		:=	NOT ECC.	IGS_IN.		C36	[	7	];
		GV.NDI.	PG_PS4_Pressure_Switch_Down_Limit	:=	NOT ECC.	IGS_IN.		C36	[	8	];
		GV.NDI.	PG_PS5_Pressure_Switch_Up_Limit		:=	NOT ECC.	IGS_IN.		C36	[	9	];
		GV.NDI.	PG_PS5_Pressure_Switch_Down_Limit	:=	NOT ECC.	IGS_IN.		C36	[	10	];
		GV.NDI.	PG_PS6_Pressure_Switch_Up_Limit		:=	NOT ECC.	IGS_IN.		C36	[	11	];
		GV.NDI.	PG_PS6_Pressure_Switch_Down_Limit	:=	NOT ECC.	IGS_IN.		C36	[	12	];
		GV.NDI.	PG_PS7_Pressure_Switch_Up_Limit		:=	NOT ECC.	IGS_IN.		C36	[	13	];
		GV.NDI.	PG_PS7_Pressure_Switch_Down_Limit	:=	NOT ECC.	IGS_IN.		C36	[	14	];
		GV.NDI.	PG_PS8_Pressure_Switch_Up_Limit		:=	NOT ECC.	IGS_IN.		C36	[	15	];
		GV.NDI.	PG_PS8_Pressure_Switch_Down_Limit	:=	NOT ECC.	IGS_IN.		C36	[	16	];
											
//C37											
		GV.NDI.	PG_PS9_Pressure_Switch_Up_Limit		:=	ECC.	IGS_IN.		C37	[	1	];
		GV.NDI.	PG_PS9_Pressure_Switch_Down_Limit	:=	ECC.	IGS_IN.		C37	[	2	];
		GV.NDI.	MS1_Pressure_Switch_Up_Limit		:=	ECC.	IGS_IN.		C37	[	3	];
		GV.NDI.	MS1_Pressure_Switch_Down_Limit		:=	ECC.	IGS_IN.		C37	[	4	];//QDP33P
		GV.NDI.	PS1_Pressure_Switch					:=	ECC.	IGS_IN.		C37	[	5	];
		GV.NDI.	PS2_Pressure_Switch					:=	ECC.	IGS_IN.		C37	[	6	];
											//		:=	ECC.	IGS_IN.		C37	[	7	];
											//		:=	ECC.	IGS_IN.		C37	[	8	];
											//		:=	ECC.	IGS_IN.		C37	[	9	];
											//		:=	ECC.	IGS_IN.		C37	[	10	];
											//		:=	ECC.	IGS_IN.		C37	[	11	];
											//		:=	ECC.	IGS_IN.		C37	[	12	];
											//		:=	ECC.	IGS_IN.		C37	[	13	];
											//		:=	ECC.	IGS_IN.		C37	[	14	];
											//		:=	ECC.	IGS_IN.		C37	[	15	];
											//		:=	ECC.	IGS_IN.		C37	[	16	];

(*												
//C38												
		GV.NDI.	GD001_ALM1							:=	ECC.	IGS_IN.		C38	[	1	];
		GV.NDI.	GD001_ALM2							:=	ECC.	IGS_IN.		C38	[	2	];
		GV.NDI.	GD002_ALM1							:=	ECC.	IGS_IN.		C38	[	3	];
		GV.NDI.	GD002_ALM2							:=	ECC.	IGS_IN.		C38	[	4	];

//C39																						
		GV.NDI.	GD_FAULT							:=	ECC.	IGS_IN.		C39	[	1	];
		GV.NDI.	MS1_Pressure_Switch_Up_Limit		:=	ECC.	IGS_IN.		C39	[	2	];
		GV.NDI.	MS1_Pressure_Switch_Down_Limit		:=	ECC.	IGS_IN.		C39	[	3	];
					//								:=	ECC.	IGS_IN.		C39	[	4	];
*)
//C40																							
		GV.AI.Tape_Temp1	:=	INT_TO_REAL(	ECC.	IGS_IN.	C40	[	1	])/10;	//	IGS 加热带			TC31	E31
		GV.AI.Tape_Temp2	:=	INT_TO_REAL(	ECC.	IGS_IN.	C40	[	2	])/10;	//	IGS 加热带			TC32	E32
		GV.AI.IGS_Temp1		:=	INT_TO_REAL(	ECC.	IGS_IN.	C40	[	3	])/10;	//	IGS BLOCK HEATER	TC33	E33 绿+ 红-
		GV.AI.IGS_Temp2		:=	INT_TO_REAL(	ECC.	IGS_IN.	C40	[	4	])/10;	//	IGS BLOCK HEATER	TC34	E34 绿+ 红-
		GV.AI.Tape_Temp3	:=	INT_TO_REAL(	ECC.	IGS_IN.	C40	[	5	])/10;	//	IGS 加热带	TC35	E35
						//	:=	INT_TO_REAL(	ECC.	IGS_IN.	C40	[	6	])/10;	//	IGS BLOCK HEATER	TC36	E36
						//	:=	INT_TO_REAL(	ECC.	IGS_IN.	C40	[	7	])/10;		
						//	:=	INT_TO_REAL(	ECC.	IGS_IN.	C40	[	8	])/10;		

//C42												
		ECC.	IGS_OUT.	C42	[	1	]	:=	GV.TAPE_HEATER_SSR_ON[1]	;	//SSR31	GAS BOX内+外延1
		ECC.	IGS_OUT.	C42	[	2	]	:=	GV.TAPE_HEATER_SSR_ON[2]	;	//SSR32	外延2+外延3
		ECC.	IGS_OUT.	C42	[	3	]	:=	GV.TAPE_HEATER_SSR_ON[3]	;	//SSR33	阀体
	//	ECC.	IGS_OUT.	C42	[	4	]	:=			;	
	//	ECC.	IGS_OUT.	C42	[	5	]	:=			;	
	//	ECC.	IGS_OUT.	C42	[	6	]	:=			;	
		ECC.	IGS_OUT.	C42	[	7	]	:=	GV.IGS_HEATER_SSR_ON[1]		;	//SSR35
		ECC.	IGS_OUT.	C42	[	8	]	:=	GV.IGS_HEATER_SSR_ON[2]		;	//SSR36
	//	ECC.	IGS_OUT.	C42	[	9	]	:=			;	
	//	ECC.	IGS_OUT.	C42	[	10	]	:=			;	
	//	ECC.	IGS_OUT.	C42	[	11	]	:=			;	
	//	ECC.	IGS_OUT.	C42	[	12	]	:=			;	
	//	ECC.	IGS_OUT.	C42	[	13	]	:=			;	
	//	ECC.	IGS_OUT.	C42	[	14	]	:=			;	
	//	ECC.	IGS_OUT.	C42	[	15	]	:=			;	
	//	ECC.	IGS_OUT.	C42	[	16	]	:=			;	
(*
//C43																								
		ECC.	IGS_OUT.	C43	[	1	]	:=	TRUE;//GV.VT03_POWER_ON		;	
	//	ECC.	IGS_OUT.	C43	[	2	]	:=			;	
	//	ECC.	IGS_OUT.	C43	[	3	]	:=			;	
	//	ECC.	IGS_OUT.	C43	[	4	]	:=			;	
*)

//MFC									
		GV.AI.	MFC1_Flow					:=	ECC.	MFC_PV	[	1	].Flow_Reading	;
		ECC.	MFC_SV	[	1	].Flow_SP	:=	GV.AO.	MFC1_Flow_Setpoint	;
		ECC.	MFC_SV	[	1	].Ramp_Time	:=	REAL_TO_UDINT(GV.AO.	MFC1_Rate_Setpoint)	;
		GV.AI.	MFC2_Flow					:=	ECC.	MFC_PV	[	2	].Flow_Reading	;
		ECC.	MFC_SV	[	2	].Flow_SP	:=	GV.AO.	MFC2_Flow_Setpoint	;
		ECC.	MFC_SV	[	2	].Ramp_Time	:=	REAL_TO_UDINT(GV.AO.	MFC2_Rate_Setpoint)	;
		GV.AI.	MFC3_Flow					:=	ECC.	MFC_PV	[	3	].Flow_Reading	;
		ECC.	MFC_SV	[	3	].Flow_SP	:=	GV.AO.	MFC3_Flow_Setpoint	;
		ECC.	MFC_SV	[	3	].Ramp_Time	:=	REAL_TO_UDINT(GV.AO.	MFC3_Rate_Setpoint)	;
		GV.AI.	MFC4_Flow					:=	ECC.	MFC_PV	[	4	].Flow_Reading	;
		ECC.	MFC_SV	[	4	].Flow_SP	:=	GV.AO.	MFC4_Flow_Setpoint	;
		ECC.	MFC_SV	[	4	].Ramp_Time	:=	REAL_TO_UDINT(GV.AO.	MFC4_Rate_Setpoint)	;
		GV.AI.	MFC5_Flow					:=	ECC.	MFC_PV	[	5	].Flow_Reading	;
		ECC.	MFC_SV	[	5	].Flow_SP	:=	GV.AO.	MFC5_Flow_Setpoint	;
		ECC.	MFC_SV	[	5	].Ramp_Time	:=	REAL_TO_UDINT(GV.AO.	MFC5_Rate_Setpoint)	;
		GV.AI.	MFC6_Flow					:=	ECC.	MFC_PV	[	6	].Flow_Reading	;
		ECC.	MFC_SV	[	6	].Flow_SP	:=	GV.AO.	MFC6_Flow_Setpoint	;
		ECC.	MFC_SV	[	6	].Ramp_Time	:=	REAL_TO_UDINT(GV.AO.	MFC6_Rate_Setpoint)	;
		GV.AI.	MFC7_Flow					:=	ECC.	MFC_PV	[	7	].Flow_Reading	;
		ECC.	MFC_SV	[	7	].Flow_SP	:=	GV.AO.	MFC7_Flow_Setpoint	;
		ECC.	MFC_SV	[	7	].Ramp_Time	:=	REAL_TO_UDINT(GV.AO.	MFC7_Rate_Setpoint)	;
	//	GV.AI.	MFC8_PV						:=	ECC.	MFC_PV	[	8	].Flow_Reading	;
	//	ECC.	MFC_SV	[	1	].Flow_SP	:=	GV.AO.	MFC8_Flow_Setpoint	;
	//	ECC.	MFC_SV	[	1	].Ramp_Time	:=	REAL_TO_UDINT(GV.AO.	MFC8_Rate_Setpoint)	;
	//	GV.AI.	MFC9_PV						:=	ECC.	MFC_PV	[	9	].Flow_Reading	;
	//	ECC.	MFC_SV	[	1	].Flow_SP	:=	GV.AO.	MFC9_Flow_Setpoint	;
	//	ECC.	MFC_SV	[	1	].Ramp_Time	:=	REAL_TO_UDINT(GV.AO.	MFC9_Rate_Setpoint)	;


	
//EV
		ECC.	EV1.	A.	0	:=	GV.	NDO.	GV101C;	//GATE VALVE CLOSE
		ECC.	EV1.	A.	1	:=	GV.	NDO. 	GV101O;	//GATE VALVE OPEN
	//	ECC.	EV1.	A.	2	:=	GV.	NDO.	
	//	ECC.	EV1.	A.	3	:=	GV.	NDO.	
		ECC.	EV1.	A.	4	:=	GV.	NDO.	AV110;	//PIN UP
		ECC.	EV1.	A.	5	:=	GV.	NDO.	AV109;	//PIN MIDDLE
		ECC.	EV1.	A.	6	:=	GV.	NDO.	AV103	AND GV_IL.AV103_EN;
		ECC.	EV1.	A.	7	:=	GV.	NDO.	AV104 	AND GV_IL.AV104_EN;	//VG103关断阀
		ECC.	EV1.	B.	0	:=	GV.	NDO.	AV101	AND GV_IL.AV101_EN;	//预抽阀
		ECC.	EV1.	B.	1	:=	GV.	NDO.	AV102	AND GV_IL.AV102_EN;	//分子泵前级阀
	//	ECC.	EV1.	B.	2	:=	GV.	NDO.		;
	//	ECC.	EV1.	B.	3	:=	GV.	NDO.		;
	//	ECC.	EV1.	B.	4	:=	GV.	NDO.		;
	//	ECC.	EV1.	B.	5	:=	GV.	NDO.		;
	//	ECC.	EV1.	B.	6	:=	GV.	NDO.		;
	//	ECC.	EV1.	B.	7	:=	GV.	NDO.		;

										
										
	//	ECC.	EV2.	A.	0	:=	GV.	NDO.	AV201	;
	//	ECC.	EV2.	A.	1	:=	GV.	NDO.	AC101	;
	//	ECC.	EV2.	A.	2	:=	GV.	NDO.	AC102	;
	//	ECC.	EV2.	A.	3	:=	GV.	NDO.	AC103	;
		ECC.	EV2.	A.	4	:=	GV.	NDO.	AV201	;	//进水管关断阀
	//	ECC.	EV2.	A.	5	:=	GV.	NDO.	AV202	;	//
		ECC.	EV2.	A.	6	:=	GV.	NDO.	AV107	;	//钟摆阀动作使能保持阀
		ECC.	EV2.	A.	7	:=	GV.	NDO.	AV108	;	//分子泵purge
		ECC.	EV2.	B.	0	:=	GV.	NDO.	AV105	AND GV_IL.AV105_EN;	//BA101关断阀
		ECC.	EV2.	B.	1	:=	GV.	NDO.	AV106	AND GV_IL.AV106_EN;	//酸排关断阀
	//	ECC.	EV2.	B.	2	:=	GV.	NDO.		;
	//	ECC.	EV2.	B.	3	:=	GV.	NDO.		;
	//	ECC.	EV2.	B.	4	:=	GV.	NDO.		;
	//	ECC.	EV2.	B.	5	:=	GV.	NDO.		;
	//	ECC.	EV2.	B.	6	:=	GV.	NDO.		;
	//	ECC.	EV2.	B.	7	:=	GV.	NDO.		;
	
										
//gas box内										
		ECC.	EV3.	A.	0	:=	GV.	NDO.	AV1	;	//
		ECC.	EV3.	A.	1	:=	GV.	NDO.	AV2	;
		ECC.	EV3.	A.	2	:=	GV.	NDO.	AV3	;
		ECC.	EV3.	A.	3	:=	GV.	NDO.	AV4	;
		ECC.	EV3.	A.	4	:=	GV.	NDO.	AV6	;
		ECC.	EV3.	A.	5	:=	GV.	NDO.	AV7	;
		ECC.	EV3.	A.	6	:=	GV.	NDO.	AV9	;
		ECC.	EV3.	A.	7	:=	GV.	NDO.	AV10;
		ECC.	EV3.	B.	0	:=	GV.	NDO.	AV11;
		ECC.	EV3.	B.	1	:=	GV.	NDO.	AV12;
		ECC.	EV3.	B.	2	:=	GV.	NDO.	AV13;
		ECC.	EV3.	B.	3	:=	GV.	NDO.	AV14;
		ECC.	EV3.	B.	4	:=	GV.	NDO.	AV16;
		ECC.	EV3.	B.	5	:=	GV.	NDO.	AV17;
		ECC.	EV3.	B.	6	:=	GV.	NDO.	AV19;
		ECC.	EV3.	B.	7	:=	GV.	NDO.	AV20;
		ECC.	EV3.	C.	0	:=	GV.	NDO.	AV22;
		ECC.	EV3.	C.	1	:=	GV.	NDO.	AV23;
		ECC.	EV3.	C.	2	:=	GV.	NDO.	AV25;
		ECC.	EV3.	C.	3	:=	GV.	NDO.	AV26;
		ECC.	EV3.	C.	4	:=	GV.	NDO.	AV27;
	//	ECC.	EV3.	C.	5	:=	GV.	NDO.		;
	//	ECC.	EV3.	C.	6	:=	GV.	NDO.		;
	//	ECC.	EV3.	C.	7	:=	GV.	NDO.		;
	//	ECC.	EV3.	D.	0	:=	GV.	NDO.		;
	//	ECC.	EV3.	D.	1	:=	GV.	NDO.		;
	//	ECC.	EV3.	D.	2	:=	GV.	NDO.		;
	//	ECC.	EV3.	D.	3	:=	GV.	NDO.		;
	//	ECC.	EV3.	D.	4	:=	GV.	NDO.		;
	//	ECC.	EV3.	D.	5	:=	GV.	NDO.		;
	//	ECC.	EV3.	D.	6	:=	GV.	NDO.		;
	//	ECC.	EV3.	D.	7	:=	GV.	NDO.		;
										
										
//gas box内										
	//	ECC.	EV4.	A.	0	:=	GV.	NDO.	AV5	;
		ECC.	EV4.	A.	1	:=	GV.	NDO.	AV5	;
	//	ECC.	EV4.	A.	2	:=	GV.	NDO.	AV8	;
		ECC.	EV4.	A.	3	:=	GV.	NDO.	AV8	;
	//	ECC.	EV4.	A.	4	:=	GV.	NDO.	AV15	;
		ECC.	EV4.	A.	5	:=	GV.	NDO.	AV15	;
	//	ECC.	EV4.	A.	6	:=	GV.	NDO.	AV18	;
		ECC.	EV4.	A.	7	:=	GV.	NDO.	AV18	;
	//	ECC.	EV4.	B.	0	:=	GV.	NDO.	AV21	;
		ECC.	EV4.	B.	1	:=	GV.	NDO.	AV21	;
	//	ECC.	EV4.	B.	2	:=	GV.	NDO.	AV24	;
		ECC.	EV4.	B.	3	:=	GV.	NDO.	AV24	;
	//	ECC.	EV4.	B.	4	:=	GV.	NDO.		;
	//	ECC.	EV4.	B.	5	:=	GV.	NDO.		;
	//	ECC.	EV4.	B.	6	:=	GV.	NDO.		;
	//	ECC.	EV4.	B.	7	:=	GV.	NDO.		;
	




//APC											
	GV.	AI.	APC.	ACTUAL_PRESSURE					:=	ECC.			APC_PV.Actual_Pressure	*100/133.3*1000;	
	GV.	AI.	APC.	Pressure_Sensor_1				:=	ECC.			APC_PV.Pressure_Sensor_1	*100/133.3*1000;	
	GV.	AI.	APC.	Pressure_Sensor_2				:=	ECC.			APC_PV.Pressure_Sensor_2	*100/133.3*1000;	
	GV.	AI.	APC.	ACTUAL_POSITION					:=	ECC.			APC_PV.Actual_Position	;	
	GV.	AI.	APC.	CONTROL_MODE					:=	ECC.			APC_PV.Control_Mode	;	
	GV.	AI.	APC.	ERROR_NUMBER					:=	ECC.			APC_PV.ERROR_NUMBER	;	
	GV.	AI.	APC.	General_Status					:=	ECC.			APC_PV.General_Status	;	
	GV.	AI.	APC.	GENERAL_WARNINGS				:=	ECC.			APC_PV.General_Warnings	;	
	GV.	AI.	APC.	Extended_Warnings				:=	ECC.			APC_PV.Extended_Warnings	;	
	ECC.	APC_SV.Target_Pressure					:=	GV.	AO.	APC.	TARGET_PRESSURE*0.1333/100	;	
	ECC.	APC_SV.Target_Position					:=	GV.	AO.	APC.	TARGET_POSITION	;	
	ECC.	APC_SV.Pressure_Input_Digital_Sensor_1	:=	GV.	AO.	APC.	Pressure_Input_Digital_Sensor_1	;	//E-therCAT通讯传送过来的sensor值1
	ECC.	APC_SV.Pressure_Input_Digital_Sensor_2	:=	GV.	AO.	APC.	Pressure_Input_Digital_Sensor_2	;	//E-therCAT通讯传送过来的sensor值2
	ECC.	APC_SV.Control_Mode						:=	GV.	AO.	APC.	CONTROL_MODE	;	
	ECC.	APC_SV.General_Control_Setpoint			:=	GV.	AO.	APC.	General_Control_Setpoint	;		(*Bit 0: Zero 
										 																	  BIT 1: NOT used 
																											  Bit 2: Ping Pong TX Bit
																											  Bit 3: Not Used
																											  Bit 4: Access Mode Locked (VAT使用手册P72)
																											  Bit 5-15: Not Used
																											*)
	ECC.	APC_SV.Pressure_Ramp_Time				:=	GV.	AO.	APC.	PRESSURE_RAMP_TIME	;	
											
//TMP											
	GV.	AI.	TMP.	ROTATION						:=	ECC.			TURBO_PV.Rotation	;	//1:ROTATING,0:NOT ROTATING
	GV.	AI.	TMP.	NORMAL							:=	ECC.			TURBO_PV.Normal	;		//1:NORMAL,0:UNNORMAL
	GV.	AI.	TMP.	ACCELERATION					:=	ECC.			TURBO_PV.Acceleration	;	
	GV.	AI.	TMP.	Deceleration_Includes_Braking	:=	ECC.			TURBO_PV.Deceleration_Includes_Braking	;	
	GV.	AI.	TMP.	REMOTE_LOCAL					:=	ECC.			TURBO_PV.Remote_Local	;	//1:LOCAL.E-CAT CONTROL DISABLED,0:REMOTE.E-CAT CONTROL ENABLED
	GV.	AI.	TMP.	Turbo_Low_Speed					:=	ECC.			TURBO_PV.Turbo_Low_Speed	;	
	GV.	AI.	TMP.	ALARM							:=	NOT ECC.		TURBO_PV.Alarm	;	
	GV.	AI.	TMP.	WARNING							:=	NOT ECC.		TURBO_PV.Warning	;	
	GV.	AI.	TMP.	Turbo_Speed						:=	REAL_TO_INT(ECC.TURBO_PV.Turbo_Speed*32.5	);	//0.1[%],1000(100.0%):RATED SPEED,0(0.0%):NO RATATION
	GV.	AI.	TMP.	Turbo_Current					:=	ECC.			TURBO_PV.Turbo_Current	;	//0.1A
	GV.	AI.	TMP.	Turbo_pump_temperature			:=	ECC.			TURBO_PV.Turbo_pump_temperature	;	//1[℃]
	//GV.	AI.	TMP.	VibrationH					:=	ECC.			TURBO_PV.VibrationH	;	
	//GV.	AI.	TMP.	VibrationB					:=	ECC.			TURBO_PV.VibrationB	;	
	//GV.	AI.	TMP.	VibrationZ					:=	ECC.			TURBO_PV.VibrationZ	;	
	ECC.			TURBO_SV.Turbo_Start_Stop		:=	GV.	AO.	TMP.	Turbo_Start_Stop	;	//1:START,0:STOP
	ECC.			TURBO_SV.Turbo_Reset_Alarm		:=	GV.	AO.	TMP.	Turbo_Reset_Alarm	;	//1:RESET ALARM,0:NO ACTION
	ECC.			TURBO_SV.Turbo_Low_Speed		:=	GV.	AO.	TMP.	Turbo_Low_Speed	;		//1:LOW SPEED MODE ON,0:OFF
	
//PG PS
	GV.	AI.	VG103_PV		:=GV.AI.VG103_Pressure		:=	ECC.	VG103_PV.Sensor_Value1	/133.3	*1000					;
											
	GV.	AI.	VG101_PV		:=GV.AI.VG101_Pressure		:=	ECC.	VG101_PV.Sensor_Value1	/133.3	*1000					;
											
	GV.	AI.	VG102_PV		:=GV.AI.VG102_Pressure		:=	ECC.	VG102_PV.Sensor_Value1	/133.3	*1000					;
											
	GV.	AI.	BA1_PV			:=GV.AI.BA1_Pressure		:=	ECC.	BA1_PV.Combination_Gauge_Active_Value_Module_1	/133.3	;
											
	GV.	AI.	VG104_PV		:=GV.AI.VG104_Pressure		:=	ECC.	VG104_PV.Sensor_Value1	/133.3	*1000					;

//CHILLER
	GV.	AI.CHILLER1_TEMP_PV						:=	UINT_TO_REAL(	ECC.	CHILLER1_PV.Module2_Word[1]	)/10	;	//有符号整数，-50.0 to 150.0℃ = FE0Ch to 05DCh ,0.1℃/dig
	GV.	AI.CHILLER1_DI_PV						:=	UINT_TO_REAL(	ECC.	CHILLER1_PV.Module2_Word[2]	)	;	//0.0 to 20.0M-ohm = 0000h to 00C8h ,0.1M-ohm/dig
	GV.	AI.CHILLER1_FLOW_PV						:=	UINT_TO_REAL(	ECC.	CHILLER1_PV.Module2_Word[3]	)	;	//0.0 to 150.0LPM = 0000h to 05DCh 0.1LPM/dig
	GV.	AI.CHILLER1_PRESS_PV					:=	UINT_TO_REAL(	ECC.	CHILLER1_PV.Module2_Word[4]	)	;	//0.00 to 2.00MPa = 0h to C8h 0.01MP/dig
	ECC.CHILLER1_SV.Module2_Word[1]				:=	REAL_TO_UINT(	GV.AO.Chiller1_On					)	;	//CHILLER1 ON
	ECC.CHILLER1_SV.Module2_Word[2]				:=	REAL_TO_UINT(	GV.	AO.Chiller_Temp1_SV	*10			)	;	// -20.0 to 90.0℃= FF38h to 384h 0.1℃/dig
	ECC.CHILLER1_SV.Module2_Word[3]				:=	INT_TO_UINT(ECC.	CHAMBER_IN.	C04	[	8	]		)	;	// Stage温度反馈给chiller
	
	GV.	AI.CHILLER2_TEMP_PV						:=	UINT_TO_REAL(	ECC.	CHILLER2_PV.Module2_Word[1]	)/10	;	//有符号整数，-50.0 to 150.0℃ = FE0Ch to 05DCh ,0.1℃/dig
	GV.	AI.CHILLER2_DI_PV						:=	UINT_TO_REAL(	ECC.	CHILLER2_PV.Module2_Word[2]	)	;	//0.0 to 20.0M-ohm = 0000h to 00C8h ,0.1M-ohm/dig
	GV.	AI.CHILLER2_FLOW_PV						:=	UINT_TO_REAL(	ECC.	CHILLER2_PV.Module2_Word[3]	)	;	//0.0 to 150.0LPM = 0000h to 05DCh 0.1LPM/dig
	GV.	AI.CHILLER2_PRESS_PV					:=	UINT_TO_REAL(	ECC.	CHILLER2_PV.Module2_Word[4]	)	;	//0.00 to 2.00MPa = 0h to C8h 0.01MP/dig
	ECC.CHILLER2_SV.Module2_Word[1]				:=	REAL_TO_UINT(	GV.AO.Chiller2_On					)	;	//CHILLER1 ON
	ECC.CHILLER2_SV.Module2_Word[2]				:=	REAL_TO_UINT(	GV.	AO.Chiller_Temp2_SV	*10			)	;	// -20.0 to 90.0℃= FF38h to 384h 0.1℃/dig
	ECC.CHILLER2_SV.Module2_Word[3]				:=	INT_TO_UINT(ECC.	CHAMBER_IN.	C05	[	1	]		)	;	// Stage温度反馈给chiller

ACTION PLC_TO_UI:
PM.HeartBeat:=UI.HeartBeat;
PM.NDI:=GV.NDI;
PM.AI:=GV.AI;
GV.NDI.	AV1	:=GV.NDO.	AV1	;
GV.NDI.	AV2	:=GV.NDO.	AV2	;
GV.NDI.	AV3	:=GV.NDO.	AV3	;
GV.NDI.	AV4	:=GV.NDO.	AV4	;
GV.NDI.	AV5	:=GV.NDO.	AV5	;
GV.NDI.	AV6	:=GV.NDO.	AV6	;
GV.NDI.	AV7	:=GV.NDO.	AV7	;
GV.NDI.	AV8	:=GV.NDO.	AV8	;
GV.NDI.	AV9	:=GV.NDO.	AV9	;
GV.NDI.	AV10	:=GV.NDO.	AV10	;
GV.NDI.	AV11	:=GV.NDO.	AV11	;
GV.NDI.	AV12	:=GV.NDO.	AV12	;
GV.NDI.	AV13	:=GV.NDO.	AV13	;
GV.NDI.	AV14	:=GV.NDO.	AV14	;
GV.NDI.	AV15	:=GV.NDO.	AV15	;
GV.NDI.	AV16	:=GV.NDO.	AV16	;
GV.NDI.	AV17	:=GV.NDO.	AV17	;
GV.NDI.	AV18	:=GV.NDO.	AV18	;
GV.NDI.	AV19	:=GV.NDO.	AV19	;
GV.NDI.	AV20	:=GV.NDO.	AV20	;
GV.NDI.	AV21	:=GV.NDO.	AV21	;
GV.NDI.	AV22	:=GV.NDO.	AV22	;
GV.NDI.	AV23	:=GV.NDO.	AV23	;
GV.NDI.	AV24	:=GV.NDO.	AV24	;
GV.NDI.	AV25	:=GV.NDO.	AV25	;
GV.NDI.	AV26	:=GV.NDO.	AV26	;
GV.NDI.	AV27	:=GV.NDO.	AV27	;
END_ACTION

ACTION UI_TO_PLC:

	
//CONFIG
	GV.PMConfig:=UI.PMConfig;
	
	GV.MFCVerification:=UI.MFCVerification;
	
	GV.Chiller:=UI.Chiller;
	GV.InnerChiller:=UI.InnerChiller;
	GV.OuterChiller:=UI.OuterChiller;
	GV.TopChiller:=UI.TopChiller;
	
	GV.DryPump:=UI.DryPump;
	
	GV.Mfcgas1:=UI.Mfcgas1;
	GV.Mfcgas2:=UI.Mfcgas2;
	GV.Mfcgas3:=UI.Mfcgas3;
	GV.Mfcgas4:=UI.Mfcgas4;
	GV.Mfcgas5:=UI.Mfcgas5;
	GV.Mfcgas6:=UI.Mfcgas6;
	GV.Mfcgas7:=UI.Mfcgas7;
	GV.Mfcgas8:=UI.Mfcgas8;
	GV.Mfcgas9:=UI.Mfcgas9;
	GV.Mfcgas10:=UI.Mfcgas10;
	GV.Mfcgas11:=UI.Mfcgas11;
	GV.Mfcgas12:=UI.Mfcgas12;
	GV.MfcN2:=UI.MfcN2;
	GV.MfcHe:=UI.MfcHe;
	
	GV.Pump:=UI.Pump;
	
	GV.Purge:=UI.Purge;
	
	GV.PendulumHeater:=UI.PendulumHeater;
	GV.LidHeater:=UI.LidHeater;
	GV.ChamberHeater:=UI.ChamberHeater;
	GV.IGSHeater:=UI.IGSHeater;
	GV.TapeHeater:=UI.TapeHeater;
	GV.ForelineHeater:=UI.ForelineHeater;
	
	GV.ElectrostaticVoltageSource:=UI.ElectrostaticVoltageSource;
	
	GV.TurboPump:=UI.TurboPump;
	
	GV.PendulumValve:=UI.PendulumValve;
	
	GV.IdleClean:=UI.IdleClean;
	
	GV.EPD:=UI.EPD;
	
	GV.HighTemperatureChiller:=UI.HighTemperatureChiller;
	GV.ChamberHeater:=UI.ChamberHeater;
	GV.ChamberHeater:=UI.ChamberHeater;

//Status	
	GV.AO.	AV102_Temp_SV								:=	UI.AO.	AV102_Temp_SV			;
	GV.AO.	AV101_Temp_SV								:=	UI.AO.	AV101_Temp_SV			;
	GV.AO.	AV106_Temp_SV								:=	UI.AO.	AV106_Temp_SV			;
	GV.AO.	BA01_Temp_SV								:=	UI.AO.	BA01_Temp_SV			;
	GV.AO.	VG103_Pipe_Temp_SV							:=	UI.AO.	VG103_Pipe_Temp_SV		;
	GV.AO.	Exhaust1_6_Temp_SV							:=	UI.AO.	Exhaust1_6_Temp_SV		;
	GV.AO.	Exhaust7_8_Temp_SV							:=	UI.AO.	Exhaust7_8_Temp_SV		;
	GV.AO.	VG101_Pipe_Temp_SV							:=	UI.AO.	VG101_Pipe_Temp_SV		;
	GV.AO.	Gate_Valve_Temp_SV							:=	UI.AO.	Gate_Valve_Temp_SV		;
	GV.AO.	APC_Temp_SV									:=	UI.AO.	APC_Temp_SV		;
	GV.AO.	TMP_Temp_SV									:=	UI.AO.	TMP_Temp_SV		;
	GV.AO.	Tape_Temp1_SV								:=	UI.AO.	Tape_Temp1_SV		;
	GV.AO.	Tape_Temp2_SV								:=	UI.AO.	Tape_Temp2_SV		;
	GV.AO.	Tape_Temp3_SV								:=	UI.AO.	Tape_Temp3_SV		;
	GV.AO.	IGS_Temp1_SV								:=	UI.AO.	IGS_Temp1_SV		;
	GV.AO.	IGS_Temp2_SV								:=	UI.AO.	IGS_Temp2_SV		;
	GV.AO.	Chiller_Temp1_SV							:=	UI.AO.	Chiller_Temp1_SV		;
	GV.AO.	Chiller_Temp2_SV							:=	UI.AO.	Chiller_Temp2_SV		;
	GV.AO.	Chiller1_On									:=	UI.AO.	Chiller1_On			;
	GV.AO.	Chiller2_On									:=	UI.AO.	Chiller2_On			;
	GV.AO.	TMP.	Turbo_Start_Stop					:=	UI.AO.	TMP.	Turbo_Start_Stop	;
	GV.AO.	TMP.	Turbo_Reset_Alarm					:=	UI.AO.	TMP.	Turbo_Reset_Alarm	;
	GV.AO.	TMP.	Turbo_Low_Speed						:=	UI.AO.	TMP.	Turbo_Low_Speed	;
	
	GV.NDO.AV104:=UI.NDO.AV104;
	GV.NDO.AV105:=UI.NDO.AV105;
	
	IF NOT MAIN.Process_EN THEN	
	GV.NDO					:=	UI.NDO;	
	GV.AO.	LID_Temp_SV		:=	UI.AO.	LID_Temp_SV		;

	GV.AO.	Chamber_Temp1_SV	:=	UI.AO.	Chamber_Temp1_SV		;
	GV.AO.	Chamber_Temp2_SV	:=	UI.AO.	Chamber_Temp2_SV		;
	GV.AO.	Chamber_Temp3_SV	:=	UI.AO.	Chamber_Temp3_SV		;

	GV.AO.	MFC1_Flow_Setpoint	:=	UI.AO.	MFC1_Flow_Setpoint		;
	GV.AO.	MFC1_Rate_Setpoint	:=	UI.AO.	MFC1_Rate_Setpoint		;
	GV.AO.	MFC2_Flow_Setpoint	:=	UI.AO.	MFC2_Flow_Setpoint		;
	GV.AO.	MFC2_Rate_Setpoint	:=	UI.AO.	MFC2_Rate_Setpoint		;
	GV.AO.	MFC3_Flow_Setpoint	:=	UI.AO.	MFC3_Flow_Setpoint		;
	GV.AO.	MFC3_Rate_Setpoint	:=	UI.AO.	MFC3_Rate_Setpoint		;
	GV.AO.	MFC4_Flow_Setpoint	:=	UI.AO.	MFC4_Flow_Setpoint		;
	GV.AO.	MFC4_Rate_Setpoint	:=	UI.AO.	MFC4_Rate_Setpoint		;
	GV.AO.	MFC5_Flow_Setpoint	:=	UI.AO.	MFC5_Flow_Setpoint		;
	GV.AO.	MFC5_Rate_Setpoint	:=	UI.AO.	MFC5_Rate_Setpoint		;
	GV.AO.	MFC6_Flow_Setpoint	:=	UI.AO.	MFC6_Flow_Setpoint		;
	GV.AO.	MFC6_Rate_Setpoint	:=	UI.AO.	MFC6_Rate_Setpoint		;
	GV.AO.	MFC7_Flow_Setpoint	:=	UI.AO.	MFC7_Flow_Setpoint		;
	GV.AO.	MFC7_Rate_Setpoint	:=	UI.AO.	MFC7_Rate_Setpoint		;
	GV.AO.	Stage_Temp1_SV		:=	UI.AO.	Stage_Temp1_SV		;
	GV.AO.	Stage_Temp2_SV		:=	UI.AO.	Stage_Temp2_SV		;
	GV.AO.	APC.	Target_Pressure	:=	UI.AO.	APC.	Target_Pressure	;
	GV.AO.	APC.	Target_Position	:=	UI.AO.	APC.	Target_Position	;
	//GV.AO.	APC.	Pressure_Input_Digital_Sensor_1	:=	UI.AO.	APC.	Pressure_Input_Digital_Sensor_1	;
	//GV.AO.	APC.	Pressure_Input_Digital_Sensor_2	:=	UI.AO.	APC.	Pressure_Input_Digital_Sensor_2	;
	GV.AO.	APC.	Control_Mode	:=	UI.AO.	APC.	Control_Mode	;
	GV.AO.	APC.	General_Control_Setpoint	:=	UI.AO.	APC.	General_Control_Setpoint	;
	GV.AO.	APC.	Pressure_Ramp_Time	:=	UI.AO.	APC.	Pressure_Ramp_Time	;
	END_IF

//RECIPE
	GV.Step_Num:=UI.Step_Num;
	GV.SetpArray:=UI.SetpArray;
	
	GV.Process_Start:=UI.Process_Start;
	GV.Process_Stop:=UI.Process_Stop;
END_ACTION

END_PROGRAM

// ---- POUs/PRG/IL.TcPOU
PROGRAM IL
VAR
	RANGE_PG_PS1:RANGEJD;
	RANGE_PG_PS2:RANGEJD;
	RANGE_PG_PS3:RANGEJD;
	RANGE_PG_PS4:RANGEJD;
	RANGE_PG_PS5:RANGEJD;
	RANGE_PG_PS6:RANGEJD;
	RANGE_PG_PS7:RANGEJD;
	RANGE_PG_PS8:RANGEJD;
	RANGE_PG_PS9:RANGEJD;
	
	RANGE_MFC1:RANGEJD;
	RANGE_MFC2:RANGEJD;
	RANGE_MFC3:RANGEJD;
	RANGE_MFC4:RANGEJD;
	RANGE_MFC5:RANGEJD;
	RANGE_MFC6:RANGEJD;
	RANGE_MFC7:RANGEJD;
	RANGE_MFC8:RANGEJD;
	RANGE_MFC9:RANGEJD;
	
	RANGE_CHAMBER_HEATER1:RANGEJD;
	RANGE_CHAMBER_HEATER2:RANGEJD;
	RANGE_CHAMBER_HEATER3:RANGEJD;
	
	RANGE_LID_HEATER:RANGEJD;
	
	RANGE_STAGE_EDGE_HEATER:RANGEJD;
	RANGE_STAGE_CENTER_HEATER:RANGEJD;
	
	//INTERLOCK	
	TON_PrepareTransfer:TON;	
	TON_TransferWafer:TON;	
	TON_OpenGasValve:TON;	
	TON_CloseGasValve:TON;	
	TON_OpenCloseSlitValve:TON;
	
	ALWAYS_TRUE:BOOL:=TRUE;
END_VAR
VAR // added by the converter: edge detectors and wires of the graphical bodies
    _w1, _w2, _w3, _w4, _w5, _w6 : BOOL;
END_VAR

VALVE();
Temp();
SYS();
SPLC();
ACT_HEATER();
ACT_MFC();
ACT_MFC();

//TMP Pressure OUT OF RANGE
	IF GV.PMConfig.TurboN2Pressure	<=	GV.TurboN2PurgePressure
		THEN
		PM.INFO.Alarm.TurboN2PurgePressureOutOfRange:=TRUE;
		ELSE
		PM.INFO.Alarm.TurboN2PurgePressureOutOfRange:=FALSE;	
	END_IF
	
//PrepareTransfer TIMEOUT
	TON_PrepareTransfer(IN:= GV_IL.STATUS_PrepareTransfer, PT:=INT_TO_TIME(GV.PMConfig.PrepareTransferTimeout)*1000 , Q=> , ET=> );	
	IF TON_PrepareTransfer.Q
		THEN
		PM.INFO.Alarm.PrepareTransferTimerout:=TRUE;
		ELSE
		PM.INFO.Alarm.PrepareTransferTimerout:=FALSE;
	END_IF
	
//TransferWafer TIMEOUT
	TON_TransferWafer(IN:=GV_IL.STATUS_TransferWafer , PT:= INT_TO_TIME(GV.PMConfig.TransferWaferTimeout)*1000, Q=> , ET=> );
	IF TON_TransferWafer.Q
		THEN
		PM.INFO.Alarm.TransferWaferTimeout:=TRUE;
		ELSE
		PM.INFO.Alarm.TransferWaferTimeout:=FALSE;	
	END_IF
	
//OpenGasValve TIMEOUT
	TON_OpenGasValve(IN:=GV_IL.STATUS_OpenGasValve , PT:= INT_TO_TIME(GV.PMConfig.OpenGasValveTimeout)*1000, Q=> , ET=> );
	IF TON_OpenGasValve.Q
		THEN
		PM.INFO.Alarm.OpenGasValveTimeout:=TRUE;
		ELSE 
		PM.INFO.Alarm.OpenGasValveTimeout:=FALSE;
	END_IF
	
//CloseGasValve TIMEOUT
	TON_CloseGasValve(IN:=GV_IL.STATUS_CloseGasValve , PT:= INT_TO_TIME(GV.PMConfig.CloseGasValveTimeout)*1000, Q=> , ET=> );
	IF TON_CloseGasValve.Q
		THEN
		PM.INFO.Alarm.CloseGasValveTimeout:=TRUE;
		ELSE
		PM.INFO.Alarm.CloseGasValveTimeout:=FALSE;
	END_IF
	
//OpenCloseSlitValve TIMEOUT
	TON_OpenCloseSlitValve(IN:=GV_IL.STATUS_OpenCloseSlitValve , PT:= INT_TO_TIME(GV.PMConfig.OpenCloseSlitValveTimeout)*1000, Q=> , ET=> );
	IF TON_OpenCloseSlitValve.Q
		THEN
		PM.INFO.Alarm.OpenCloseSlitValveTimeout:=TRUE;
		ELSE
		PM.INFO.Alarm.OpenCloseSlitValveTimeout:=FALSE;	
	END_IF
	
	
//PRESSURE ALARM
	//PM.INFO.Alarm.PRESSURE:=
	
//ALARM OR WARNING OCCUR
	GV.ALARM_OCC:=NOT (
				 	//PM.INFO.Alarm.PRESSURE
					PM.INFO.Alarm.MFC1	
				AND PM.INFO.Alarm.MFC2	
				AND	PM.INFO.Alarm.MFC3
				AND PM.INFO.Alarm.MFC4	
				AND PM.INFO.Alarm.MFC5	
				AND PM.INFO.Alarm.MFC6
				AND PM.INFO.Alarm.MFC7	
				AND PM.INFO.Alarm.MFC8	
				AND PM.INFO.Alarm.MFC9
				AND PM.INFO.Alarm.WALL_TEMP	
				AND PM.INFO.Alarm.LID_TEMP	
				AND PM.INFO.Alarm.STAGE_EDGE_TEMP	
				AND PM.INFO.Alarm.STAGE_CENTER_TEMP
				AND PM.INFO.Alarm.Gas1FlowPressureOutOfRange
				AND PM.INFO.Alarm.Gas2FlowPressureOutOfRange
				AND PM.INFO.Alarm.Gas3FlowPressureOutOfRange
				//AND PM.INFO.Alarm.Gas4FlowPressureOutOfRange
				AND PM.INFO.Alarm.Gas5FlowPressureOutOfRange
				AND PM.INFO.Alarm.Gas6FlowPressureOutOfRange
				//AND PM.INFO.Alarm.TurboN2PurgePressureOutOfRange
				//AND PM.INFO.Alarm.PrepareTransferTimerout
				//AND PM.INFO.Alarm.TransferWaferTimeout
				//AND PM.INFO.Alarm.OpenGasValveTimeout
				//AND PM.INFO.Alarm.CloseGasValveTimeout
				//AND PM.INFO.Alarm.OpenCloseSlitValveTimeout
				//AND PM.INFO.Alarm.ATMCheckTimeout
				//AND PM.INFO.Alarm.DRY_PUMP
				//AND PM.INFO.Alarm.PENDULUM_VALVE
				//AND PM.INFO.Alarm.TURBO_PUMP
				AND PM.INFO.Alarm.CHILLER1
				AND PM.INFO.Alarm.CHILLER2
				AND (PM.INFO.Alarm.TOLERANCE_PRESSURE				
				AND PM.INFO.Alarm.TOLERANCE_MFC1
				AND PM.INFO.Alarm.TOLERANCE_MFC2
				AND PM.INFO.Alarm.TOLERANCE_MFC3
				AND PM.INFO.Alarm.TOLERANCE_MFC4
				AND PM.INFO.Alarm.TOLERANCE_MFC5
				AND PM.INFO.Alarm.TOLERANCE_MFC6
				AND PM.INFO.Alarm.TOLERANCE_MFC7
				AND PM.INFO.Alarm.TOLERANCE_MFC8
				AND PM.INFO.Alarm.TOLERANCE_MFC9
				AND PM.INFO.Alarm.TOLERANCE_WALL_TEMP
				AND PM.INFO.Alarm.TOLERANCE_LID_TEMP
				AND PM.INFO.Alarm.TOLERANCE_STAGE_EDGE_TEMP
				AND PM.INFO.Alarm.TOLERANCE_STAGE_CENTER_TEMP)
				);

	GV.WARNING_OCC:=NOT (
					//PM.INFO.Warning.PRESSURE					
					PM.INFO.Warning.MFC1
				AND PM.INFO.Warning.MFC2
				AND PM.INFO.Warning.MFC3
				AND PM.INFO.Warning.MFC4
				AND PM.INFO.Warning.MFC5
				AND PM.INFO.Warning.MFC6
				AND PM.INFO.Warning.MFC7
				AND PM.INFO.Warning.MFC8
				AND PM.INFO.Warning.MFC9
				AND PM.INFO.Warning.WALL_TEMP
				AND PM.INFO.Warning.LID_TEMP
				AND PM.INFO.Warning.STAGE_EDGE_TEMP
				AND PM.INFO.Warning.STAGE_CENTER_TEMP
				AND PM.INFO.Warning.Gas1FlowPressureOutOfRange
				AND PM.INFO.Warning.Gas2FlowPressureOutOfRange
				AND PM.INFO.Warning.Gas3FlowPressureOutOfRange
				//AND PM.INFO.Warning.Gas4FlowPressureOutOfRange
				AND PM.INFO.Warning.Gas5FlowPressureOutOfRange
				AND PM.INFO.Warning.Gas6FlowPressureOutOfRange
				//AND PM.INFO.Warning.OpenCloseSlitValveTimeout
				AND PM.INFO.Warning.CHILLER1
				AND PM.INFO.Warning.CHILLER2
				AND (PM.INFO.Warning.TOLERANCE_PRESSURE
				AND PM.INFO.Warning.TOLERANCE_MFC1
				AND PM.INFO.Warning.TOLERANCE_MFC2
				AND PM.INFO.Warning.TOLERANCE_MFC3
				AND PM.INFO.Warning.TOLERANCE_MFC4
				AND PM.INFO.Warning.TOLERANCE_MFC5
				AND PM.INFO.Warning.TOLERANCE_MFC6
				AND PM.INFO.Warning.TOLERANCE_MFC7
				AND PM.INFO.Warning.TOLERANCE_MFC8
				AND PM.INFO.Warning.TOLERANCE_MFC9
				AND PM.INFO.Warning.TOLERANCE_WALL_TEMP
				AND PM.INFO.Warning.TOLERANCE_LID_TEMP
				AND PM.INFO.Warning.TOLERANCE_STAGE_EDGE_TEMP
				AND PM.INFO.Warning.TOLERANCE_STAGE_CENTER_TEMP)
				);

ACTION ACT_HEATER:
//CHAMBER HEATER
	RANGE_CHAMBER_HEATER1(
	ENABLE:= GV.ChamberHeater.HeaterTolerance_Enable,
	SV:= REAL_TO_LREAL(GV.AO.Chamber_Temp1_SV),
	PV:= REAL_TO_LREAL( GV.AI.Chamber_Temp1), 
	RANGE_ALARM_H:= ANY_TO_REAL(GV.ChamberHeater.HeaterAlarmRange.SV), 
	RANGE_ALARM_L:= ANY_TO_LREAL(GV.ChamberHeater.HeaterAlarmRange.SV), 
	RANGE_WARNING_H:= ANY_TO_LREAL(GV.ChamberHeater.HeaterWarningRange.SV), 
	RANGE_WARNING_L:= ANY_TO_LREAL(GV.ChamberHeater.HeaterWarningRange.SV), 
	TIME_ALARM:= ANY_TO_LREAL(GV.ChamberHeater.HeaterAlarmTime.SV), 
	TIME_WARNING:= ANY_TO_LREAL(GV.ChamberHeater.HeaterWarningTime.SV), 
	ALARM=> , 
	WARNING=> );
	
	RANGE_CHAMBER_HEATER2(
	ENABLE:= GV.ChamberHeater.HeaterTolerance_Enable,
	SV:= REAL_TO_LREAL(GV.AO.Chamber_Temp2_SV),
	PV:= REAL_TO_LREAL( GV.AI.Chamber_Temp2), 
	RANGE_ALARM_H:= ANY_TO_LREAL(GV.ChamberHeater.HeaterAlarmRange.SV), 
	RANGE_ALARM_L:= ANY_TO_LREAL(GV.ChamberHeater.HeaterAlarmRange.SV), 
	RANGE_WARNING_H:= ANY_TO_LREAL(GV.ChamberHeater.HeaterWarningRange.SV), 
	RANGE_WARNING_L:= ANY_TO_LREAL(GV.ChamberHeater.HeaterWarningRange.SV), 
	TIME_ALARM:= ANY_TO_LREAL(GV.ChamberHeater.HeaterAlarmTime.SV), 
	TIME_WARNING:= ANY_TO_LREAL(GV.ChamberHeater.HeaterWarningTime.SV), 
	ALARM=> , 
	WARNING=> );
	
	RANGE_CHAMBER_HEATER3(
	ENABLE:= GV.ChamberHeater.HeaterTolerance_Enable,
	SV:= REAL_TO_LREAL(GV.AO.Chamber_Temp3_SV),
	PV:= REAL_TO_LREAL( GV.AI.Chamber_Temp3), 
	RANGE_ALARM_H:= ANY_TO_LREAL(GV.ChamberHeater.HeaterAlarmRange.SV), 
	RANGE_ALARM_L:= ANY_TO_LREAL(GV.ChamberHeater.HeaterAlarmRange.SV), 
	RANGE_WARNING_H:= ANY_TO_LREAL(GV.ChamberHeater.HeaterWarningRange.SV), 
	RANGE_WARNING_L:= ANY_TO_LREAL(GV.ChamberHeater.HeaterWarningRange.SV), 
	TIME_ALARM:= ANY_TO_LREAL(GV.ChamberHeater.HeaterAlarmTime.SV), 
	TIME_WARNING:= ANY_TO_LREAL(GV.ChamberHeater.HeaterWarningTime.SV), 
	ALARM=> , 
	WARNING=> );
	
	PM.INFO.Alarm.WALL_TEMP:=	RANGE_CHAMBER_HEATER1.ALARM 
							AND RANGE_CHAMBER_HEATER2.ALARM 
							AND RANGE_CHAMBER_HEATER3.ALARM
								;
	PM.INFO.Warning.WALL_TEMP:=	RANGE_CHAMBER_HEATER1.WARNING 
							AND RANGE_CHAMBER_HEATER2.WARNING 
							AND RANGE_CHAMBER_HEATER3.WARNING
								;
//LID HEATER
	RANGE_LID_HEATER(
	ENABLE:= GV.LidHeater.HeaterTolerance_Enable,
	SV:= REAL_TO_LREAL(GV.AO.LID_Temp_SV),
	PV:= REAL_TO_LREAL( GV.AI.Lid_Temp), 
	RANGE_ALARM_H:= ANY_TO_LREAL(GV.LidHeater.HeaterAlarmRange.SV), 
	RANGE_ALARM_L:= ANY_TO_LREAL(GV.LidHeater.HeaterAlarmRange.SV), 
	RANGE_WARNING_H:= ANY_TO_LREAL(GV.LidHeater.HeaterWarningRange.SV), 
	RANGE_WARNING_L:= ANY_TO_LREAL(GV.LidHeater.HeaterWarningRange.SV), 
	TIME_ALARM:= ANY_TO_LREAL(GV.LidHeater.HeaterAlarmTime.SV), 
	TIME_WARNING:= ANY_TO_LREAL(GV.LidHeater.HeaterWarningTime.SV), 
	ALARM=> , 
	WARNING=> );
	
	PM.INFO.Alarm.LID_TEMP	:=	RANGE_LID_HEATER.ALARM ;
	PM.INFO.Warning.LID_TEMP:=	RANGE_LID_HEATER.WARNING;
	
//STAGE HEATER
	RANGE_STAGE_CENTER_HEATER(
	ENABLE:= GV.Chiller.EnableAlarmTolerance,
	SV:= REAL_TO_LREAL(GV.AO.Chiller_Temp1_SV),
	PV:= REAL_TO_LREAL( GV.AI.CHILLER1_TEMP_PV), 
	RANGE_ALARM_H:= ANY_TO_LREAL(GV.Chiller.ToleranceAlarmRange.SV), 
	RANGE_ALARM_L:= ANY_TO_LREAL(GV.Chiller.ToleranceAlarmRange.SV), 
	RANGE_WARNING_H:= ANY_TO_LREAL(GV.Chiller.ToleranceAlarmRange.SV), 
	RANGE_WARNING_L:= ANY_TO_LREAL(GV.Chiller.ToleranceAlarmRange.SV), 
	TIME_ALARM:= ANY_TO_LREAL(GV.Chiller.ToleranceAlarmTime.SV), 
	TIME_WARNING:= ANY_TO_LREAL(GV.Chiller.ToleranceAlarmTime.SV), 
	ALARM=> , 
	WARNING=> );
	
	PM.INFO.Alarm.STAGE_CENTER_TEMP:=RANGE_STAGE_CENTER_HEATER.ALARM;
	PM.INFO.Warning.STAGE_CENTER_TEMP:=RANGE_STAGE_CENTER_HEATER.WARNING;
	PM.INFO.Alarm.CHILLER1:=NOT ECC.	CHILLER1_PV.Module2_Word[5].1;
	PM.INFO.Warning.CHILLER1:=NOT ECC.	CHILLER1_PV.Module2_Word[5].2;
	
	RANGE_STAGE_EDGE_HEATER(
	ENABLE:= GV.Chiller.EnableAlarmTolerance,
	SV:= REAL_TO_LREAL(GV.AO.Chiller_Temp2_SV),
	PV:= REAL_TO_LREAL( GV.AI.CHILLER2_TEMP_PV), 
	RANGE_ALARM_H:= ANY_TO_LREAL(GV.Chiller.ToleranceAlarmRange.SV), 
	RANGE_ALARM_L:= ANY_TO_LREAL(GV.Chiller.ToleranceAlarmRange.SV), 
	RANGE_WARNING_H:= ANY_TO_LREAL(GV.Chiller.ToleranceAlarmRange.SV), 
	RANGE_WARNING_L:= ANY_TO_LREAL(GV.Chiller.ToleranceAlarmRange.SV), 
	TIME_ALARM:= ANY_TO_LREAL(GV.Chiller.ToleranceAlarmTime.SV), 
	TIME_WARNING:= ANY_TO_LREAL(GV.Chiller.ToleranceAlarmTime.SV), 
	ALARM=> , 
	WARNING=> );
	
	PM.INFO.Alarm.STAGE_EDGE_TEMP:=RANGE_STAGE_EDGE_HEATER.ALARM;
	PM.INFO.Warning.STAGE_EDGE_TEMP:=RANGE_STAGE_EDGE_HEATER.WARNING;
	PM.INFO.Alarm.CHILLER2:=NOT ECC.	CHILLER2_PV.Module2_Word[5].1;
	PM.INFO.Warning.CHILLER2:=NOT ECC.	CHILLER2_PV.Module2_Word[5].2;
END_ACTION

ACTION ACT_MFC:
RANGE_MFC1(
	ENABLE:= GV.Mfcgas1.EnableAlarm AND GV.Mfcgas1.Enable,
	SV:= REAL_TO_LREAL(GV.AO.MFC1_Flow_Setpoint),
	PV:= REAL_TO_LREAL( GV.AI.MFC1_Flow), 
	RANGE_ALARM_H:= GV.Mfcgas1.AlarmRange.SV, 
	RANGE_ALARM_L:= GV.Mfcgas1.AlarmRange.SV, 
	RANGE_WARNING_H:= GV.Mfcgas1.WarningRange.SV, 
	RANGE_WARNING_L:= GV.Mfcgas1.WarningRange.SV, 
	TIME_ALARM:= GV.Mfcgas1.AlarmTime.SV, 
	TIME_WARNING:= GV.Mfcgas1.WarningTime.SV, 
	ALARM=> , 
	WARNING=> );
	
	RANGE_MFC2(
	ENABLE:= GV.Mfcgas2.EnableAlarm AND GV.Mfcgas2.Enable, 
	SV:= REAL_TO_LREAL(GV.AO.MFC2_Flow_Setpoint),
	PV:= REAL_TO_LREAL( GV.AI.MFC2_Flow), 
	RANGE_ALARM_H:= GV.Mfcgas2.AlarmRange.SV, 
	RANGE_ALARM_L:= GV.Mfcgas2.AlarmRange.SV, 
	RANGE_WARNING_H:= GV.Mfcgas2.WarningRange.SV, 
	RANGE_WARNING_L:= GV.Mfcgas2.WarningRange.SV, 
	TIME_ALARM:= GV.Mfcgas2.AlarmTime.SV, 
	TIME_WARNING:= GV.Mfcgas2.WarningTime.SV, 
	ALARM=> , 
	WARNING=> );

	RANGE_MFC3(	
	ENABLE:= GV.Mfcgas3.EnableAlarm AND GV.Mfcgas3.Enable, 
	SV:= REAL_TO_LREAL(GV.AO.MFC3_Flow_Setpoint),
	PV:= REAL_TO_LREAL( GV.AI.MFC3_Flow), 
	RANGE_ALARM_H:= GV.Mfcgas3.AlarmRange.SV, 
	RANGE_ALARM_L:= GV.Mfcgas3.AlarmRange.SV, 
	RANGE_WARNING_H:= GV.Mfcgas3.WarningRange.SV, 
	RANGE_WARNING_L:= GV.Mfcgas3.WarningRange.SV, 
	TIME_ALARM:= GV.Mfcgas3.AlarmTime.SV, 
	TIME_WARNING:= GV.Mfcgas3.WarningTime.SV,  
	ALARM=> , 
	WARNING=> );

	RANGE_MFC4(	
	ENABLE:= GV.Mfcgas4.EnableAlarm AND GV.Mfcgas4.Enable, 
	SV:= REAL_TO_LREAL(GV.AO.MFC4_Flow_Setpoint),
	PV:= REAL_TO_LREAL( GV.AI.MFC4_Flow), 
	RANGE_ALARM_H:= GV.Mfcgas4.AlarmRange.SV, 
	RANGE_ALARM_L:= GV.Mfcgas4.AlarmRange.SV, 
	RANGE_WARNING_H:= GV.Mfcgas4.WarningRange.SV, 
	RANGE_WARNING_L:= GV.Mfcgas4.WarningRange.SV, 
	TIME_ALARM:= GV.Mfcgas4.AlarmTime.SV, 
	TIME_WARNING:= GV.Mfcgas4.WarningTime.SV, 
	ALARM=> , 
	WARNING=> );
	
	RANGE_MFC5(	
	ENABLE:= GV.Mfcgas5.EnableAlarm AND GV.Mfcgas5.Enable, 
	SV:= REAL_TO_LREAL(GV.AO.MFC5_Flow_Setpoint),
	PV:= REAL_TO_LREAL( GV.AI.MFC5_Flow), 
	RANGE_ALARM_H:= GV.Mfcgas5.AlarmRange.SV, 
	RANGE_ALARM_L:= GV.Mfcgas5.AlarmRange.SV, 
	RANGE_WARNING_H:= GV.Mfcgas5.WarningRange.SV, 
	RANGE_WARNING_L:= GV.Mfcgas5.WarningRange.SV, 
	TIME_ALARM:= GV.Mfcgas5.AlarmTime.SV, 
	TIME_WARNING:= GV.Mfcgas5.WarningTime.SV, 
	ALARM=> , 
	WARNING=> );

	RANGE_MFC6(	
	ENABLE:= GV.Mfcgas6.EnableAlarm AND GV.Mfcgas6.Enable, 
	SV:= REAL_TO_LREAL(GV.AO.MFC6_Flow_Setpoint),
	PV:= REAL_TO_LREAL( GV.AI.MFC6_Flow), 
	RANGE_ALARM_H:= GV.Mfcgas6.AlarmRange.SV, 
	RANGE_ALARM_L:= GV.Mfcgas6.AlarmRange.SV, 
	RANGE_WARNING_H:= GV.Mfcgas6.WarningRange.SV, 
	RANGE_WARNING_L:= GV.Mfcgas6.WarningRange.SV, 
	TIME_ALARM:= GV.Mfcgas6.AlarmTime.SV, 
	TIME_WARNING:= GV.Mfcgas6.WarningTime.SV,  
	ALARM=> , 
	WARNING=> );

	RANGE_MFC7(	
	ENABLE:= GV.Mfcgas7.EnableAlarm AND GV.Mfcgas7.Enable, 
	SV:= REAL_TO_LREAL(GV.AO.MFC7_Flow_Setpoint),
	PV:= REAL_TO_LREAL( GV.AI.MFC7_Flow), 
	RANGE_ALARM_H:= GV.Mfcgas7.AlarmRange.SV, 
	RANGE_ALARM_L:= GV.Mfcgas7.AlarmRange.SV, 
	RANGE_WARNING_H:= GV.Mfcgas7.WarningRange.SV, 
	RANGE_WARNING_L:= GV.Mfcgas7.WarningRange.SV, 
	TIME_ALARM:= GV.Mfcgas7.AlarmTime.SV, 
	TIME_WARNING:= GV.Mfcgas7.WarningTime.SV, 
	ALARM=> , 
	WARNING=> );
(*
	RANGE_MFC8(	
	ENABLE:= GV.Mfcgas8.EnableAlarm AND GV.Mfcgas8.Enable, 
	PV:= REAL_TO_LREAL( GV.AI.MFC8_Flow), 
	RANGE_ALARM_H:= GV.Mfcgas8.AlarmRange.MaxSV, 
	RANGE_ALARM_L:= 0, 
	RANGE_WARNING_H:= GV.Mfcgas8.WarningRange.MaxSV, 
	RANGE_WARNING_L:= 0, 
	TIME_ALARM:= GV.Mfcgas8.AlarmTime.SV, 
	TIME_WARNING:= GV.Mfcgas8.WarningTime.SV, 
	ALARM=> , 
	WARNING=> );

	RANGE_MFC9(	
	ENABLE:= GV.Mfcgas9.EnableAlarm AND GV.Mfcgas9.Enable, 
	PV:= REAL_TO_LREAL( GV.AI.MFC9_Flow), 
	RANGE_ALARM_H:= GV.Mfcgas9.AlarmRange.MaxSV, 
	RANGE_ALARM_L:= 0, 
	RANGE_WARNING_H:= GV.Mfcgas9.WarningRange.MaxSV, 
	RANGE_WARNING_L:= 0, 
	TIME_ALARM:= GV.Mfcgas9.AlarmTime.SV, 
	TIME_WARNING:= GV.Mfcgas9.WarningTime.SV, 
	ALARM=> , 
	WARNING=> );
*)	
	
	PM.Info.Alarm.MFC1:=  RANGE_MFC1.ALARM;
	PM.INFO.Alarm.MFC2:=  RANGE_MFC2.ALARM;
	PM.INFO.Alarm.MFC3:=  RANGE_MFC3.ALARM;
	PM.INFO.Alarm.MFC4:=  RANGE_MFC4.ALARM;
	PM.INFO.Alarm.MFC5:=  RANGE_MFC5.ALARM;
	PM.INFO.Alarm.MFC6:=  RANGE_MFC6.ALARM;
	PM.INFO.Alarm.MFC7:=  RANGE_MFC7.ALARM;
	PM.INFO.Alarm.MFC8:=  RANGE_MFC8.ALARM OR TRUE;
	PM.INFO.Alarm.MFC9:=  RANGE_MFC9.ALARM OR TRUE;
	
	PM.INFO.warning.MFC1:=  RANGE_MFC1.warning;
	PM.INFO.warning.MFC2:=  RANGE_MFC2.warning;
	PM.INFO.warning.MFC3:=  RANGE_MFC3.warning;
	PM.INFO.warning.MFC4:=  RANGE_MFC4.warning;
	PM.INFO.warning.MFC5:=  RANGE_MFC5.warning;
	PM.INFO.warning.MFC6:=  RANGE_MFC6.warning;
	PM.INFO.warning.MFC7:=  RANGE_MFC7.warning;
	PM.INFO.warning.MFC8:=  RANGE_MFC8.warning OR TRUE;
	PM.INFO.warning.MFC9:=  RANGE_MFC9.warning OR TRUE;
END_ACTION

ACTION ACT_PG_PS:
RANGE_PG_PS1(
	ENABLE:=TRUE,
	SV:= 270,
	PV:= GV.AI.PG_PS1_VALUE, 
	RANGE_ALARM_H:= GV.PMConfig.GasFlowPressureAlarmRange, 
	RANGE_ALARM_L:= GV.PMConfig.GasFlowPressureAlarmRange, 
	RANGE_WARNING_H:= GV.PMConfig.GasFlowPressureWarningRange, 
	RANGE_WARNING_L:= GV.PMConfig.GasFlowPressureWarningRange, 
	TIME_ALARM:= GV.PMConfig.GasFlowPressureAlarmTime, 
	TIME_WARNING:= GV.PMConfig.GasFlowPressureWarningTime, 
	ALARM=> , 
	WARNING=> );
	
	RANGE_PG_PS2(
	ENABLE:=TRUE,
	SV:= 270 ,
	PV:= GV.AI.PG_PS2_VALUE, 
	RANGE_ALARM_H:= GV.PMConfig.GasFlowPressureAlarmRange, 
	RANGE_ALARM_L:= GV.PMConfig.GasFlowPressureAlarmRange, 
	RANGE_WARNING_H:= GV.PMConfig.GasFlowPressureWarningRange, 
	RANGE_WARNING_L:= GV.PMConfig.GasFlowPressureWarningRange, 
	TIME_ALARM:= GV.PMConfig.GasFlowPressureAlarmTime, 
	TIME_WARNING:= GV.PMConfig.GasFlowPressureWarningTime, 
	ALARM=> , 
	WARNING=> );
	
	RANGE_PG_PS3(
	ENABLE:=TRUE,
	SV:= 270 ,
	PV:= GV.AI.PG_PS3_VALUE, 
	RANGE_ALARM_H:= GV.PMConfig.GasFlowPressureAlarmRange, 
	RANGE_ALARM_L:= GV.PMConfig.GasFlowPressureAlarmRange, 
	RANGE_WARNING_H:= GV.PMConfig.GasFlowPressureWarningRange, 
	RANGE_WARNING_L:= GV.PMConfig.GasFlowPressureWarningRange, 
	TIME_ALARM:= GV.PMConfig.GasFlowPressureAlarmTime, 
	TIME_WARNING:= GV.PMConfig.GasFlowPressureWarningTime, 
	ALARM=> , 
	WARNING=> );
	
	RANGE_PG_PS4(
	ENABLE:=TRUE,
	SV:=25,
	PV:= GV.AI.PG_PS4_VALUE, 
	RANGE_ALARM_H:= GV.PMConfig.GasFlowPressureAlarmRange, 
	RANGE_ALARM_L:= GV.PMConfig.GasFlowPressureAlarmRange, 
	RANGE_WARNING_H:= GV.PMConfig.GasFlowPressureWarningRange, 
	RANGE_WARNING_L:= GV.PMConfig.GasFlowPressureWarningRange, 
	TIME_ALARM:= GV.PMConfig.GasFlowPressureAlarmTime, 
	TIME_WARNING:= GV.PMConfig.GasFlowPressureWarningTime, 
	ALARM=> , 
	WARNING=> );
	
	RANGE_PG_PS5(
	ENABLE:=TRUE,
	SV:= 270,
	PV:= GV.AI.PG_PS5_VALUE, 
	RANGE_ALARM_H:= GV.PMConfig.GasFlowPressureAlarmRange, 
	RANGE_ALARM_L:= GV.PMConfig.GasFlowPressureAlarmRange, 
	RANGE_WARNING_H:= GV.PMConfig.GasFlowPressureWarningRange, 
	RANGE_WARNING_L:= GV.PMConfig.GasFlowPressureWarningRange, 
	TIME_ALARM:= GV.PMConfig.GasFlowPressureAlarmTime, 
	TIME_WARNING:= GV.PMConfig.GasFlowPressureWarningTime, 
	ALARM=> , 
	WARNING=> );
	
	RANGE_PG_PS6(
	ENABLE:=TRUE,
	SV:=270,
	PV:= GV.AI.PG_PS6_VALUE, 
	RANGE_ALARM_H:= GV.PMConfig.GasFlowPressureAlarmRange, 
	RANGE_ALARM_L:= GV.PMConfig.GasFlowPressureAlarmRange, 
	RANGE_WARNING_H:= GV.PMConfig.GasFlowPressureWarningRange, 
	RANGE_WARNING_L:= GV.PMConfig.GasFlowPressureWarningRange, 
	TIME_ALARM:= GV.PMConfig.GasFlowPressureAlarmTime, 
	TIME_WARNING:= GV.PMConfig.GasFlowPressureWarningTime, 
	ALARM=> , 
	WARNING=> );
	
	RANGE_PG_PS7(
	ENABLE:=TRUE,
	PV:= GV.AI.PG_PS7_VALUE, 
	RANGE_ALARM_H:= GV.PMConfig.GasFlowPressureAlarmRange, 
	RANGE_ALARM_L:= GV.PMConfig.GasFlowPressureAlarmRange, 
	RANGE_WARNING_H:= GV.PMConfig.GasFlowPressureWarningRange, 
	RANGE_WARNING_L:= GV.PMConfig.GasFlowPressureWarningRange, 
	TIME_ALARM:= GV.PMConfig.GasFlowPressureAlarmTime, 
	TIME_WARNING:= GV.PMConfig.GasFlowPressureWarningTime, 
	ALARM=> , 
	WARNING=> );
	
	RANGE_PG_PS8(
	ENABLE:=TRUE,
	PV:= GV.AI.PG_PS8_VALUE, 
	RANGE_ALARM_H:= GV.PMConfig.GasFlowPressureAlarmRange, 
	RANGE_ALARM_L:= GV.PMConfig.GasFlowPressureAlarmRange, 
	RANGE_WARNING_H:= GV.PMConfig.GasFlowPressureWarningRange, 
	RANGE_WARNING_L:= GV.PMConfig.GasFlowPressureWarningRange, 
	TIME_ALARM:= GV.PMConfig.GasFlowPressureAlarmTime, 
	TIME_WARNING:= GV.PMConfig.GasFlowPressureWarningTime, 
	ALARM=> , 
	WARNING=> );
	
	RANGE_PG_PS9(
	ENABLE:=TRUE,
	PV:= GV.AI.PG_PS9_VALUE, 
	RANGE_ALARM_H:= GV.PMConfig.GasFlowPressureAlarmRange, 
	RANGE_ALARM_L:= GV.PMConfig.GasFlowPressureAlarmRange, 
	RANGE_WARNING_H:= GV.PMConfig.GasFlowPressureWarningRange, 
	RANGE_WARNING_L:= GV.PMConfig.GasFlowPressureWarningRange, 
	TIME_ALARM:= GV.PMConfig.GasFlowPressureAlarmTime, 
	TIME_WARNING:= GV.PMConfig.GasFlowPressureWarningTime, 
	ALARM=> , 
	WARNING=> );
	
	PM.INFO.Alarm.Gas1FlowPressureOutOfRange:=  RANGE_PG_PS1.ALARM;
	PM.INFO.Alarm.Gas2FlowPressureOutOfRange:=  RANGE_PG_PS2.ALARM;
	PM.INFO.Alarm.Gas3FlowPressureOutOfRange:=  RANGE_PG_PS3.ALARM;	
	PM.INFO.Alarm.Gas4FlowPressureOutOfRange:=  RANGE_PG_PS4.ALARM OR TRUE;
	PM.INFO.Alarm.Gas5FlowPressureOutOfRange:=  RANGE_PG_PS5.ALARM;
	PM.INFO.Alarm.Gas6FlowPressureOutOfRange:=  RANGE_PG_PS6.ALARM;
	//PM.INFO.Alarm.Gas7FlowPressureOutOfRange:=  RANGE_PG_PS7.ALARM;
	//PM.INFO.Alarm.Gas8FlowPressureOutOfRange:=  RANGE_PG_PS8.ALARM;
	//PM.INFO.Alarm.Gas9FlowPressureOutOfRange:=  RANGE_PG_PS9.ALARM;

	PM.INFO.warning.Gas1FlowPressureOutOfRange:=  RANGE_PG_PS1.warning;
	PM.INFO.warning.Gas2FlowPressureOutOfRange:=  RANGE_PG_PS2.warning;
	PM.INFO.warning.Gas3FlowPressureOutOfRange:=  RANGE_PG_PS3.warning;
	PM.INFO.warning.Gas4FlowPressureOutOfRange:=  RANGE_PG_PS4.warning;
	PM.INFO.warning.Gas5FlowPressureOutOfRange:=  RANGE_PG_PS5.warning;
	PM.INFO.warning.Gas6FlowPressureOutOfRange:=  RANGE_PG_PS6.warning;
	//PM.INFO.warning.Gas7FlowPressureOutOfRange:=  RANGE_PG_PS7.warning;
	//PM.INFO.warning.Gas8FlowPressureOutOfRange:=  RANGE_PG_PS8.warning;
	//PM.INFO.warning.Gas9FlowPressureOutOfRange:=  RANGE_PG_PS9.warning;
END_ACTION

ACTION SPLC:
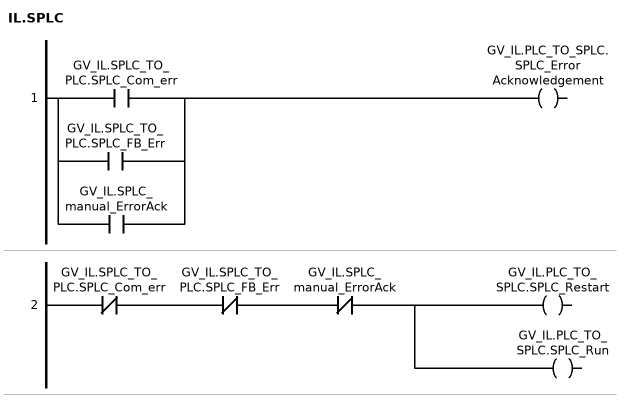
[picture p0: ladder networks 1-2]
// NETWORK 1
GV_IL.PLC_TO_SPLC.SPLC_ErrorAcknowledgement := GV_IL.SPLC_TO_PLC.SPLC_Com_err OR GV_IL.SPLC_TO_PLC.SPLC_FB_Err OR GV_IL.SPLC_manual_ErrorAck;

// NETWORK 2
_w1 := NOT GV_IL.SPLC_TO_PLC.SPLC_Com_err AND NOT GV_IL.SPLC_TO_PLC.SPLC_FB_Err AND NOT GV_IL.SPLC_manual_ErrorAck;
GV_IL.PLC_TO_SPLC.SPLC_Restart := _w1;
GV_IL.PLC_TO_SPLC.SPLC_Run := _w1;
END_ACTION

ACTION SYS:
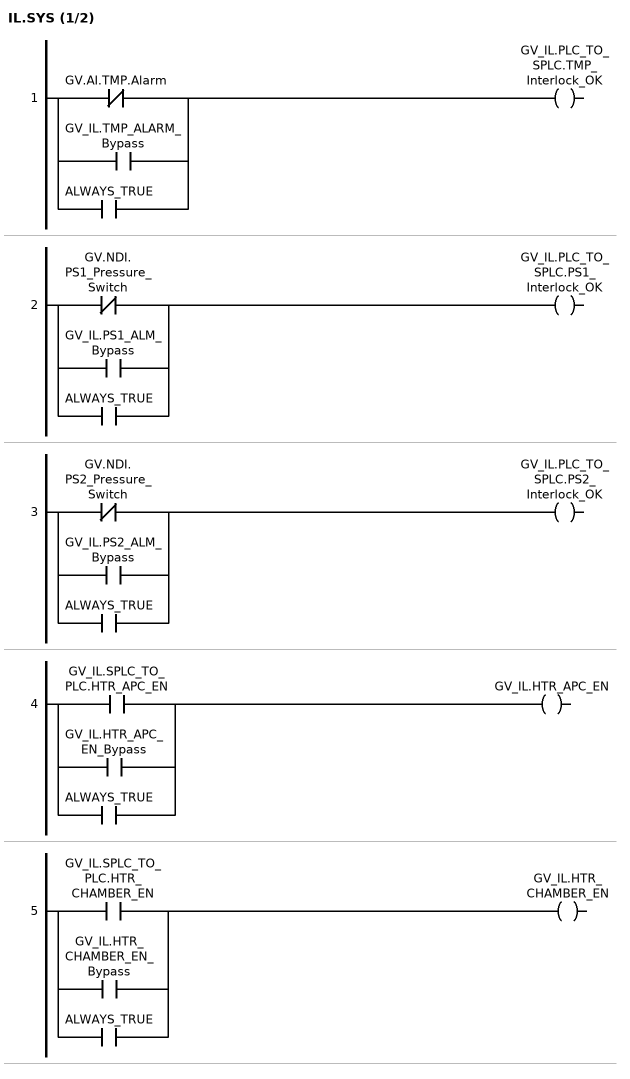
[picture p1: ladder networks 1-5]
// NETWORK 1
GV_IL.PLC_TO_SPLC.TMP_Interlock_OK := NOT GV.AI.TMP.Alarm OR GV_IL.TMP_ALARM_Bypass OR ALWAYS_TRUE;

// NETWORK 2
GV_IL.PLC_TO_SPLC.PS1_Interlock_OK := NOT (GV.NDI.	PS1_Pressure_Switch) OR GV_IL.PS1_ALM_Bypass OR ALWAYS_TRUE;

// NETWORK 3
GV_IL.PLC_TO_SPLC.PS2_Interlock_OK := NOT (GV.NDI.	PS2_Pressure_Switch) OR GV_IL.PS2_ALM_Bypass OR ALWAYS_TRUE;

// NETWORK 4
GV_IL.HTR_APC_EN := GV_IL.SPLC_TO_PLC.HTR_APC_EN OR GV_IL.HTR_APC_EN_Bypass OR ALWAYS_TRUE;

// NETWORK 5
GV_IL.HTR_CHAMBER_EN := GV_IL.SPLC_TO_PLC.HTR_CHAMBER_EN OR GV_IL.HTR_CHAMBER_EN_Bypass OR ALWAYS_TRUE;

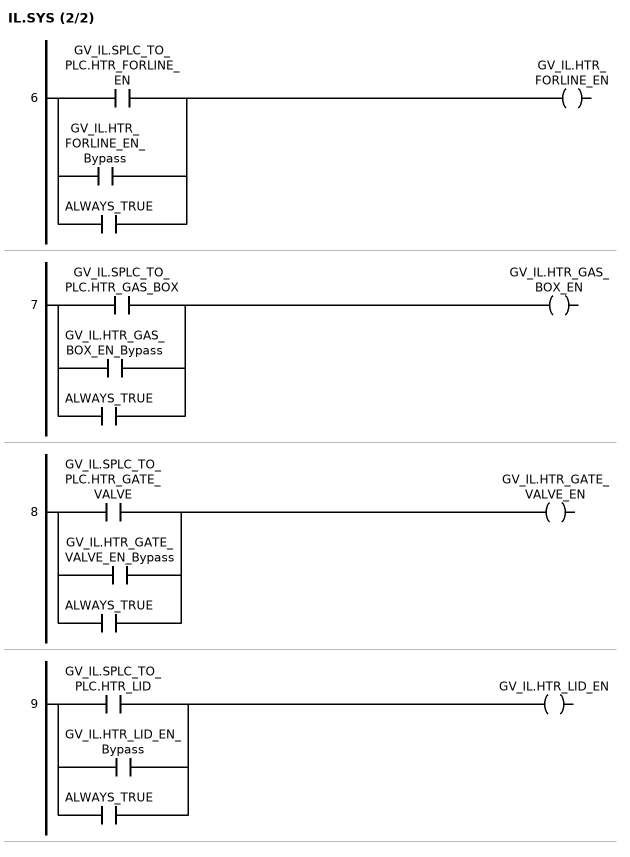
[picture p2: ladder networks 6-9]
// NETWORK 6
GV_IL.HTR_FORLINE_EN := GV_IL.SPLC_TO_PLC.HTR_FORLINE_EN OR GV_IL.HTR_FORLINE_EN_Bypass OR ALWAYS_TRUE;

// NETWORK 7
GV_IL.HTR_GAS_BOX_EN := GV_IL.SPLC_TO_PLC.HTR_GAS_BOX OR GV_IL.HTR_GAS_BOX_EN_Bypass OR ALWAYS_TRUE;

// NETWORK 8
GV_IL.HTR_GATE_VALVE_EN := GV_IL.SPLC_TO_PLC.HTR_GATE_VALVE OR GV_IL.HTR_GATE_VALVE_EN_Bypass OR ALWAYS_TRUE;

// NETWORK 9
GV_IL.HTR_LID_EN := GV_IL.SPLC_TO_PLC.HTR_LID OR GV_IL.HTR_LID_EN_Bypass OR ALWAYS_TRUE;
END_ACTION

ACTION Temp:
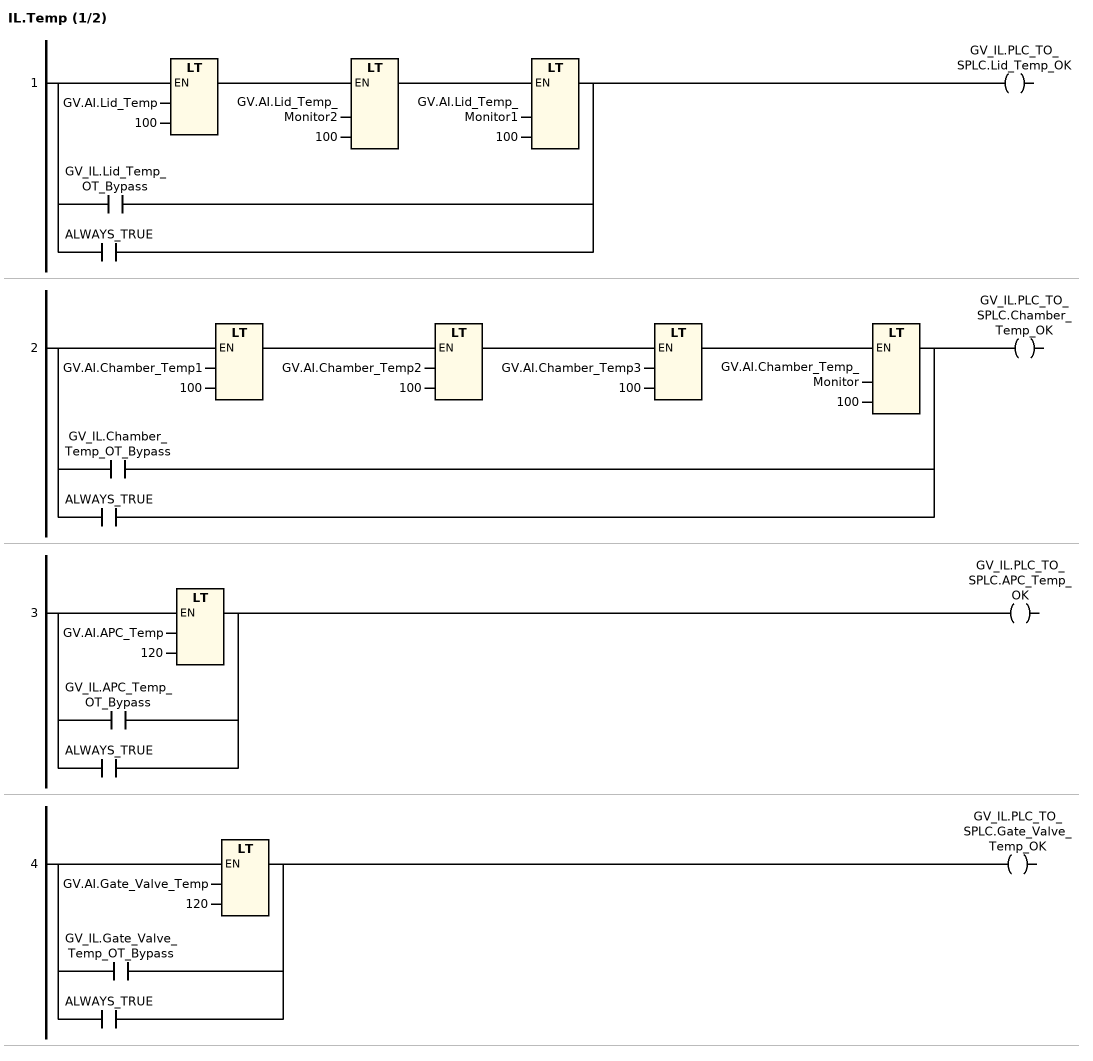
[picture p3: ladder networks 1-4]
// NETWORK 1
_w2 := GV_IL.Lid_Temp_OT_Bypass OR ALWAYS_TRUE;
IF NOT _w2 THEN
    _w2 := GV.AI.Lid_Temp < 100 AND GV.AI.Lid_Temp_Monitor2 < 100 AND GV.AI.Lid_Temp_Monitor1 < 100;
END_IF
GV_IL.PLC_TO_SPLC.Lid_Temp_OK := _w2;

// NETWORK 2
_w3 := GV_IL.Chamber_Temp_OT_Bypass OR ALWAYS_TRUE;
IF NOT _w3 THEN
    _w3 := GV.AI.Chamber_Temp1 < 100 AND GV.AI.Chamber_Temp2 < 100 AND GV.AI.Chamber_Temp3 < 100 AND GV.AI.Chamber_Temp_Monitor < 100;
END_IF
GV_IL.PLC_TO_SPLC.Chamber_Temp_OK := _w3;

// NETWORK 3
_w4 := GV_IL.APC_Temp_OT_Bypass OR ALWAYS_TRUE;
IF NOT _w4 THEN
    _w4 := GV.AI.APC_Temp < 120;
END_IF
GV_IL.PLC_TO_SPLC.APC_Temp_OK := _w4;

// NETWORK 4
_w5 := GV_IL.Gate_Valve_Temp_OT_Bypass OR ALWAYS_TRUE;
IF NOT _w5 THEN
    _w5 := GV.AI.Gate_Valve_Temp < 120;
END_IF
GV_IL.PLC_TO_SPLC.Gate_Valve_Temp_OK := _w5;

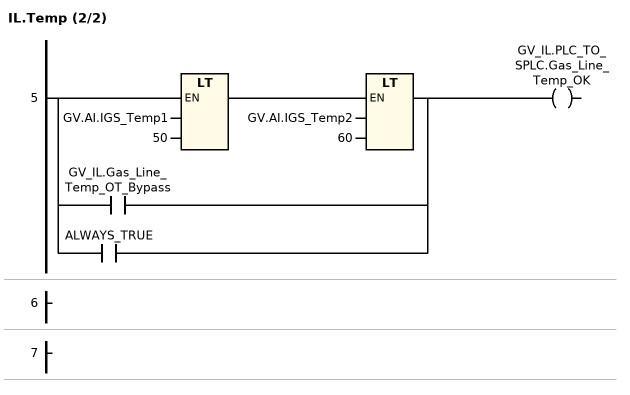
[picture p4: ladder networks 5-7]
// NETWORK 5
_w6 := GV_IL.Gas_Line_Temp_OT_Bypass OR ALWAYS_TRUE;
IF NOT _w6 THEN
    _w6 := GV.AI.IGS_Temp1 < 50 AND GV.AI.IGS_Temp2 < 60;
END_IF
GV_IL.PLC_TO_SPLC.Gas_Line_Temp_OK := _w6;

// NETWORK 6

// NETWORK 7
END_ACTION

ACTION VALVE:
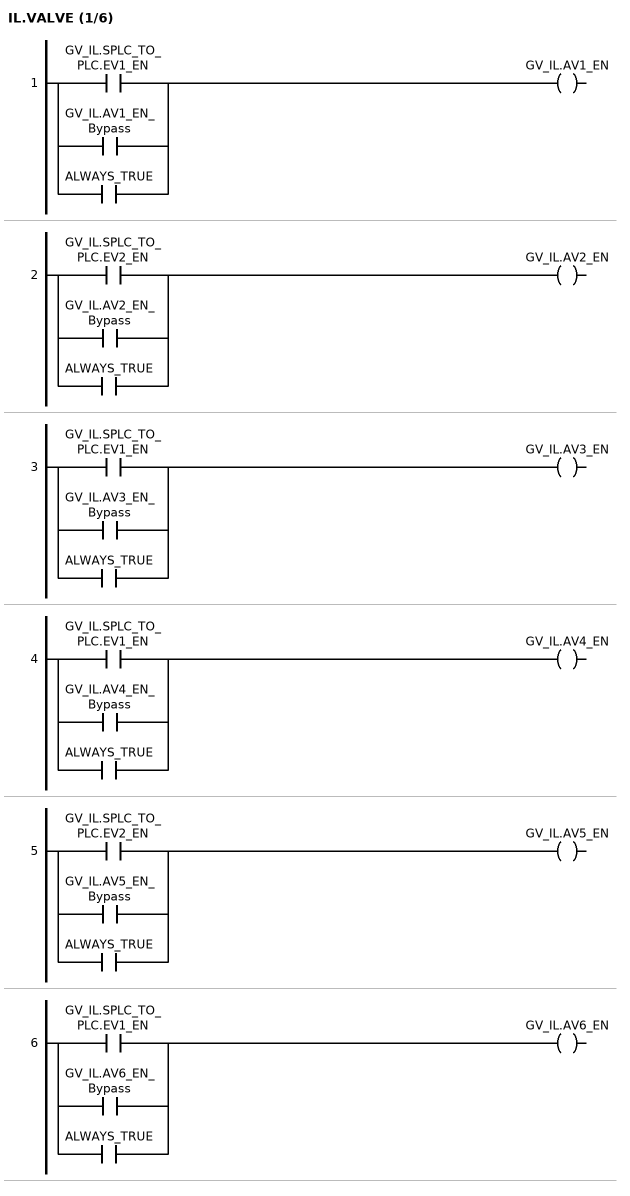
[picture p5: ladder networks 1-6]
// NETWORK 1
GV_IL.AV1_EN := GV_IL.SPLC_TO_PLC.EV1_EN OR GV_IL.AV1_EN_Bypass OR ALWAYS_TRUE;

// NETWORK 2
GV_IL.AV2_EN := GV_IL.SPLC_TO_PLC.EV2_EN OR GV_IL.AV2_EN_Bypass OR ALWAYS_TRUE;

// NETWORK 3
GV_IL.AV3_EN := GV_IL.SPLC_TO_PLC.EV1_EN OR GV_IL.AV3_EN_Bypass OR ALWAYS_TRUE;

// NETWORK 4
GV_IL.AV4_EN := GV_IL.SPLC_TO_PLC.EV1_EN OR GV_IL.AV4_EN_Bypass OR ALWAYS_TRUE;

// NETWORK 5
GV_IL.AV5_EN := GV_IL.SPLC_TO_PLC.EV2_EN OR GV_IL.AV5_EN_Bypass OR ALWAYS_TRUE;

// NETWORK 6
GV_IL.AV6_EN := GV_IL.SPLC_TO_PLC.EV1_EN OR GV_IL.AV6_EN_Bypass OR ALWAYS_TRUE;

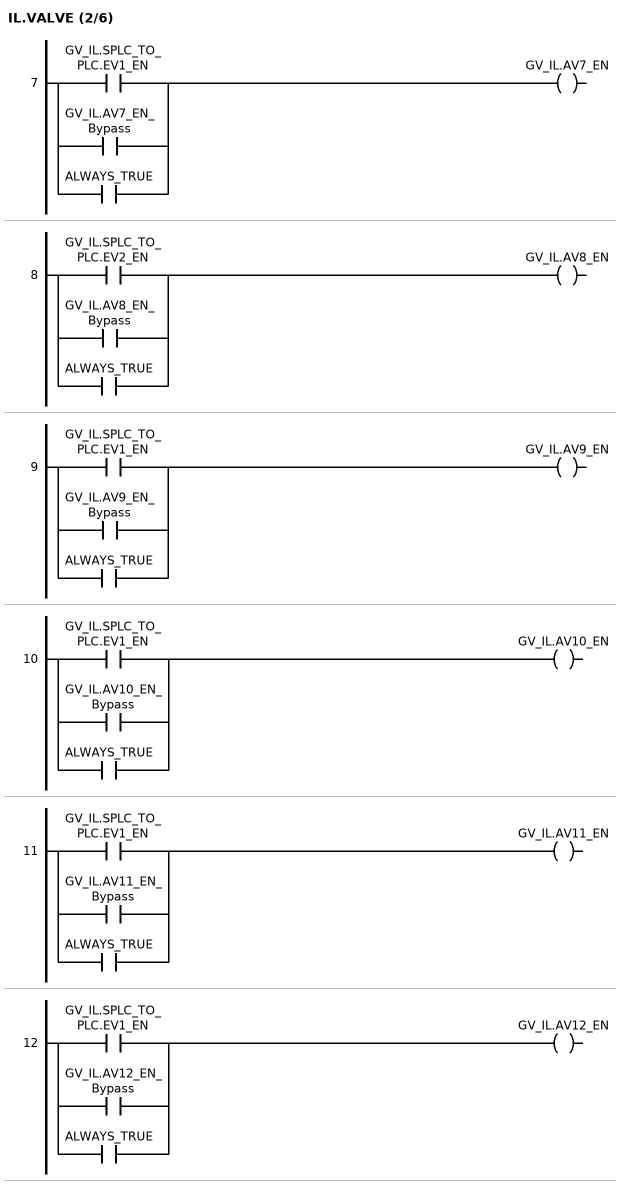
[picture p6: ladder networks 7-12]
// NETWORK 7
GV_IL.AV7_EN := GV_IL.SPLC_TO_PLC.EV1_EN OR GV_IL.AV7_EN_Bypass OR ALWAYS_TRUE;

// NETWORK 8
GV_IL.AV8_EN := GV_IL.SPLC_TO_PLC.EV2_EN OR GV_IL.AV8_EN_Bypass OR ALWAYS_TRUE;

// NETWORK 9
GV_IL.AV9_EN := GV_IL.SPLC_TO_PLC.EV1_EN OR GV_IL.AV9_EN_Bypass OR ALWAYS_TRUE;

// NETWORK 10
GV_IL.AV10_EN := GV_IL.SPLC_TO_PLC.EV1_EN OR GV_IL.AV10_EN_Bypass OR ALWAYS_TRUE;

// NETWORK 11
GV_IL.AV11_EN := GV_IL.SPLC_TO_PLC.EV1_EN OR GV_IL.AV11_EN_Bypass OR ALWAYS_TRUE;

// NETWORK 12
GV_IL.AV12_EN := GV_IL.SPLC_TO_PLC.EV1_EN OR GV_IL.AV12_EN_Bypass OR ALWAYS_TRUE;

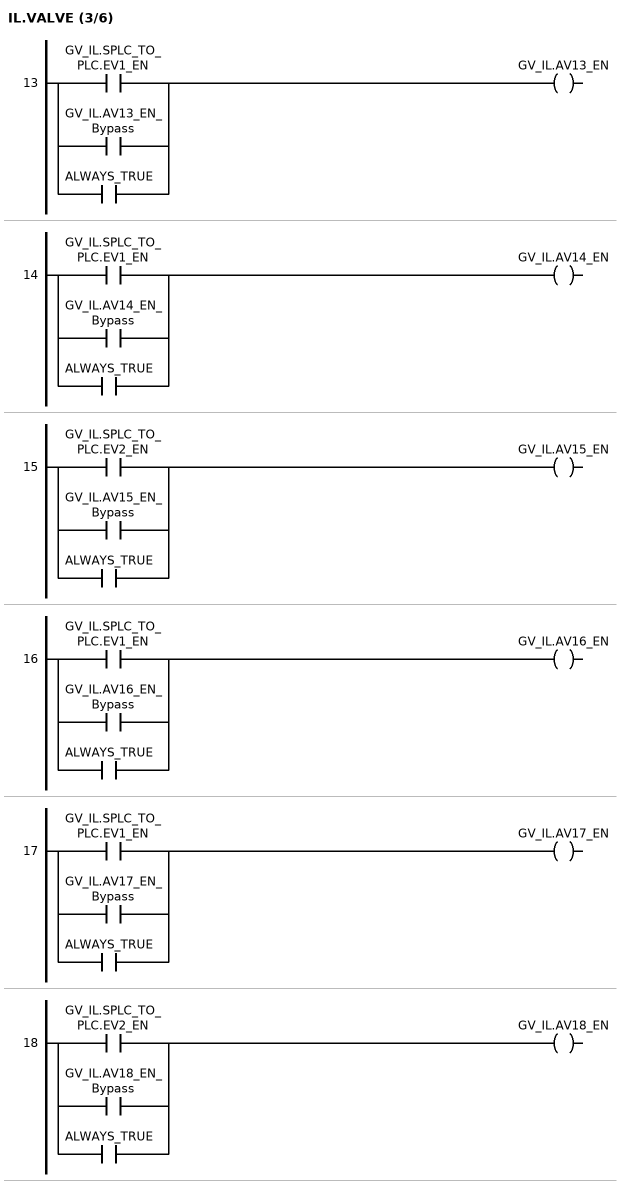
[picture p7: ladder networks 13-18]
// NETWORK 13
GV_IL.AV13_EN := GV_IL.SPLC_TO_PLC.EV1_EN OR GV_IL.AV13_EN_Bypass OR ALWAYS_TRUE;

// NETWORK 14
GV_IL.AV14_EN := GV_IL.SPLC_TO_PLC.EV1_EN OR GV_IL.AV14_EN_Bypass OR ALWAYS_TRUE;

// NETWORK 15
GV_IL.AV15_EN := GV_IL.SPLC_TO_PLC.EV2_EN OR GV_IL.AV15_EN_Bypass OR ALWAYS_TRUE;

// NETWORK 16
GV_IL.AV16_EN := GV_IL.SPLC_TO_PLC.EV1_EN OR GV_IL.AV16_EN_Bypass OR ALWAYS_TRUE;

// NETWORK 17
GV_IL.AV17_EN := GV_IL.SPLC_TO_PLC.EV1_EN OR GV_IL.AV17_EN_Bypass OR ALWAYS_TRUE;

// NETWORK 18
GV_IL.AV18_EN := GV_IL.SPLC_TO_PLC.EV2_EN OR GV_IL.AV18_EN_Bypass OR ALWAYS_TRUE;

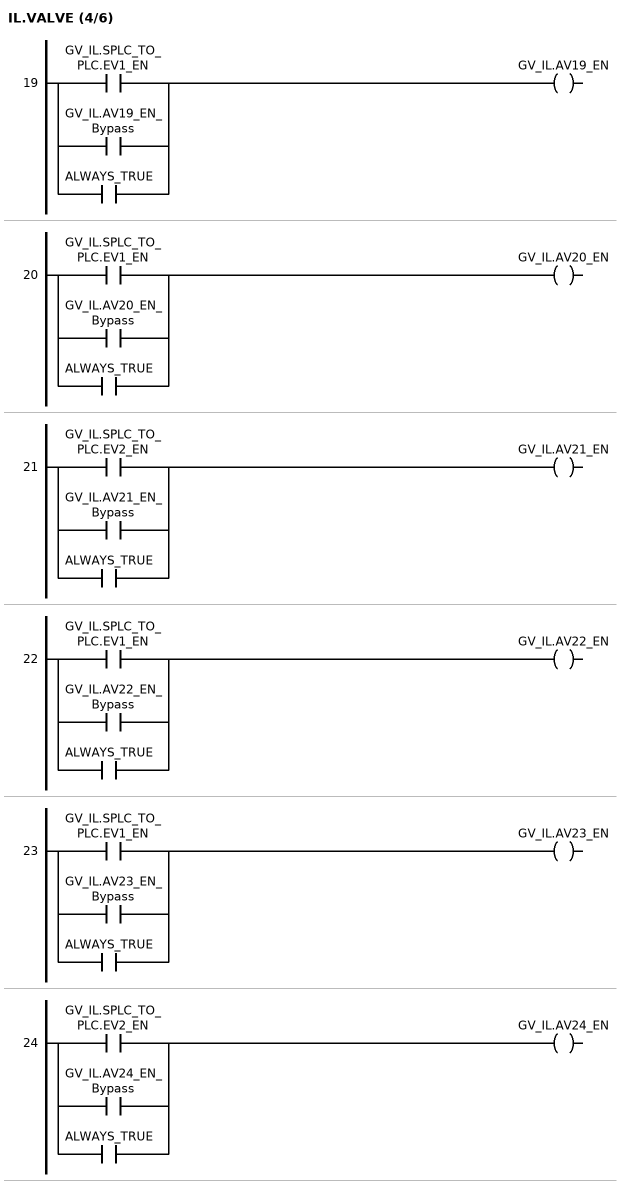
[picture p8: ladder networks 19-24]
// NETWORK 19
GV_IL.AV19_EN := GV_IL.SPLC_TO_PLC.EV1_EN OR GV_IL.AV19_EN_Bypass OR ALWAYS_TRUE;

// NETWORK 20
GV_IL.AV20_EN := GV_IL.SPLC_TO_PLC.EV1_EN OR GV_IL.AV20_EN_Bypass OR ALWAYS_TRUE;

// NETWORK 21
GV_IL.AV21_EN := GV_IL.SPLC_TO_PLC.EV2_EN OR GV_IL.AV21_EN_Bypass OR ALWAYS_TRUE;

// NETWORK 22
GV_IL.AV22_EN := GV_IL.SPLC_TO_PLC.EV1_EN OR GV_IL.AV22_EN_Bypass OR ALWAYS_TRUE;

// NETWORK 23
GV_IL.AV23_EN := GV_IL.SPLC_TO_PLC.EV1_EN OR GV_IL.AV23_EN_Bypass OR ALWAYS_TRUE;

// NETWORK 24
GV_IL.AV24_EN := GV_IL.SPLC_TO_PLC.EV2_EN OR GV_IL.AV24_EN_Bypass OR ALWAYS_TRUE;

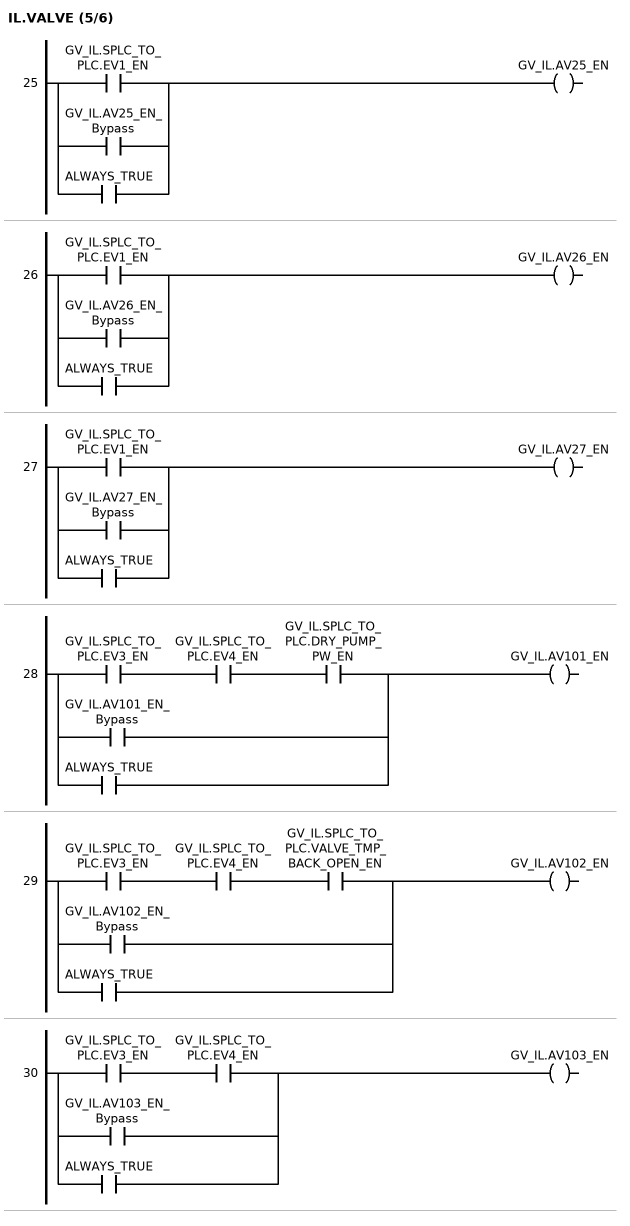
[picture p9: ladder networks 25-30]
// NETWORK 25
GV_IL.AV25_EN := GV_IL.SPLC_TO_PLC.EV1_EN OR GV_IL.AV25_EN_Bypass OR ALWAYS_TRUE;

// NETWORK 26
GV_IL.AV26_EN := GV_IL.SPLC_TO_PLC.EV1_EN OR GV_IL.AV26_EN_Bypass OR ALWAYS_TRUE;

// NETWORK 27
GV_IL.AV27_EN := GV_IL.SPLC_TO_PLC.EV1_EN OR GV_IL.AV27_EN_Bypass OR ALWAYS_TRUE;

// NETWORK 28
GV_IL.AV101_EN := GV_IL.SPLC_TO_PLC.EV3_EN AND GV_IL.SPLC_TO_PLC.EV4_EN AND GV_IL.SPLC_TO_PLC.DRY_PUMP_PW_EN OR GV_IL.AV101_EN_Bypass OR ALWAYS_TRUE;

// NETWORK 29
GV_IL.AV102_EN := GV_IL.SPLC_TO_PLC.EV3_EN AND GV_IL.SPLC_TO_PLC.EV4_EN AND GV_IL.SPLC_TO_PLC.VALVE_TMP_BACK_OPEN_EN OR GV_IL.AV102_EN_Bypass OR ALWAYS_TRUE;

// NETWORK 30
GV_IL.AV103_EN := GV_IL.SPLC_TO_PLC.EV3_EN AND GV_IL.SPLC_TO_PLC.EV4_EN OR GV_IL.AV103_EN_Bypass OR ALWAYS_TRUE;

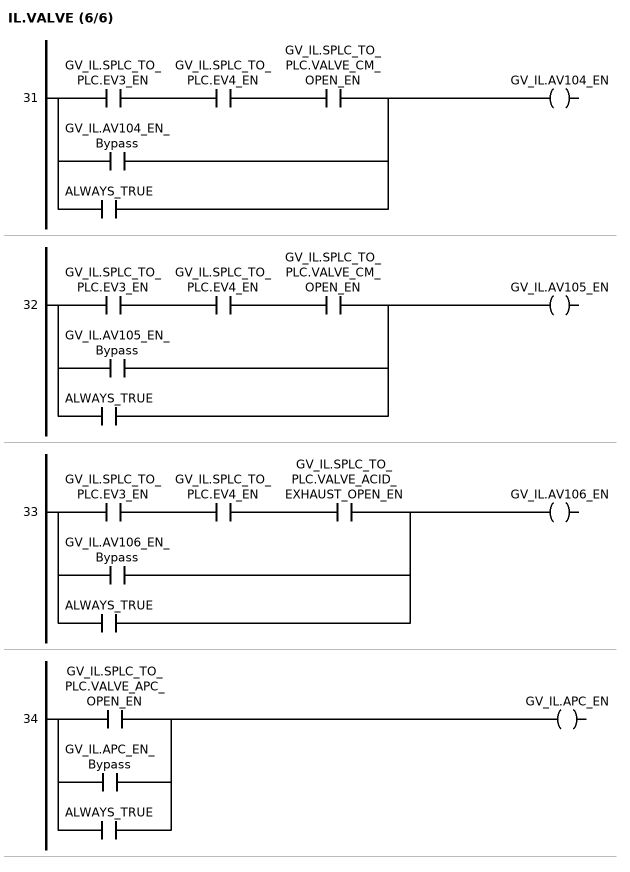
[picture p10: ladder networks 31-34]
// NETWORK 31
GV_IL.AV104_EN := GV_IL.SPLC_TO_PLC.EV3_EN AND GV_IL.SPLC_TO_PLC.EV4_EN AND GV_IL.SPLC_TO_PLC.VALVE_CM_OPEN_EN OR GV_IL.AV104_EN_Bypass OR ALWAYS_TRUE;

// NETWORK 32
GV_IL.AV105_EN := GV_IL.SPLC_TO_PLC.EV3_EN AND GV_IL.SPLC_TO_PLC.EV4_EN AND GV_IL.SPLC_TO_PLC.VALVE_CM_OPEN_EN OR GV_IL.AV105_EN_Bypass OR ALWAYS_TRUE;

// NETWORK 33
GV_IL.AV106_EN := GV_IL.SPLC_TO_PLC.EV3_EN AND GV_IL.SPLC_TO_PLC.EV4_EN AND GV_IL.SPLC_TO_PLC.VALVE_ACID_EXHAUST_OPEN_EN OR GV_IL.AV106_EN_Bypass OR ALWAYS_TRUE;

// NETWORK 34
GV_IL.APC_EN := GV_IL.SPLC_TO_PLC.VALVE_APC_OPEN_EN OR GV_IL.APC_EN_Bypass OR ALWAYS_TRUE;
END_ACTION

END_PROGRAM

// ---- POUs/FB/RANGEJD.TcPOU
FUNCTION_BLOCK RANGEJD
VAR_INPUT
	ENABLE:BOOL;
	SV:LREAL;
	PV:LREAL;
	RANGE_ALARM_H:LREAL;
	RANGE_ALARM_L:LREAL;
	RANGE_WARNING_H:LREAL;
	RANGE_WARNING_L:LREAL;
	TIME_ALARM:LREAL;
	TIME_WARNING:LREAL;
	
END_VAR
VAR_OUTPUT
	ALARM:BOOL;
	WARNING:BOOL;
END_VAR
VAR
	TON_ALARM:TON;
	TON_WARNING:TON;
	STATUS_ALARM:BOOL;
	STATUS_WARNING:BOOL;
END_VAR

IF ENABLE
	THEN	
	IF PV	>=	(SV+RANGE_ALARM_H) OR 	PV	<=	(SV-RANGE_ALARM_L)
		THEN	STATUS_ALARM:=TRUE;
		ELSE	STATUS_ALARM:=FALSE;
	END_IF		
	
	IF PV	>=	(SV+RANGE_WARNING_H) OR 	PV	<=	(SV-RANGE_WARNING_L)
		THEN	STATUS_WARNING:=TRUE;
		ELSE	STATUS_WARNING:=FALSE;
	END_IF	
	
	TON_ALARM(IN:=STATUS_ALARM , PT:= LREAL_TO_TIME(TIME_ALARM)*1000, Q=> , ET=> );		
	IF TON_ALARM.Q		
		THEN	
		ALARM:=FALSE;	
		ELSE	
		ALARM:=TRUE;	
	END_IF	
	
	TON_WARNING(IN:=STATUS_WARNING , PT:= LREAL_TO_TIME(TIME_WARNING)*1000, Q=> , ET=> );		
	IF TON_WARNING.Q		
		THEN	
		WARNING:=FALSE;	
		ELSE	
		WARNING:=TRUE;	
	END_IF	

	ELSE
		STATUS_ALARM:=FALSE;
		STATUS_WARNING:=FALSE;
		ALARM:=TRUE;
		WARNING:=TRUE;	
END_IF
	
	IF NOT ENABLE
	THEN
	STATUS_ALARM:=TRUE;
	STATUS_WARNING:=TRUE;
	END_IF

END_FUNCTION_BLOCK

// ---- POUs/PRG/Temp.TcPOU
PROGRAM Temp
VAR
	H_LID				:ARRAY[1..10] OF Temp_controller;
	H_CHAMBER			:ARRAY[1..10] OF Temp_controller;
	H_PEN_VALVE			:Temp_controller;
	H_GATE_VALVE		:Temp_controller;
	H_IGS				:ARRAY[1..10] OF Temp_controller;
	H_TAPE				:ARRAY[1..10] OF Temp_controller;
	H_FORELINE			:ARRAY[1..20] OF Temp_controller;	
END_VAR

//E01 PEN_VALVE PID		
	IF 	GV.AI.APC_Temp-GV.AO.APC_Temp_SV<3	
	THEN 
		H_PEN_VALVE.PID_Feedforward:=GV_H.PEN_VALVE_HEATER_PID.Feedforward;
	ELSE
		H_PEN_VALVE.PID_Feedforward:=0;
	END_IF	
	H_PEN_VALVE(
		ENABLE:= GV.AI.APC_Temp<110, 
		AUTO_TUNE:= GV.PEN_VALVE_HEATER_AUTO_TUNE_EN, 
		AUTO_TUNE_OUTPUT:=GV.PEN_VALVE_HEATER_AUTO_TUNE_OUTPUT,
		TEMP_SV:= GV.AO.APC_Temp_SV, 
		TEMP_ACTUAL:= GV.AI.APC_Temp, 
		TEMP_RATE:=5,
		PID_P:= GV_H.PEN_VALVE_HEATER_PID.P, 
		PID_I:= GV_H.PEN_VALVE_HEATER_PID.I, 
		PID_D:= GV_H.PEN_VALVE_HEATER_PID.D, 
		PID_Dp:= GV_H.PEN_VALVE_HEATER_PID.DP,
		PID_Output_Limit:= GV_H.PEN_VALVE_HEATER_PID.Output_Limit,
		SSR_ON=> GV.PEN_VALVE_HEATER_SSR_ON
	);		
	IF H_PEN_VALVE.PID_AUTO_TUNE_DONE
		THEN
		GV_H.PEN_VALVE_HEATER_PID.P:=H_PEN_VALVE.PID_AUTO_TUNE_P;
		GV_H.PEN_VALVE_HEATER_PID.I:=H_PEN_VALVE.PID_AUTO_TUNE_I;
		GV_H.PEN_VALVE_HEATER_PID.D:=H_PEN_VALVE.PID_AUTO_TUNE_D;
		GV.PEN_VALVE_HEATER_AUTO_TUNE_EN:=FALSE;
	END_IF
	
//E02 LID1 PID
	H_LID[1](
	ENABLE:= GV.AI.Lid_Temp<100, 
	AUTO_TUNE:= GV.LID_HEATER_AUTO_TUNE_EN[1], 
	AUTO_TUNE_OUTPUT:=GV.LID_HEATER_AUTO_TUNE_OUTPUT[1],
	TEMP_SV:= GV.AO.LID_Temp_SV, 
	TEMP_ACTUAL:= GV.AI.Lid_Temp, 
	TEMP_RATE:=5,
	PID_P:= GV_H.LID_HEATER_PID[1].P, 
	PID_I:= GV_H.LID_HEATER_PID[1].I, 
	PID_D:= GV_H.LID_HEATER_PID[1].D, 
	PID_Dp:= GV_H.LID_HEATER_PID[1].DP, 
	PID_Feedforward:= GV_H.LID_HEATER_PID[1].Feedforward,
	PID_Output_Limit:= GV_H.LID_HEATER_PID[1].Output_Limit,
	SSR_ON=> GV.LID_HEATER_SSR_ON[1],
	SSR_ON=> GV.LID_HEATER_SSR_ON[2],
	SSR_ON=> GV.LID_HEATER_SSR_ON[3],
	SSR_ON=> GV.LID_HEATER_SSR_ON[4]
	);	
	IF H_LID[1].PID_AUTO_TUNE_DONE
		THEN
		GV_H.LID_HEATER_PID[1].P:=H_LID[1].PID_AUTO_TUNE_P;
		GV_H.LID_HEATER_PID[1].I:=H_LID[1].PID_AUTO_TUNE_I;
		GV_H.LID_HEATER_PID[1].D:=H_LID[1].PID_AUTO_TUNE_D;
		GV.LID_HEATER_AUTO_TUNE_EN[1]:=FALSE;
	END_IF
//E06 CHAMBER1 PID
	H_CHAMBER[1](
	ENABLE:= GV.AI.CHAMBER_Temp1<100, 
	AUTO_TUNE:= GV.CHAMBER_HEATER_AUTO_TUNE_EN[1], 
	AUTO_TUNE_OUTPUT:=GV.CHAMBER_HEATER_AUTO_TUNE_OUTPUT[1],
	TEMP_SV:= GV.AO.Chamber_Temp1_SV, 
	TEMP_ACTUAL:= GV.AI.CHAMBER_Temp1, 
	TEMP_RATE:=5,
	PID_P:= GV_H.CHAMBER_HEATER_PID[1].P, 
	PID_I:= GV_H.CHAMBER_HEATER_PID[1].I, 
	PID_D:= GV_H.CHAMBER_HEATER_PID[1].D, 
	PID_Dp:= GV_H.CHAMBER_HEATER_PID[1].DP, 
	PID_Feedforward:= GV_H.CHAMBER_HEATER_PID[1].Feedforward,
	PID_Output_Limit:= GV_H.CHAMBER_HEATER_PID[1].Output_Limit,
	SSR_ON=> GV.CHAMBER_HEATER_SSR_ON[1],
	SSR_ON=> GV.CHAMBER_HEATER_SSR_ON[2]
	);	
	IF H_CHAMBER[1].PID_AUTO_TUNE_DONE
		THEN
		GV_H.CHAMBER_HEATER_PID[1].P:=H_CHAMBER[1].PID_AUTO_TUNE_P;
		GV_H.CHAMBER_HEATER_PID[1].I:=H_CHAMBER[1].PID_AUTO_TUNE_I;
		GV_H.CHAMBER_HEATER_PID[1].D:=H_CHAMBER[1].PID_AUTO_TUNE_D;
		GV.CHAMBER_HEATER_AUTO_TUNE_EN[1]:=FALSE;
	END_IF
//E07 CHAMBER2 PID	
	H_CHAMBER[2](
	ENABLE:= GV.AI.CHAMBER_Temp2<100, 
	AUTO_TUNE:= GV.CHAMBER_HEATER_AUTO_TUNE_EN[2], 
	AUTO_TUNE_OUTPUT:=GV.CHAMBER_HEATER_AUTO_TUNE_OUTPUT[2],
	TEMP_SV:= GV.AO.Chamber_Temp2_SV, 
	TEMP_ACTUAL:= GV.AI.CHAMBER_Temp2, 
	TEMP_RATE:=5,
	PID_P:= GV_H.CHAMBER_HEATER_PID[2].P, 
	PID_I:= GV_H.CHAMBER_HEATER_PID[2].I, 
	PID_D:= GV_H.CHAMBER_HEATER_PID[2].D, 
	PID_Dp:= GV_H.CHAMBER_HEATER_PID[2].DP, 
	PID_Feedforward:= GV_H.CHAMBER_HEATER_PID[2].Feedforward,
	PID_Output_Limit:= GV_H.CHAMBER_HEATER_PID[2].Output_Limit,
	SSR_ON=> GV.CHAMBER_HEATER_SSR_ON[3]
	);	
	IF H_CHAMBER[2].PID_AUTO_TUNE_DONE
		THEN
		GV_H.CHAMBER_HEATER_PID[2].P:=H_CHAMBER[2].PID_AUTO_TUNE_P;
		GV_H.CHAMBER_HEATER_PID[2].I:=H_CHAMBER[2].PID_AUTO_TUNE_I;
		GV_H.CHAMBER_HEATER_PID[2].D:=H_CHAMBER[2].PID_AUTO_TUNE_D;
		GV.CHAMBER_HEATER_AUTO_TUNE_EN[2]:=FALSE;
	END_IF
//E08 CHAMBER3 PID		
	H_CHAMBER[3](
	ENABLE:= GV.AI.CHAMBER_Temp3<100, 
	AUTO_TUNE:= GV.CHAMBER_HEATER_AUTO_TUNE_EN[3], 
	AUTO_TUNE_OUTPUT:=GV.CHAMBER_HEATER_AUTO_TUNE_OUTPUT[3],
	TEMP_SV:= GV.AO.Chamber_Temp3_SV, 
	TEMP_ACTUAL:= GV.AI.Chamber_Temp3, 
	TEMP_RATE:=5,
	PID_P:= GV_H.CHAMBER_HEATER_PID[3].P, 
	PID_I:= GV_H.CHAMBER_HEATER_PID[3].I, 
	PID_D:= GV_H.CHAMBER_HEATER_PID[3].D, 
	PID_Dp:= GV_H.CHAMBER_HEATER_PID[3].DP,
	PID_Feedforward:= GV_H.CHAMBER_HEATER_PID[3].Feedforward,
	PID_Output_Limit:= GV_H.CHAMBER_HEATER_PID[3].Output_Limit,
	SSR_ON=> GV.CHAMBER_HEATER_SSR_ON[4]
	);	
	IF H_CHAMBER[3].PID_AUTO_TUNE_DONE
		THEN
		GV_H.CHAMBER_HEATER_PID[3].P:=H_CHAMBER[3].PID_AUTO_TUNE_P;
		GV_H.CHAMBER_HEATER_PID[3].I:=H_CHAMBER[3].PID_AUTO_TUNE_I;
		GV_H.CHAMBER_HEATER_PID[3].D:=H_CHAMBER[3].PID_AUTO_TUNE_D;
		GV.CHAMBER_HEATER_AUTO_TUNE_EN[3]:=FALSE;
	END_IF
//E18 GATE VALVE PID
	IF 	ABS(GV.AI.GATE_VALVE_Temp-GV.AO.Gate_Valve_Temp_SV)<5	
	THEN 
		H_GATE_VALVE.PID_Feedforward:=GV_H.GATE_VALVE_HEATER_PID.Feedforward;
	ELSE
		H_GATE_VALVE.PID_Feedforward:=0;
	END_IF
	H_GATE_VALVE(
	ENABLE:= GV.AI.GATE_VALVE_Temp<100, 
	AUTO_TUNE:= GV.GATE_VALVE_HEATER_AUTO_TUNE_EN, 
	AUTO_TUNE_OUTPUT:=GV.GATE_VALVE_HEATER_AUTO_TUNE_OUTPUT,
	TEMP_SV:= GV.AO.Gate_Valve_Temp_SV, 
	TEMP_ACTUAL:= GV.AI.GATE_VALVE_Temp, 
	TEMP_RATE:=5,
	PID_P:= GV_H.GATE_VALVE_HEATER_PID.P, 
	PID_I:= GV_H.GATE_VALVE_HEATER_PID.I, 
	PID_D:= GV_H.GATE_VALVE_HEATER_PID.D, 
	PID_Dp:= GV_H.GATE_VALVE_HEATER_PID.DP, 
	PID_Output_Limit:= GV_H.GATE_VALVE_HEATER_PID.Output_Limit,
	SSR_ON=> GV.GATE_VALVE_SSR_ON
	);		
	IF H_GATE_VALVE.PID_AUTO_TUNE_DONE
		THEN
		GV_H.GATE_VALVE_HEATER_PID.P:=H_GATE_VALVE.PID_AUTO_TUNE_P;
		GV_H.GATE_VALVE_HEATER_PID.I:=H_GATE_VALVE.PID_AUTO_TUNE_I;
		GV_H.GATE_VALVE_HEATER_PID.D:=H_GATE_VALVE.PID_AUTO_TUNE_D;
		GV.GATE_VALVE_HEATER_AUTO_TUNE_EN:=FALSE;
	END_IF	
	
//E31	TAPE1 PID		
	H_TAPE[1](
	ENABLE:= GV.AI.TAPE_Temp1<120, 
	AUTO_TUNE:= GV.TAPE_HEATER_AUTO_TUNE_EN[1],
	AUTO_TUNE_OUTPUT:=GV.TAPE_HEATER_AUTO_TUNE_OUTPUT[1], 
	TEMP_SV:= GV.AO.Tape_Temp1_SV, 
	TEMP_ACTUAL:= GV.AI.TAPE_Temp1,
	TEMP_RATE:=10, 
	PID_P:= GV_H.TAPE_HEATER_PID[1].P, 
	PID_I:= GV_H.TAPE_HEATER_PID[1].I, 
	PID_D:= GV_H.TAPE_HEATER_PID[1].D, 
	PID_Dp:= GV_H.TAPE_HEATER_PID[1].DP, 
	PID_Feedforward:= GV_H.TAPE_HEATER_PID[1].Feedforward,
	PID_Output_Limit:= GV_H.TAPE_HEATER_PID[1].Output_Limit,
	SSR_ON=> GV.TAPE_HEATER_SSR_ON[1]
	);	
	IF H_TAPE[1].PID_AUTO_TUNE_DONE
		THEN
		GV_H.TAPE_HEATER_PID[1].P:=H_TAPE[1].PID_AUTO_TUNE_P;
		GV_H.TAPE_HEATER_PID[1].I:=H_TAPE[1].PID_AUTO_TUNE_I;
		GV_H.TAPE_HEATER_PID[1].D:=H_TAPE[1].PID_AUTO_TUNE_D;
		GV.TAPE_HEATER_AUTO_TUNE_EN[1]:=FALSE;
	END_IF
//E32	TAPE2 PID		
	H_TAPE[2](
	ENABLE:= GV.AI.TAPE_Temp2<120, 
	AUTO_TUNE:= GV.TAPE_HEATER_AUTO_TUNE_EN[2], 
	AUTO_TUNE_OUTPUT:=GV.TAPE_HEATER_AUTO_TUNE_OUTPUT[2], 
	TEMP_SV:= GV.AO.Tape_Temp2_SV, 
	TEMP_ACTUAL:= GV.AI.TAPE_Temp2, 
	TEMP_RATE:=10,
	PID_P:= GV_H.TAPE_HEATER_PID[2].P, 
	PID_I:= GV_H.TAPE_HEATER_PID[2].I, 
	PID_D:= GV_H.TAPE_HEATER_PID[2].D, 
	PID_Dp:= GV_H.TAPE_HEATER_PID[2].DP, 
	PID_Feedforward:= GV_H.TAPE_HEATER_PID[2].Feedforward,
	PID_Output_Limit:= GV_H.TAPE_HEATER_PID[2].Output_Limit,
	SSR_ON=> GV.TAPE_HEATER_SSR_ON[2]
	);	
	IF H_TAPE[2].PID_AUTO_TUNE_DONE
		THEN
		GV_H.TAPE_HEATER_PID[2].P:=H_TAPE[2].PID_AUTO_TUNE_P;
		GV_H.TAPE_HEATER_PID[2].I:=H_TAPE[2].PID_AUTO_TUNE_I;
		GV_H.TAPE_HEATER_PID[2].D:=H_TAPE[2].PID_AUTO_TUNE_D;
		GV.TAPE_HEATER_AUTO_TUNE_EN[2]:=FALSE;
	END_IF
//	TAPE3 PID		
	H_TAPE[3](
	ENABLE:= GV.AI.TAPE_Temp3<120, 
	AUTO_TUNE:= GV.TAPE_HEATER_AUTO_TUNE_EN[3], 
	AUTO_TUNE_OUTPUT:=GV.TAPE_HEATER_AUTO_TUNE_OUTPUT[3], 
	TEMP_SV:= GV.AO.Tape_Temp3_SV, 
	TEMP_ACTUAL:= GV.AI.TAPE_Temp3, 
	TEMP_RATE:=10,
	PID_P:= GV_H.TAPE_HEATER_PID[3].P, 
	PID_I:= GV_H.TAPE_HEATER_PID[3].I, 
	PID_D:= GV_H.TAPE_HEATER_PID[3].D, 
	PID_Dp:= GV_H.TAPE_HEATER_PID[3].DP, 
	PID_Feedforward:= GV_H.TAPE_HEATER_PID[3].Feedforward,
	PID_Output_Limit:= GV_H.TAPE_HEATER_PID[3].Output_Limit,
	SSR_ON=> GV.TAPE_HEATER_SSR_ON[3]
	);	
	IF H_TAPE[3].PID_AUTO_TUNE_DONE
		THEN
		GV_H.TAPE_HEATER_PID[3].P:=H_TAPE[3].PID_AUTO_TUNE_P;
		GV_H.TAPE_HEATER_PID[3].I:=H_TAPE[3].PID_AUTO_TUNE_I;
		GV_H.TAPE_HEATER_PID[3].D:=H_TAPE[3].PID_AUTO_TUNE_D;
		GV.TAPE_HEATER_AUTO_TUNE_EN[3]:=FALSE;
	END_IF
//E35	IGS1 PID		
	H_IGS[1](
	ENABLE:= GV.AI.IGS_Temp1<50, 
	AUTO_TUNE:= GV.IGS_HEATER_AUTO_TUNE_EN[1], 
	AUTO_TUNE_OUTPUT:=GV.IGS_HEATER_AUTO_TUNE_OUTPUT[1], 
	TEMP_SV:= GV.AO.IGS_Temp1_SV, 
	TEMP_ACTUAL:= GV.AI.IGS_Temp1, 
	TEMP_RATE:=1.5,
	PID_P:= GV_H.IGS_HEATER_PID[1].P, 
	PID_I:= GV_H.IGS_HEATER_PID[1].I, 
	PID_D:= GV_H.IGS_HEATER_PID[1].D, 
	PID_Dp:= GV_H.IGS_HEATER_PID[1].DP, 
	PID_Feedforward:= GV_H.IGS_HEATER_PID[1].Feedforward,
	PID_Output_Limit:= GV_H.IGS_HEATER_PID[1].Output_Limit,
	SSR_ON=> GV.IGS_HEATER_SSR_ON[1]
	);	
	IF H_IGS[1].PID_AUTO_TUNE_DONE
		THEN
		GV_H.IGS_HEATER_PID[1].P:=H_IGS[1].PID_AUTO_TUNE_P;
		GV_H.IGS_HEATER_PID[1].I:=H_IGS[1].PID_AUTO_TUNE_I;
		GV_H.IGS_HEATER_PID[1].D:=H_IGS[1].PID_AUTO_TUNE_D;
		GV.IGS_HEATER_AUTO_TUNE_EN[1]:=FALSE;
	END_IF
//E36	IGS2 PID	
	IF 	GV.AI.IGS_Temp2>GV.AO.IGS_Temp2_SV+3 THEN 
		H_IGS[2].PID_Feedforward:=0;
		ELSE
			H_IGS[2].PID_Feedforward:=GV_H.IGS_HEATER_PID[2].Feedforward;
	
	END_IF
	H_IGS[2](
	ENABLE:= GV.AI.IGS_Temp2<50, 
	AUTO_TUNE:= GV.IGS_HEATER_AUTO_TUNE_EN[2], 
	AUTO_TUNE_OUTPUT:=GV.IGS_HEATER_AUTO_TUNE_OUTPUT[2],
	TEMP_SV:= GV.AO.IGS_Temp2_SV, 
	TEMP_ACTUAL:= GV.AI.IGS_Temp2, 
	TEMP_RATE:=1.5,
	PID_P:= GV_H.IGS_HEATER_PID[2].P, 
	PID_I:= GV_H.IGS_HEATER_PID[2].I, 
	PID_D:= GV_H.IGS_HEATER_PID[2].D, 
	PID_Dp:= GV_H.IGS_HEATER_PID[2].DP, 
	PID_Feedforward:= GV_H.IGS_HEATER_PID[2].Feedforward,
	PID_Output_Limit:= GV_H.IGS_HEATER_PID[2].Output_Limit,
	SSR_ON=> GV.IGS_HEATER_SSR_ON[2]
	);	
	IF H_IGS[2].PID_AUTO_TUNE_DONE
		THEN
		GV_H.IGS_HEATER_PID[2].P:=H_IGS[2].PID_AUTO_TUNE_P;
		GV_H.IGS_HEATER_PID[2].I:=H_IGS[2].PID_AUTO_TUNE_I;
		GV_H.IGS_HEATER_PID[2].D:=H_IGS[2].PID_AUTO_TUNE_D;
		GV.IGS_HEATER_AUTO_TUNE_EN[2]:=FALSE;
	END_IF
//FORELINE1 PID	SSR6	AV102	
	H_FORELINE[1](
	ENABLE:= GV.AI.AV102_Temp<120, 
	AUTO_TUNE:= GV.FORELINE_HEATER_AUTO_TUNE_EN[1], 
	AUTO_TUNE_OUTPUT:=GV.FORELINE_HEATER_AUTO_TUNE_OUTPUT[1],
	TEMP_SV:= GV.AO.AV102_Temp_SV, 
	TEMP_ACTUAL:= GV.AI.AV102_Temp, 
	TEMP_RATE:=10,
	PID_P:= GV_H.FORELINE_HEATER_PID[1].P, 
	PID_I:= GV_H.FORELINE_HEATER_PID[1].I, 
	PID_D:= GV_H.FORELINE_HEATER_PID[1].D, 
	PID_Dp:= GV_H.FORELINE_HEATER_PID[1].DP, 
	PID_Feedforward:= GV_H.FORELINE_HEATER_PID[1].Feedforward,
	PID_Output_Limit:= GV_H.FORELINE_HEATER_PID[1].Output_Limit,
	SSR_ON=> GV.FORELINE_HEATER_SSR_ON[1]);
	
	IF H_FORELINE[1].PID_AUTO_TUNE_DONE
		THEN
		GV_H.FORELINE_HEATER_PID[1].P:=H_FORELINE[1].PID_AUTO_TUNE_P;
		GV_H.FORELINE_HEATER_PID[1].I:=H_FORELINE[1].PID_AUTO_TUNE_I;
		GV_H.FORELINE_HEATER_PID[1].D:=H_FORELINE[1].PID_AUTO_TUNE_D;
		GV.FORELINE_HEATER_AUTO_TUNE_EN[1]:=FALSE;
	END_IF
//FORELINE2 PID		SSR7	AV101
	H_FORELINE[2](
	ENABLE:= GV.AI.AV101_Temp<120, 
	AUTO_TUNE:= GV.FORELINE_HEATER_AUTO_TUNE_EN[2], 
	AUTO_TUNE_OUTPUT:=GV.FORELINE_HEATER_AUTO_TUNE_OUTPUT[2],
	TEMP_SV:= GV.AO.AV101_Temp_SV, 
	TEMP_ACTUAL:= GV.AI.AV101_Temp, 
	TEMP_RATE:=10,
	PID_P:= GV_H.FORELINE_HEATER_PID[2].P, 
	PID_I:= GV_H.FORELINE_HEATER_PID[2].I, 
	PID_D:= GV_H.FORELINE_HEATER_PID[2].D, 
	PID_Dp:= GV_H.FORELINE_HEATER_PID[2].DP, 
	PID_Feedforward:= GV_H.FORELINE_HEATER_PID[2].Feedforward,
	PID_Output_Limit:= GV_H.FORELINE_HEATER_PID[2].Output_Limit,
	SSR_ON=> GV.FORELINE_HEATER_SSR_ON[2]);
	
	IF H_FORELINE[2].PID_AUTO_TUNE_DONE
		THEN
		GV_H.FORELINE_HEATER_PID[2].P:=H_FORELINE[2].PID_AUTO_TUNE_P;
		GV_H.FORELINE_HEATER_PID[2].I:=H_FORELINE[2].PID_AUTO_TUNE_I;
		GV_H.FORELINE_HEATER_PID[2].D:=H_FORELINE[2].PID_AUTO_TUNE_D;
		GV.FORELINE_HEATER_AUTO_TUNE_EN[2]:=FALSE;
	END_IF
//FORELINE3 PID		SSR8	AV106
	H_FORELINE[3](
	ENABLE:= GV.AI.AV106_Temp<120, 
	AUTO_TUNE:= GV.FORELINE_HEATER_AUTO_TUNE_EN[3], 
	AUTO_TUNE_OUTPUT:=GV.FORELINE_HEATER_AUTO_TUNE_OUTPUT[3],
	TEMP_SV:= GV.AO.AV106_Temp_SV ,
	TEMP_ACTUAL:= GV.AI.AV106_Temp, 
	TEMP_RATE:=10,
	PID_P:= GV_H.FORELINE_HEATER_PID[3].P, 
	PID_I:= GV_H.FORELINE_HEATER_PID[3].I, 
	PID_D:= GV_H.FORELINE_HEATER_PID[3].D, 
	PID_Dp:= GV_H.FORELINE_HEATER_PID[3].DP, 
	PID_Feedforward:= GV_H.FORELINE_HEATER_PID[3].Feedforward,
	PID_Output_Limit:= GV_H.FORELINE_HEATER_PID[3].Output_Limit,
	SSR_ON=> GV.FORELINE_HEATER_SSR_ON[3]);
	
	IF H_FORELINE[3].PID_AUTO_TUNE_DONE
		THEN
		GV_H.FORELINE_HEATER_PID[3].P:=H_FORELINE[3].PID_AUTO_TUNE_P;
		GV_H.FORELINE_HEATER_PID[3].I:=H_FORELINE[3].PID_AUTO_TUNE_I;
		GV_H.FORELINE_HEATER_PID[3].D:=H_FORELINE[3].PID_AUTO_TUNE_D;
		GV.FORELINE_HEATER_AUTO_TUNE_EN[3]:=FALSE;
	END_IF	
//FORELINE4 PID		SSR9	BA101
	H_FORELINE[4](
	ENABLE:= GV.AI.BA01_Temp<120, 
	AUTO_TUNE:= GV.FORELINE_HEATER_AUTO_TUNE_EN[4], 
	AUTO_TUNE_OUTPUT:=GV.FORELINE_HEATER_AUTO_TUNE_OUTPUT[4],
	TEMP_SV:= GV.AO.BA01_Temp_SV, 
	TEMP_ACTUAL:= GV.AI.BA01_Temp, 
	TEMP_RATE:=10,
	PID_P:= GV_H.FORELINE_HEATER_PID[4].P, 
	PID_I:= GV_H.FORELINE_HEATER_PID[4].I, 
	PID_D:= GV_H.FORELINE_HEATER_PID[4].D, 
	PID_Dp:= GV_H.FORELINE_HEATER_PID[4].DP, 
	PID_Feedforward:= GV_H.FORELINE_HEATER_PID[4].Feedforward,
	PID_Output_Limit:= GV_H.FORELINE_HEATER_PID[4].Output_Limit,
	SSR_ON=> GV.FORELINE_HEATER_SSR_ON[4]);
	
	IF H_FORELINE[4].PID_AUTO_TUNE_DONE
		THEN
		GV_H.FORELINE_HEATER_PID[4].P:=H_FORELINE[4].PID_AUTO_TUNE_P;
		GV_H.FORELINE_HEATER_PID[4].I:=H_FORELINE[4].PID_AUTO_TUNE_I;
		GV_H.FORELINE_HEATER_PID[4].D:=H_FORELINE[4].PID_AUTO_TUNE_D;
		GV.FORELINE_HEATER_AUTO_TUNE_EN[4]:=FALSE;
	END_IF
//FORELINE5 PID		SS10	VG103
	H_FORELINE[5](
	ENABLE:= GV.AI.VG103_Pipe_Temp<120, 
	AUTO_TUNE:= GV.FORELINE_HEATER_AUTO_TUNE_EN[5], 
	TEMP_SV:= GV.AO.VG103_Pipe_Temp_SV, 
	TEMP_ACTUAL:= GV.AI.VG103_Pipe_Temp, 
	TEMP_RATE:=10,
	PID_P:= GV_H.FORELINE_HEATER_PID[5].P, 
	PID_I:= GV_H.FORELINE_HEATER_PID[5].I, 
	PID_D:= GV_H.FORELINE_HEATER_PID[5].D, 
	PID_Dp:= GV_H.FORELINE_HEATER_PID[5].DP, 
	PID_Feedforward:= GV_H.FORELINE_HEATER_PID[5].Feedforward,
	PID_Output_Limit:= GV_H.FORELINE_HEATER_PID[5].Output_Limit,
	SSR_ON=> GV.FORELINE_HEATER_SSR_ON[5]);
	
	IF H_FORELINE[5].PID_AUTO_TUNE_DONE
		THEN
		GV_H.FORELINE_HEATER_PID[5].P:=H_FORELINE[5].PID_AUTO_TUNE_P;
		GV_H.FORELINE_HEATER_PID[5].I:=H_FORELINE[5].PID_AUTO_TUNE_I;
		GV_H.FORELINE_HEATER_PID[5].D:=H_FORELINE[5].PID_AUTO_TUNE_D;
		GV.FORELINE_HEATER_AUTO_TUNE_EN[5]:=FALSE;
	END_IF
//FORELINE6 PID		SSR11	EXHAUST1-6
	H_FORELINE[6](
	ENABLE:= GV.AI.Exhaust1_6_Temp<120, 
	AUTO_TUNE:= GV.FORELINE_HEATER_AUTO_TUNE_EN[6], 
	TEMP_SV:= GV.AO.Exhaust1_6_Temp_SV, 
	TEMP_ACTUAL:= GV.AI.Exhaust1_6_Temp,
	TEMP_RATE:=10, 
	PID_P:= GV_H.FORELINE_HEATER_PID[6].P, 
	PID_I:= GV_H.FORELINE_HEATER_PID[6].I, 
	PID_D:= GV_H.FORELINE_HEATER_PID[6].D, 
	PID_Dp:= GV_H.FORELINE_HEATER_PID[6].DP, 
	PID_Feedforward:= GV_H.FORELINE_HEATER_PID[6].Feedforward,
	PID_Output_Limit:= GV_H.FORELINE_HEATER_PID[6].Output_Limit,
	SSR_ON=> GV.FORELINE_HEATER_SSR_ON[6]);
	
	IF H_FORELINE[6].PID_AUTO_TUNE_DONE
		THEN
		GV_H.FORELINE_HEATER_PID[6].P:=H_FORELINE[6].PID_AUTO_TUNE_P;
		GV_H.FORELINE_HEATER_PID[6].I:=H_FORELINE[6].PID_AUTO_TUNE_I;
		GV_H.FORELINE_HEATER_PID[6].D:=H_FORELINE[6].PID_AUTO_TUNE_D;
		GV.FORELINE_HEATER_AUTO_TUNE_EN[6]:=FALSE;
	END_IF
//FORELINE7 PID		SSR12	EXHAUST7-8
	H_FORELINE[7](
	ENABLE:= GV.AI.Exhaust7_8_Temp<120, 
	AUTO_TUNE:= GV.FORELINE_HEATER_AUTO_TUNE_EN[7], 
	TEMP_SV:= GV.AO.Exhaust7_8_Temp_SV, 
	TEMP_ACTUAL:= GV.AI.Exhaust7_8_Temp, 
	TEMP_RATE:=10,
	PID_P:= GV_H.FORELINE_HEATER_PID[7].P, 
	PID_I:= GV_H.FORELINE_HEATER_PID[7].I, 
	PID_D:= GV_H.FORELINE_HEATER_PID[7].D, 
	PID_Dp:= GV_H.FORELINE_HEATER_PID[7].DP, 
	PID_Feedforward:= GV_H.FORELINE_HEATER_PID[7].Feedforward,
	PID_Output_Limit:= GV_H.FORELINE_HEATER_PID[7].Output_Limit,
	SSR_ON=> GV.FORELINE_HEATER_SSR_ON[7]);
	
	IF H_FORELINE[7].PID_AUTO_TUNE_DONE
		THEN
		GV_H.FORELINE_HEATER_PID[7].P:=H_FORELINE[7].PID_AUTO_TUNE_P;
		GV_H.FORELINE_HEATER_PID[7].I:=H_FORELINE[7].PID_AUTO_TUNE_I;
		GV_H.FORELINE_HEATER_PID[7].D:=H_FORELINE[7].PID_AUTO_TUNE_D;
		GV.FORELINE_HEATER_AUTO_TUNE_EN[7]:=FALSE;
	END_IF
//FORELINE8 PID		SSR13
	H_FORELINE[8](
	ENABLE:= GV.AI.VG101_Pipe_Temp<120, 
	AUTO_TUNE:= GV.FORELINE_HEATER_AUTO_TUNE_EN[8], 
	TEMP_SV:= GV.AO.VG101_Pipe_Temp_SV, 
	TEMP_ACTUAL:= GV.AI.VG101_Pipe_Temp, 
	TEMP_RATE:=10,
	PID_P:= GV_H.FORELINE_HEATER_PID[8].P, 
	PID_I:= GV_H.FORELINE_HEATER_PID[8].I, 
	PID_D:= GV_H.FORELINE_HEATER_PID[8].D, 
	PID_Dp:= GV_H.FORELINE_HEATER_PID[8].DP, 
	PID_Feedforward:= GV_H.FORELINE_HEATER_PID[8].Feedforward,
	PID_Output_Limit:= GV_H.FORELINE_HEATER_PID[8].Output_Limit,
	SSR_ON=> GV.FORELINE_HEATER_SSR_ON[8]);
	
	IF H_FORELINE[8].PID_AUTO_TUNE_DONE
		THEN
		GV_H.FORELINE_HEATER_PID[8].P:=H_FORELINE[8].PID_AUTO_TUNE_P;
		GV_H.FORELINE_HEATER_PID[8].I:=H_FORELINE[8].PID_AUTO_TUNE_I;
		GV_H.FORELINE_HEATER_PID[8].D:=H_FORELINE[8].PID_AUTO_TUNE_D;
		GV.FORELINE_HEATER_AUTO_TUNE_EN[8]:=FALSE;
	END_IF
(*	//FORELINE9 PID		
	H_FORELINE[9](
	ENABLE:= GV.AI.FORELINE_Temp9<120, 
	AUTO_TUNE:= GV.FORELINE_HEATER_AUTO_TUNE_EN[9], 
	TEMP_SV:= FORELINE_TEMP_SV[9], 
	TEMP_ACTUAL:= GV.AI.FORELINE_Temp9, 
	PID_P:= GV_H.FORELINE_HEATER_PID[9].P, 
	PID_I:= GV_H.FORELINE_HEATER_PID[9].I, 
	PID_D:= GV_H.FORELINE_HEATER_PID[9].D, 
	PID_Dp:= GV_H.FORELINE_HEATER_PID[9].DP, 
	PID_Feedforward:= GV_H.FORELINE_HEATER_PID[9].Feedforward,
	PID_Output_Limit:= GV_H.FORELINE_HEATER_PID[9].Output_Limit,
	SSR_ON=> GV.FORELINE_HEATER_SSR_ON[9]);
	
	IF H_FORELINE[9].PID_AUTO_TUNE_DONE
		THEN
		GV_H.FORELINE_HEATER_PID[9].P:=H_FORELINE[9].PID_AUTO_TUNE_P;
		GV_H.FORELINE_HEATER_PID[9].I:=H_FORELINE[9].PID_AUTO_TUNE_I;
		GV_H.FORELINE_HEATER_PID[9].D:=H_FORELINE[9].PID_AUTO_TUNE_D;
		GV.FORELINE_HEATER_AUTO_TUNE_EN[9]:=FALSE;
	END_IF
	//FORELINE10 PID		
	H_FORELINE[10](
	ENABLE:= GV.AI.FORELINE_Temp10<120, 
	AUTO_TUNE:= GV.FORELINE_HEATER_AUTO_TUNE_EN[10], 
	TEMP_SV:= FORELINE_TEMP_SV[10], 
	TEMP_ACTUAL:= GV.AI.FORELINE_Temp10, 
	PID_P:= GV_H.FORELINE_HEATER_PID[10].P, 
	PID_I:= GV_H.FORELINE_HEATER_PID[10].I, 
	PID_D:= GV_H.FORELINE_HEATER_PID[10].D, 
	PID_Dp:= GV_H.FORELINE_HEATER_PID[10].DP, 
	PID_Feedforward:= GV_H.FORELINE_HEATER_PID[10].Feedforward,
	PID_Output_Limit:= GV_H.FORELINE_HEATER_PID[10].Output_Limit,
	SSR_ON=> GV.FORELINE_HEATER_SSR_ON[10]);
	
	IF H_FORELINE[10].PID_AUTO_TUNE_DONE
		THEN
		GV_H.FORELINE_HEATER_PID[10].P:=H_FORELINE[10].PID_AUTO_TUNE_P;
		GV_H.FORELINE_HEATER_PID[10].I:=H_FORELINE[10].PID_AUTO_TUNE_I;
		GV_H.FORELINE_HEATER_PID[10].D:=H_FORELINE[10].PID_AUTO_TUNE_D;
		GV.FORELINE_HEATER_AUTO_TUNE_EN[10]:=FALSE;
	END_IF
	//FORELINE11 PID		
	H_FORELINE[11](
	ENABLE:= GV.AI.FORELINE_Temp11<120, 
	AUTO_TUNE:= GV.FORELINE_HEATER_AUTO_TUNE_EN[11], 
	TEMP_SV:= FORELINE_TEMP_SV[11], 
	TEMP_ACTUAL:= GV.AI.FORELINE_Temp11, 
	PID_P:= GV_H.FORELINE_HEATER_PID[11].P, 
	PID_I:= GV_H.FORELINE_HEATER_PID[11].I, 
	PID_D:= GV_H.FORELINE_HEATER_PID[11].D, 
	PID_Dp:= GV_H.FORELINE_HEATER_PID[11].DP, 
	PID_Feedforward:= ,
	PID_Output_Limit:= GV_H.FORELINE_HEATER_PID[11].Output_Limit,
	SSR_ON=> GV.FORELINE_HEATER_SSR_ON[11]);
	
	IF H_FORELINE[11].PID_AUTO_TUNE_DONE
		THEN
		GV_H.FORELINE_HEATER_PID[11].P:=H_FORELINE[11].PID_AUTO_TUNE_P;
		GV_H.FORELINE_HEATER_PID[11].I:=H_FORELINE[11].PID_AUTO_TUNE_I;
		GV_H.FORELINE_HEATER_PID[11].D:=H_FORELINE[11].PID_AUTO_TUNE_D;
		GV.FORELINE_HEATER_AUTO_TUNE_EN[11]:=FALSE;
	END_IF
	//FORELINE12 PID		
	H_FORELINE[12](
	ENABLE:= GV.AI.FORELINE_Temp12<120, 
	AUTO_TUNE:= GV.FORELINE_HEATER_AUTO_TUNE_EN[12], 
	TEMP_SV:= FORELINE_TEMP_SV[12], 
	TEMP_ACTUAL:= GV.AI.FORELINE_Temp12, 
	PID_P:= GV_H.FORELINE_HEATER_PID[12].P, 
	PID_I:= GV_H.FORELINE_HEATER_PID[12].I, 
	PID_D:= GV_H.FORELINE_HEATER_PID[12].D, 
	PID_Dp:= GV_H.FORELINE_HEATER_PID[12].DP, 
	PID_Feedforward:= ,
	PID_Output_Limit:= GV_H.FORELINE_HEATER_PID[12].Output_Limit,
	SSR_ON=> GV.FORELINE_HEATER_SSR_ON[12]);
	
	IF H_FORELINE[12].PID_AUTO_TUNE_DONE
		THEN
		GV_H.FORELINE_HEATER_PID[12].P:=H_FORELINE[12].PID_AUTO_TUNE_P;
		GV_H.FORELINE_HEATER_PID[12].I:=H_FORELINE[12].PID_AUTO_TUNE_I;
		GV_H.FORELINE_HEATER_PID[12].D:=H_FORELINE[12].PID_AUTO_TUNE_D;
		GV.FORELINE_HEATER_AUTO_TUNE_EN[12]:=FALSE;
	END_IF
	//FORELINE13 PID		
	H_FORELINE[13](
	ENABLE:= GV.AI.FORELINE_Temp13<120, 
	AUTO_TUNE:= GV.FORELINE_HEATER_AUTO_TUNE_EN[13], 
	TEMP_SV:= FORELINE_TEMP_SV[13], 
	TEMP_ACTUAL:= GV.AI.FORELINE_Temp13, 
	PID_P:= GV_H.FORELINE_HEATER_PID[13].P, 
	PID_I:= GV_H.FORELINE_HEATER_PID[13].I, 
	PID_D:= GV_H.FORELINE_HEATER_PID[13].D, 
	PID_Dp:= GV_H.FORELINE_HEATER_PID[13].DP, 
	PID_Feedforward:= ,
	PID_Output_Limit:= GV_H.FORELINE_HEATER_PID[13].Output_Limit,
	SSR_ON=> GV.FORELINE_HEATER_SSR_ON[13]);
	
	IF H_FORELINE[13].PID_AUTO_TUNE_DONE
		THEN
		GV_H.FORELINE_HEATER_PID[13].P:=H_FORELINE[13].PID_AUTO_TUNE_P;
		GV_H.FORELINE_HEATER_PID[13].I:=H_FORELINE[13].PID_AUTO_TUNE_I;
		GV_H.FORELINE_HEATER_PID[13].D:=H_FORELINE[13].PID_AUTO_TUNE_D;
		GV.FORELINE_HEATER_AUTO_TUNE_EN[13]:=FALSE;
	END_IF
	//FORELINE14 PID		
	H_FORELINE[14](
	ENABLE:= GV.AI.FORELINE_Temp14<120, 
	AUTO_TUNE:= GV.FORELINE_HEATER_AUTO_TUNE_EN[14], 
	TEMP_SV:= FORELINE_TEMP_SV[14], 
	TEMP_ACTUAL:= GV.AI.FORELINE_Temp14, 
	PID_P:= GV_H.FORELINE_HEATER_PID[14].P, 
	PID_I:= GV_H.FORELINE_HEATER_PID[14].I, 
	PID_D:= GV_H.FORELINE_HEATER_PID[14].D, 
	PID_Dp:= GV_H.FORELINE_HEATER_PID[14].DP, 
	PID_Feedforward:= ,
	PID_Output_Limit:= GV_H.FORELINE_HEATER_PID[14].Output_Limit,
	SSR_ON=> GV.FORELINE_HEATER_SSR_ON[14]);
	
	IF H_FORELINE[14].PID_AUTO_TUNE_DONE
		THEN
		GV_H.FORELINE_HEATER_PID[14].P:=H_FORELINE[14].PID_AUTO_TUNE_P;
		GV_H.FORELINE_HEATER_PID[14].I:=H_FORELINE[14].PID_AUTO_TUNE_I;
		GV_H.FORELINE_HEATER_PID[14].D:=H_FORELINE[14].PID_AUTO_TUNE_D;
		GV.FORELINE_HEATER_AUTO_TUNE_EN[14]:=FALSE;
	END_IF
	//FORELINE15 PID		
	H_FORELINE[15](
	ENABLE:= GV.AI.FORELINE_Temp15<120, 
	AUTO_TUNE:= GV.FORELINE_HEATER_AUTO_TUNE_EN[15], 
	TEMP_SV:= FORELINE_TEMP_SV[15], 
	TEMP_ACTUAL:= GV.AI.FORELINE_Temp15, 
	PID_P:= GV_H.FORELINE_HEATER_PID[15].P, 
	PID_I:= GV_H.FORELINE_HEATER_PID[15].I, 
	PID_D:= GV_H.FORELINE_HEATER_PID[15].D, 
	PID_Dp:= GV_H.FORELINE_HEATER_PID[15].DP, 
	PID_Feedforward:= ,
	PID_Output_Limit:= GV_H.FORELINE_HEATER_PID[15].Output_Limit,
	SSR_ON=> GV.FORELINE_HEATER_SSR_ON[15]);
	
	IF H_FORELINE[15].PID_AUTO_TUNE_DONE
		THEN
		GV_H.FORELINE_HEATER_PID[15].P:=H_FORELINE[15].PID_AUTO_TUNE_P;
		GV_H.FORELINE_HEATER_PID[15].I:=H_FORELINE[15].PID_AUTO_TUNE_I;
		GV_H.FORELINE_HEATER_PID[15].D:=H_FORELINE[15].PID_AUTO_TUNE_D;
		GV.FORELINE_HEATER_AUTO_TUNE_EN[15]:=FALSE;
	END_IF
	//FORELINE16 PID		
	H_FORELINE[16](
	ENABLE:= GV.AI.FORELINE_Temp16<120, 
	AUTO_TUNE:= GV.FORELINE_HEATER_AUTO_TUNE_EN[16], 
	TEMP_SV:= FORELINE_TEMP_SV[16], 
	TEMP_ACTUAL:= GV.AI.FORELINE_Temp16, 
	PID_P:= GV_H.FORELINE_HEATER_PID[16].P, 
	PID_I:= GV_H.FORELINE_HEATER_PID[16].I, 
	PID_D:= GV_H.FORELINE_HEATER_PID[16].D, 
	PID_Dp:= GV_H.FORELINE_HEATER_PID[16].DP, 
	PID_Feedforward:= ,
	PID_Output_Limit:= GV_H.FORELINE_HEATER_PID[16].Output_Limit,
	SSR_ON=> GV.FORELINE_HEATER_SSR_ON[16]);
	
	IF H_FORELINE[16].PID_AUTO_TUNE_DONE
		THEN
		GV_H.FORELINE_HEATER_PID[16].P:=H_FORELINE[16].PID_AUTO_TUNE_P;
		GV_H.FORELINE_HEATER_PID[16].I:=H_FORELINE[16].PID_AUTO_TUNE_I;
		GV_H.FORELINE_HEATER_PID[16].D:=H_FORELINE[16].PID_AUTO_TUNE_D;
		GV.FORELINE_HEATER_AUTO_TUNE_EN[16]:=FALSE;
	END_IF
	//FORELINE17 PID		
	H_FORELINE[17](
	ENABLE:= GV.AI.FORELINE_Temp17<120, 
	AUTO_TUNE:= GV.FORELINE_HEATER_AUTO_TUNE_EN[17], 
	TEMP_SV:= FORELINE_TEMP_SV[17], 
	TEMP_ACTUAL:= GV.AI.FORELINE_Temp17, 
	PID_P:= GV_H.FORELINE_HEATER_PID[17].P, 
	PID_I:= GV_H.FORELINE_HEATER_PID[17].I, 
	PID_D:= GV_H.FORELINE_HEATER_PID[17].D, 
	PID_Dp:= GV_H.FORELINE_HEATER_PID[17].DP, 
	PID_Feedforward:= ,
	PID_Output_Limit:= GV_H.FORELINE_HEATER_PID[17].Output_Limit,
	SSR_ON=> GV.FORELINE_HEATER_SSR_ON[17]);
	
	IF H_FORELINE[17].PID_AUTO_TUNE_DONE
		THEN
		GV_H.FORELINE_HEATER_PID[17].P:=H_FORELINE[17].PID_AUTO_TUNE_P;
		GV_H.FORELINE_HEATER_PID[17].I:=H_FORELINE[17].PID_AUTO_TUNE_I;
		GV_H.FORELINE_HEATER_PID[17].D:=H_FORELINE[17].PID_AUTO_TUNE_D;
		GV.FORELINE_HEATER_AUTO_TUNE_EN[17]:=FALSE;
	END_IF
	//FORELINE18 PID		
	H_FORELINE[18](
	ENABLE:= GV.AI.FORELINE_Temp18<120, 
	AUTO_TUNE:= GV.FORELINE_HEATER_AUTO_TUNE_EN[18], 
	TEMP_SV:= FORELINE_TEMP_SV[18], 
	TEMP_ACTUAL:= GV.AI.FORELINE_Temp18, 
	PID_P:= GV_H.FORELINE_HEATER_PID[18].P, 
	PID_I:= GV_H.FORELINE_HEATER_PID[18].I, 
	PID_D:= GV_H.FORELINE_HEATER_PID[18].D, 
	PID_Dp:= GV_H.FORELINE_HEATER_PID[18].DP, 
	PID_Feedforward:= ,
	PID_Output_Limit:= GV_H.FORELINE_HEATER_PID[18].Output_Limit,
	SSR_ON=> GV.FORELINE_HEATER_SSR_ON[18]);
	
	IF H_FORELINE[18].PID_AUTO_TUNE_DONE
		THEN
		GV_H.FORELINE_HEATER_PID[18].P:=H_FORELINE[18].PID_AUTO_TUNE_P;
		GV_H.FORELINE_HEATER_PID[18].I:=H_FORELINE[18].PID_AUTO_TUNE_I;
		GV_H.FORELINE_HEATER_PID[18].D:=H_FORELINE[18].PID_AUTO_TUNE_D;
		GV.FORELINE_HEATER_AUTO_TUNE_EN[18]:=FALSE;
	END_IF
	//FORELINE19 PID		
	H_FORELINE[19](
	ENABLE:= GV.AI.FORELINE_Temp19<120, 
	AUTO_TUNE:= GV.FORELINE_HEATER_AUTO_TUNE_EN[19], 
	TEMP_SV:= FORELINE_TEMP_SV[19], 
	TEMP_ACTUAL:= GV.AI.FORELINE_Temp19, 
	PID_P:= GV_H.FORELINE_HEATER_PID[19].P, 
	PID_I:= GV_H.FORELINE_HEATER_PID[19].I, 
	PID_D:= GV_H.FORELINE_HEATER_PID[19].D, 
	PID_Dp:= GV_H.FORELINE_HEATER_PID[19].DP, 
	PID_Feedforward:= ,
	PID_Output_Limit:= GV_H.FORELINE_HEATER_PID[19].Output_Limit,
	SSR_ON=> GV.FORELINE_HEATER_SSR_ON[19]);
	
	IF H_FORELINE[19].PID_AUTO_TUNE_DONE
		THEN
		GV_H.FORELINE_HEATER_PID[19].P:=H_FORELINE[19].PID_AUTO_TUNE_P;
		GV_H.FORELINE_HEATER_PID[19].I:=H_FORELINE[19].PID_AUTO_TUNE_I;
		GV_H.FORELINE_HEATER_PID[19].D:=H_FORELINE[19].PID_AUTO_TUNE_D;
		GV.FORELINE_HEATER_AUTO_TUNE_EN[19]:=FALSE;
	END_IF
	//FORELINE20 PID		
	H_FORELINE[20](
	ENABLE:= GV.AI.FORELINE_Temp20<120, 
	AUTO_TUNE:= GV.FORELINE_HEATER_AUTO_TUNE_EN[20], 
	TEMP_SV:= FORELINE_TEMP_SV[20], 
	TEMP_ACTUAL:= GV.AI.FORELINE_Temp20, 
	PID_P:= GV_H.FORELINE_HEATER_PID[20].P, 
	PID_I:= GV_H.FORELINE_HEATER_PID[20].I, 
	PID_D:= GV_H.FORELINE_HEATER_PID[20].D, 
	PID_Dp:= GV_H.FORELINE_HEATER_PID[20].DP, 
	PID_Feedforward:= ,
	PID_Output_Limit:= GV_H.FORELINE_HEATER_PID[20].Output_Limit,
	SSR_ON=> GV.FORELINE_HEATER_SSR_ON[20]);
	
	IF H_FORELINE[20].PID_AUTO_TUNE_DONE
		THEN
		GV_H.FORELINE_HEATER_PID[20].P:=H_FORELINE[20].PID_AUTO_TUNE_P;
		GV_H.FORELINE_HEATER_PID[20].I:=H_FORELINE[20].PID_AUTO_TUNE_I;
		GV_H.FORELINE_HEATER_PID[20].D:=H_FORELINE[20].PID_AUTO_TUNE_D;
		GV.FORELINE_HEATER_AUTO_TUNE_EN[20]:=FALSE;
	END_IF
	*)

END_PROGRAM

// ---- POUs/FB/Temp_controller.TcPOU
FUNCTION_BLOCK Temp_controller
VAR_INPUT
	ENABLE:BOOL;
	AUTO_TUNE:BOOL;
	AUTO_TUNE_OUTPUT:REAL;
	//FILTER_ENABLE:BOOL;		
	TEMP_SV:REAL;
	TEMP_ACTUAL:REAL;
	
	TEMP_RATE:REAL;
	
	PID_P:REAL;
	PID_I:REAL;
	PID_D:REAL;
	PID_Dp:REAL;
	PID_Feedforward:REAL;
	PID_Output_Limit:REAL;
END_VAR
VAR_OUTPUT
	PID_AUTO_TUNE_P,
	PID_AUTO_TUNE_I,
	PID_AUTO_TUNE_D:REAL;
	PID_AUTO_TUNE_DONE:BOOL;
	SCR_OUT:REAL;
	SSR_ON:BOOL;
END_VAR
VAR
	SAMPLING_TIME:TIME:=T#1S;	//采样时间
	
	PID_NM : FB_CTRL_PID;
	PID_PARAMS:ST_CTRL_PID_PARAMS;
	PID_MODE:E_CTRL_MODE;
	PID_OUTPUT:LREAL;
	PID_FUC_STATE:E_CTRL_STATE;
	PID_ERRID:E_CTRL_ERRORCODES;
	PID_ERR:BOOL;
	PID_TASKTIME:TIME:=T#800MS;
	PID_CYCLETIME:TIME:=T#800MS;
	
	SSR_ON_PERCENT:REAL;
	
	TEMP_DATA_ARR : ARRAY[1..10] OF REAL;	//FIFO
	
	FIRST_RUN:R_TRIG;
	
	SAMPLING_TON1:TON;
	SAMPLING_TON2:TON;
	SAMPLING_TON1_EN:BOOL;
	SAMPLING_TON2_EN:BOOL;
	
	TEMP_AVERAGE:REAL;
	
	i: INT;
	
	SSR_ON_TIME:TIME;
	SSR_RESET_TIME:TIME;
	SSR_ON_TON:TON;
	SSR_RESET_TON:TON;
	SSR_ON_ENABLE:BOOL;
	SSR_RESET_ENABLE:BOOL;
	
	PID_AUTO_TUNE:PID_AutoTune;
	
	TON_FOR_RATE:TON;
	CACHE_TEMP_SV:REAL;
	TEMP_SV_TO_PID:REAL;
	EACH_STEP_TEMP:REAL;
END_VAR

//TEMP_RATE
EACH_STEP_TEMP:=TEMP_RATE/10;
IF TEMP_RATE=0 THEN 
	TEMP_SV_TO_PID:=TEMP_SV;
	ELSE
		IF ENABLE AND TON_FOR_RATE.IN=FALSE AND CACHE_TEMP_SV<TEMP_SV THEN
			TON_FOR_RATE.IN:=TRUE;
		END_IF			
		IF 	TON_FOR_RATE.Q THEN
			CACHE_TEMP_SV:=CACHE_TEMP_SV+EACH_STEP_TEMP;
			TON_FOR_RATE.IN:=FALSE;
		END_IF
			TON_FOR_RATE(IN:=, PT:= T#6S, Q=> , ET=> );
		IF CACHE_TEMP_SV<TEMP_SV THEN
			TEMP_SV_TO_PID:=CACHE_TEMP_SV;
		ELSE 
			TEMP_SV_TO_PID:=TEMP_SV;
		END_IF
END_IF

IF TEMP_RATE=0 OR NOT ENABLE THEN 
	CACHE_TEMP_SV:=0;
END_IF

IF (TEMP_RATE<>0) AND ENABLE AND (CACHE_TEMP_SV=0 OR CACHE_TEMP_SV>TEMP_SV) THEN 
	CACHE_TEMP_SV:=TEMP_AVERAGE+EACH_STEP_TEMP;
END_IF



//数组数据初始化
FIRST_RUN(CLK:=ENABLE,Q=> );
IF FIRST_RUN.Q
	THEN
	SAMPLING_TON1_EN:=TRUE;
	FOR i:=1  TO 10 BY 1
	DO
	TEMP_DATA_ARR[i] := TEMP_ACTUAL;
	END_FOR;
END_IF;

//产生采样脉冲
SAMPLING_TON1(IN:=SAMPLING_TON1_EN , PT:=SAMPLING_TIME , Q=> , ET=> );
IF SAMPLING_TON1.Q 
	THEN
	SAMPLING_TON1_EN:=0;
	SAMPLING_TON2_EN:=1;
END_IF;
SAMPLING_TON2(IN:=SAMPLING_TON2_EN , PT:=SAMPLING_TIME , Q=> , ET=> );
IF SAMPLING_TON2.Q 
	THEN 
	SAMPLING_TON1_EN:=1;
	SAMPLING_TON2_EN:=0;
END_IF;

//数组右移一位
IF SAMPLING_TON1.Q OR SAMPLING_TON2.Q		
	THEN 
	TEMP_DATA_ARR[10]	:= 	TEMP_DATA_ARR[9];
	TEMP_DATA_ARR[9] 	:= 	TEMP_DATA_ARR[8];
	TEMP_DATA_ARR[8]	:= 	TEMP_DATA_ARR[7];
	TEMP_DATA_ARR[7] 	:= 	TEMP_DATA_ARR[6];
	TEMP_DATA_ARR[6] 	:=	TEMP_DATA_ARR[5];
	TEMP_DATA_ARR[5] 	:= 	TEMP_DATA_ARR[4];
	TEMP_DATA_ARR[4] 	:= 	TEMP_DATA_ARR[3];
	TEMP_DATA_ARR[3] 	:= 	TEMP_DATA_ARR[2];
	TEMP_DATA_ARR[2] 	:= 	TEMP_DATA_ARR[1];
	TEMP_DATA_ARR[1] 	:= 	TEMP_ACTUAL;
END_IF

//取平均数，前两个数据权重为0.5，中间4位权重为0.3，最后4位权重为0.2。原则上，时间越久，权重越小
	TEMP_AVERAGE:=0.5*(TEMP_DATA_ARR[1]+TEMP_DATA_ARR[2])/2
				 +0.3*(TEMP_DATA_ARR[3]+TEMP_DATA_ARR[4]+TEMP_DATA_ARR[5]+TEMP_DATA_ARR[6])/4
				 +0.2*(TEMP_DATA_ARR[7]+TEMP_DATA_ARR[8]+TEMP_DATA_ARR[9]+TEMP_DATA_ARR[10])/4;

	IF 	AUTO_TUNE
		THEN			 
			PID_MODE:=0;
		ELSE
			PID_MODE:=2;
	END_IF;

	PID_AUTO_TUNE(
		PV:= TEMP_ACTUAL, 
		AutoTuneActive:= AUTO_TUNE, 
		StepResponseAmplitude:=AUTO_TUNE_OUTPUT,
		Output=> 	, 
		Kp=> 		PID_AUTO_TUNE_P, 
		Ki=> 		PID_AUTO_TUNE_I, 
		Kd=> 		PID_AUTO_TUNE_D, 
		Done=> 		PID_AUTO_TUNE_DONE);
		
//*******PID的背景数据块							G(S)=Kp[1+1/Tn+Tv/(1+Td)]
	PID_PARAMS.tTaskCycleTime		:=T#10MS;			//任务周期
	PID_PARAMS.tCtrlCycleTime		:=T#500MS;			//控制循环时间
	PID_PARAMS.fKp					:=PID_P;			//P
	PID_PARAMS.tTn					:=REAL_TO_TIME(PID_I);			//I
	PID_PARAMS.tTv					:=REAL_TO_TIME(PID_D);			//D
	PID_PARAMS.tTd					:=REAL_TO_TIME(PID_Dp);			//DAMP阻尼时间
	PID_PARAMS.fOutMaxLimit			:=100;				//输出上限
	PID_PARAMS.fOutMinLimit			:=0;				//输出下限
	PID_PARAMS.bPInTheFeedbackPath	:=FALSE;			//P有效
	PID_PARAMS.bDInTheFeedbackPath	:=FALSE;			//D有效
	PID_PARAMS.bARWOnIPartOnly		:=FALSE;			//I有效

//PID函数
	PID_NM(
		fSetpointValue:= TEMP_SV_TO_PID, 						//设定值
		fActualValue:= TEMP_AVERAGE, 					//实际值
		fManSyncValue:= , 								//操作值
		bSync:= , 										//上升沿时，操作值有效
		eMode:= PID_MODE, 								//函数的运行模式，0:空闲,1:PASSIVE,2:ACTIVE,3:RESET,4:MANUAL,5:AUTO,6:SELF-TUNING,7:SYNC同步模式
		bHold:= , 										//TRUE时，保持当前的内部状态
		fOut=> PID_OUTPUT, 								//输出值
		bARWactive=> , 									//TRUE时，表示PID输出值被限制
		eState=> PID_FUC_STATE, 						//函数状态
		eErrorId=> PID_ERRID, 							//ERR代码
		bError=> PID_ERR, 								//PID发生错误
		stParams:=PID_PARAMS );
		
	IF AUTO_TUNE 
		THEN 
		SSR_ON_PERCENT:=PID_AUTO_TUNE.Output+PID_Feedforward;		
		ELSE
		SSR_ON_PERCENT:=LREAL_TO_REAL(PID_OUTPUT+PID_Feedforward);
	END_IF
	
	IF SSR_ON_PERCENT>PID_Output_Limit AND ENABLE
		THEN 
		SSR_ON_PERCENT:=PID_Output_Limit;
	END_IF	
	IF SSR_ON_PERCENT<0 OR NOT ENABLE
		THEN 
		SSR_ON_PERCENT:=0;
	END_IF	

	SCR_OUT:=SSR_ON_PERCENT;
	
//*******PWM脉冲输出生成	
	
	SSR_ON_TIME:=REAL_TO_TIME(SSR_ON_PERCENT*10);									//输出脉冲ON宽度
	SSR_RESET_TIME:=REAL_TO_TIME((100-SSR_ON_PERCENT)*10);							//输出脉冲总宽度
	SSR_ON_TON(IN:= SSR_ON_ENABLE, PT:= SSR_ON_TIME, Q=> , ET=> );					//输出脉冲计时
	IF SSR_ON_TON.Q 																//输出脉冲计时器使能在计时器下方ON，实现上升脉冲；同时复位计时器使能OFF
		THEN 
		SSR_RESET_ENABLE:=TRUE;
	END_IF
	IF NOT (SSR_ON_ENABLE OR SSR_RESET_ENABLE)										//首次cycle触发输出脉冲使能
		THEN
		SSR_ON_ENABLE:=TRUE;
	END_IF
	SSR_RESET_TON(IN:= SSR_RESET_ENABLE, PT:= SSR_RESET_TIME, Q=> , ET=> );
	IF SSR_RESET_TON.Q 
		THEN 
		SSR_ON_ENABLE:=FALSE;
		SSR_RESET_ENABLE:=FALSE;
		SSR_ON:=FALSE;																//输出脉冲计时器使能OFF
	END_IF
	IF SSR_ON_PERCENT>0
		THEN 
		SSR_ON:=NOT SSR_ON_TON.Q;
	END_IF

END_FUNCTION_BLOCK

// ---- POUs/FB/PID_AutoTune.TcPOU
FUNCTION_BLOCK PID_AutoTune
VAR_INPUT
	PV : REAL; // 过程变量（Process Value），即当前温度
	AutoTuneActive : BOOL;
	StepResponseAmplitude : REAL := 20.0; // 阶跃响应的输出幅度
END_VAR
VAR_OUTPUT
	Output 	: REAL; // 控制器输出
    Kp 		: REAL; // 比例增益
    Ki 		: REAL; // 积分增益
    Kd 		: REAL; // 微分增益
	Done	: BOOL;
END_VAR
VAR
    StepResponseStartTime : REAL := 0.0; // 阶跃响应开始时间（以秒为单位）
    StepResponsePVStart : REAL; // 阶跃响应开始时的PV值
    StepResponsePVEnd : REAL; // 阶跃响应结束时的PV值
    StepResponseTime : REAL; // 阶跃响应时间（以秒为单位）
    Ku : REAL; // 临界增益
    Tu : REAL; // 临界周期（以秒为单位）
    // 时间相关变量
    CurrentTime : REAL; // 当前时间（以秒为单位）
	NT_Time:TIME;
	D_Dec:TON;
	monitor:REAL;
END_VAR

	D_Dec(IN:= AutoTuneActive, PT:= T#1600S, Q=> , ET=> NT_Time);	
	CurrentTime := TIME_TO_REAL(NT_Time) / 1000.0; 	// 将毫秒转换为秒
	IF NOT AutoTuneActive 
		THEN 
		StepResponseStartTime := 0.0;	
		IF Done 
			THEN 
			Done := FALSE;
		END_IF;
	END_IF;
	monitor:=StepResponsePVStart + StepResponseAmplitude * 0.63;
	IF AutoTuneActive THEN
		// 开始阶跃响应测试
		IF StepResponseStartTime = 0.0 THEN
			StepResponseStartTime := CurrentTime; 	// 记录开始时间
			StepResponsePVStart := PV; 				// 记录初始PV值
			Output := StepResponseAmplitude;		// 设置阶跃输出
		END_IF
	
		// 等待系统响应
		IF PV >= StepResponsePVStart + StepResponseAmplitude * 0.63 THEN
			StepResponseTime := CurrentTime - StepResponseStartTime; // 计算响应时间
			StepResponsePVEnd := PV; // 记录结束PV值
			AutoTuneActive := FALSE; // 结束自整定
			Done:=TRUE;
	
			Ku := 4 * StepResponseAmplitude / (StepResponsePVEnd - StepResponsePVStart); // 临界增益
			Tu := StepResponseTime; // 临界周期

			Kp := 0.6 * Ku;
			Ki := 1.2 * Ku / Tu;
			Kd := 0.075 * Ku * Tu;
		END_IF
	END_IF

END_FUNCTION_BLOCK
